VERSION 5.8 ;
BUSBITCHARS "[]" ;
DIVIDERCHAR "/" ;
UNITS
    DATABASE MICRONS 1000 ;
END UNITS

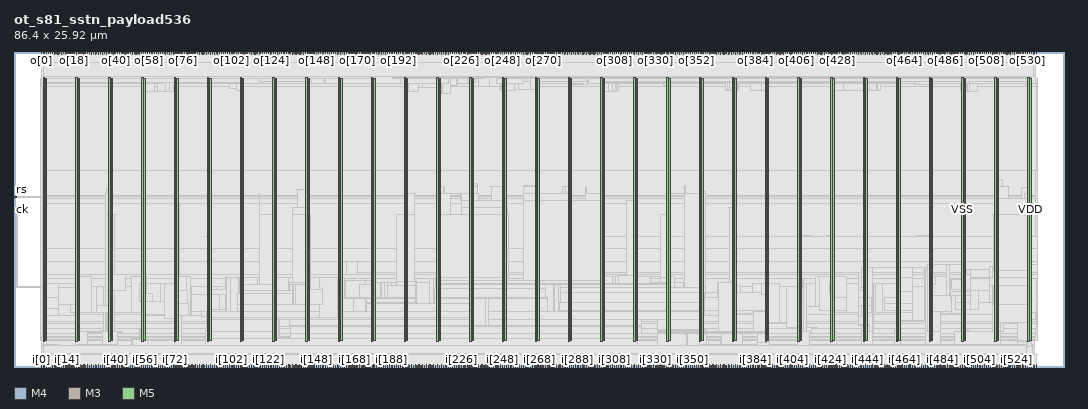
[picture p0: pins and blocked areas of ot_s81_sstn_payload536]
MACRO ot_s81_sstn_payload536
  FOREIGN ot_s81_sstn_payload536 0 0 ;
  CLASS BLOCK ;
  SIZE 86.4 BY 25.92 ;
  PIN ck
    DIRECTION INPUT ;
    USE SIGNAL ;
    PORT
      LAYER M4 ;
        RECT  0 12.96 0.192 12.984 ;
    END
  END ck
  PIN i[0]
    DIRECTION INPUT ;
    USE SIGNAL ;
    PORT
      LAYER M3 ;
        RECT  2.232 0 2.25 0.144 ;
    END
  END i[0]
  PIN i[100]
    DIRECTION INPUT ;
    USE SIGNAL ;
    PORT
      LAYER M3 ;
        RECT  17.532 0 17.55 0.144 ;
    END
  END i[100]
  PIN i[101]
    DIRECTION INPUT ;
    USE SIGNAL ;
    PORT
      LAYER M5 ;
        RECT  17.712 0 17.736 0.192 ;
    END
  END i[101]
  PIN i[102]
    DIRECTION INPUT ;
    USE SIGNAL ;
    PORT
      LAYER M3 ;
        RECT  17.856 0 17.874 0.144 ;
    END
  END i[102]
  PIN i[103]
    DIRECTION INPUT ;
    USE SIGNAL ;
    PORT
      LAYER M5 ;
        RECT  18 0 18.024 0.192 ;
    END
  END i[103]
  PIN i[104]
    DIRECTION INPUT ;
    USE SIGNAL ;
    PORT
      LAYER M3 ;
        RECT  18.144 0 18.162 0.144 ;
    END
  END i[104]
  PIN i[105]
    DIRECTION INPUT ;
    USE SIGNAL ;
    PORT
      LAYER M5 ;
        RECT  18.288 0 18.312 0.192 ;
    END
  END i[105]
  PIN i[106]
    DIRECTION INPUT ;
    USE SIGNAL ;
    PORT
      LAYER M3 ;
        RECT  18.468 0 18.486 0.144 ;
    END
  END i[106]
  PIN i[107]
    DIRECTION INPUT ;
    USE SIGNAL ;
    PORT
      LAYER M5 ;
        RECT  18.624 0 18.648 0.192 ;
    END
  END i[107]
  PIN i[108]
    DIRECTION INPUT ;
    USE SIGNAL ;
    PORT
      LAYER M3 ;
        RECT  18.756 0 18.774 0.144 ;
    END
  END i[108]
  PIN i[109]
    DIRECTION INPUT ;
    USE SIGNAL ;
    PORT
      LAYER M5 ;
        RECT  18.912 0 18.936 0.192 ;
    END
  END i[109]
  PIN i[10]
    DIRECTION INPUT ;
    USE SIGNAL ;
    PORT
      LAYER M3 ;
        RECT  3.744 0 3.762 0.144 ;
    END
  END i[10]
  PIN i[110]
    DIRECTION INPUT ;
    USE SIGNAL ;
    PORT
      LAYER M3 ;
        RECT  19.08 0 19.098 0.144 ;
    END
  END i[110]
  PIN i[111]
    DIRECTION INPUT ;
    USE SIGNAL ;
    PORT
      LAYER M5 ;
        RECT  19.2 0 19.224 0.192 ;
    END
  END i[111]
  PIN i[112]
    DIRECTION INPUT ;
    USE SIGNAL ;
    PORT
      LAYER M3 ;
        RECT  19.368 0 19.386 0.144 ;
    END
  END i[112]
  PIN i[113]
    DIRECTION INPUT ;
    USE SIGNAL ;
    PORT
      LAYER M5 ;
        RECT  19.536 0 19.56 0.192 ;
    END
  END i[113]
  PIN i[114]
    DIRECTION INPUT ;
    USE SIGNAL ;
    PORT
      LAYER M3 ;
        RECT  19.692 0 19.71 0.144 ;
    END
  END i[114]
  PIN i[115]
    DIRECTION INPUT ;
    USE SIGNAL ;
    PORT
      LAYER M5 ;
        RECT  19.824 0 19.848 0.192 ;
    END
  END i[115]
  PIN i[116]
    DIRECTION INPUT ;
    USE SIGNAL ;
    PORT
      LAYER M3 ;
        RECT  19.98 0 19.998 0.144 ;
    END
  END i[116]
  PIN i[117]
    DIRECTION INPUT ;
    USE SIGNAL ;
    PORT
      LAYER M5 ;
        RECT  20.16 0 20.184 0.192 ;
    END
  END i[117]
  PIN i[118]
    DIRECTION INPUT ;
    USE SIGNAL ;
    PORT
      LAYER M3 ;
        RECT  20.304 0 20.322 0.144 ;
    END
  END i[118]
  PIN i[119]
    DIRECTION INPUT ;
    USE SIGNAL ;
    PORT
      LAYER M5 ;
        RECT  20.448 0 20.472 0.192 ;
    END
  END i[119]
  PIN i[11]
    DIRECTION INPUT ;
    USE SIGNAL ;
    PORT
      LAYER M5 ;
        RECT  3.888 0 3.912 0.192 ;
    END
  END i[11]
  PIN i[120]
    DIRECTION INPUT ;
    USE SIGNAL ;
    PORT
      LAYER M3 ;
        RECT  20.592 0 20.61 0.144 ;
    END
  END i[120]
  PIN i[121]
    DIRECTION INPUT ;
    USE SIGNAL ;
    PORT
      LAYER M5 ;
        RECT  20.736 0 20.76 0.192 ;
    END
  END i[121]
  PIN i[122]
    DIRECTION INPUT ;
    USE SIGNAL ;
    PORT
      LAYER M3 ;
        RECT  20.916 0 20.934 0.144 ;
    END
  END i[122]
  PIN i[123]
    DIRECTION INPUT ;
    USE SIGNAL ;
    PORT
      LAYER M5 ;
        RECT  21.072 0 21.096 0.192 ;
    END
  END i[123]
  PIN i[124]
    DIRECTION INPUT ;
    USE SIGNAL ;
    PORT
      LAYER M3 ;
        RECT  21.204 0 21.222 0.144 ;
    END
  END i[124]
  PIN i[125]
    DIRECTION INPUT ;
    USE SIGNAL ;
    PORT
      LAYER M5 ;
        RECT  21.36 0 21.384 0.192 ;
    END
  END i[125]
  PIN i[126]
    DIRECTION INPUT ;
    USE SIGNAL ;
    PORT
      LAYER M3 ;
        RECT  21.528 0 21.546 0.144 ;
    END
  END i[126]
  PIN i[127]
    DIRECTION INPUT ;
    USE SIGNAL ;
    PORT
      LAYER M5 ;
        RECT  21.696 0 21.72 0.192 ;
    END
  END i[127]
  PIN i[128]
    DIRECTION INPUT ;
    USE SIGNAL ;
    PORT
      LAYER M3 ;
        RECT  21.816 0 21.834 0.144 ;
    END
  END i[128]
  PIN i[129]
    DIRECTION INPUT ;
    USE SIGNAL ;
    PORT
      LAYER M5 ;
        RECT  21.984 0 22.008 0.192 ;
    END
  END i[129]
  PIN i[12]
    DIRECTION INPUT ;
    USE SIGNAL ;
    PORT
      LAYER M3 ;
        RECT  4.068 0 4.086 0.144 ;
    END
  END i[12]
  PIN i[130]
    DIRECTION INPUT ;
    USE SIGNAL ;
    PORT
      LAYER M3 ;
        RECT  22.14 0 22.158 0.144 ;
    END
  END i[130]
  PIN i[131]
    DIRECTION INPUT ;
    USE SIGNAL ;
    PORT
      LAYER M5 ;
        RECT  22.272 0 22.296 0.192 ;
    END
  END i[131]
  PIN i[132]
    DIRECTION INPUT ;
    USE SIGNAL ;
    PORT
      LAYER M3 ;
        RECT  22.428 0 22.446 0.144 ;
    END
  END i[132]
  PIN i[133]
    DIRECTION INPUT ;
    USE SIGNAL ;
    PORT
      LAYER M5 ;
        RECT  22.608 0 22.632 0.192 ;
    END
  END i[133]
  PIN i[134]
    DIRECTION INPUT ;
    USE SIGNAL ;
    PORT
      LAYER M3 ;
        RECT  22.752 0 22.77 0.144 ;
    END
  END i[134]
  PIN i[135]
    DIRECTION INPUT ;
    USE SIGNAL ;
    PORT
      LAYER M5 ;
        RECT  22.896 0 22.92 0.192 ;
    END
  END i[135]
  PIN i[136]
    DIRECTION INPUT ;
    USE SIGNAL ;
    PORT
      LAYER M3 ;
        RECT  23.04 0 23.058 0.144 ;
    END
  END i[136]
  PIN i[137]
    DIRECTION INPUT ;
    USE SIGNAL ;
    PORT
      LAYER M5 ;
        RECT  23.184 0 23.208 0.192 ;
    END
  END i[137]
  PIN i[138]
    DIRECTION INPUT ;
    USE SIGNAL ;
    PORT
      LAYER M3 ;
        RECT  23.364 0 23.382 0.144 ;
    END
  END i[138]
  PIN i[139]
    DIRECTION INPUT ;
    USE SIGNAL ;
    PORT
      LAYER M5 ;
        RECT  23.52 0 23.544 0.192 ;
    END
  END i[139]
  PIN i[13]
    DIRECTION INPUT ;
    USE SIGNAL ;
    PORT
      LAYER M5 ;
        RECT  4.224 0 4.248 0.192 ;
    END
  END i[13]
  PIN i[140]
    DIRECTION INPUT ;
    USE SIGNAL ;
    PORT
      LAYER M3 ;
        RECT  23.652 0 23.67 0.144 ;
    END
  END i[140]
  PIN i[141]
    DIRECTION INPUT ;
    USE SIGNAL ;
    PORT
      LAYER M5 ;
        RECT  23.808 0 23.832 0.192 ;
    END
  END i[141]
  PIN i[142]
    DIRECTION INPUT ;
    USE SIGNAL ;
    PORT
      LAYER M3 ;
        RECT  23.976 0 23.994 0.144 ;
    END
  END i[142]
  PIN i[143]
    DIRECTION INPUT ;
    USE SIGNAL ;
    PORT
      LAYER M5 ;
        RECT  24.144 0 24.168 0.192 ;
    END
  END i[143]
  PIN i[144]
    DIRECTION INPUT ;
    USE SIGNAL ;
    PORT
      LAYER M3 ;
        RECT  24.264 0 24.282 0.144 ;
    END
  END i[144]
  PIN i[145]
    DIRECTION INPUT ;
    USE SIGNAL ;
    PORT
      LAYER M5 ;
        RECT  24.432 0 24.456 0.192 ;
    END
  END i[145]
  PIN i[146]
    DIRECTION INPUT ;
    USE SIGNAL ;
    PORT
      LAYER M3 ;
        RECT  24.588 0 24.606 0.144 ;
    END
  END i[146]
  PIN i[147]
    DIRECTION INPUT ;
    USE SIGNAL ;
    PORT
      LAYER M5 ;
        RECT  24.72 0 24.744 0.192 ;
    END
  END i[147]
  PIN i[148]
    DIRECTION INPUT ;
    USE SIGNAL ;
    PORT
      LAYER M3 ;
        RECT  24.876 0 24.894 0.144 ;
    END
  END i[148]
  PIN i[149]
    DIRECTION INPUT ;
    USE SIGNAL ;
    PORT
      LAYER M5 ;
        RECT  25.056 0 25.08 0.192 ;
    END
  END i[149]
  PIN i[14]
    DIRECTION INPUT ;
    USE SIGNAL ;
    PORT
      LAYER M3 ;
        RECT  4.356 0 4.374 0.144 ;
    END
  END i[14]
  PIN i[150]
    DIRECTION INPUT ;
    USE SIGNAL ;
    PORT
      LAYER M3 ;
        RECT  25.2 0 25.218 0.144 ;
    END
  END i[150]
  PIN i[151]
    DIRECTION INPUT ;
    USE SIGNAL ;
    PORT
      LAYER M5 ;
        RECT  25.344 0 25.368 0.192 ;
    END
  END i[151]
  PIN i[152]
    DIRECTION INPUT ;
    USE SIGNAL ;
    PORT
      LAYER M3 ;
        RECT  25.488 0 25.506 0.144 ;
    END
  END i[152]
  PIN i[153]
    DIRECTION INPUT ;
    USE SIGNAL ;
    PORT
      LAYER M5 ;
        RECT  25.632 0 25.656 0.192 ;
    END
  END i[153]
  PIN i[154]
    DIRECTION INPUT ;
    USE SIGNAL ;
    PORT
      LAYER M3 ;
        RECT  25.812 0 25.83 0.144 ;
    END
  END i[154]
  PIN i[155]
    DIRECTION INPUT ;
    USE SIGNAL ;
    PORT
      LAYER M5 ;
        RECT  25.968 0 25.992 0.192 ;
    END
  END i[155]
  PIN i[156]
    DIRECTION INPUT ;
    USE SIGNAL ;
    PORT
      LAYER M3 ;
        RECT  26.1 0 26.118 0.144 ;
    END
  END i[156]
  PIN i[157]
    DIRECTION INPUT ;
    USE SIGNAL ;
    PORT
      LAYER M5 ;
        RECT  26.256 0 26.28 0.192 ;
    END
  END i[157]
  PIN i[158]
    DIRECTION INPUT ;
    USE SIGNAL ;
    PORT
      LAYER M3 ;
        RECT  26.424 0 26.442 0.144 ;
    END
  END i[158]
  PIN i[159]
    DIRECTION INPUT ;
    USE SIGNAL ;
    PORT
      LAYER M5 ;
        RECT  26.592 0 26.616 0.192 ;
    END
  END i[159]
  PIN i[15]
    DIRECTION INPUT ;
    USE SIGNAL ;
    PORT
      LAYER M5 ;
        RECT  4.512 0 4.536 0.192 ;
    END
  END i[15]
  PIN i[160]
    DIRECTION INPUT ;
    USE SIGNAL ;
    PORT
      LAYER M3 ;
        RECT  26.712 0 26.73 0.144 ;
    END
  END i[160]
  PIN i[161]
    DIRECTION INPUT ;
    USE SIGNAL ;
    PORT
      LAYER M5 ;
        RECT  26.88 0 26.904 0.192 ;
    END
  END i[161]
  PIN i[162]
    DIRECTION INPUT ;
    USE SIGNAL ;
    PORT
      LAYER M3 ;
        RECT  27.036 0 27.054 0.144 ;
    END
  END i[162]
  PIN i[163]
    DIRECTION INPUT ;
    USE SIGNAL ;
    PORT
      LAYER M5 ;
        RECT  27.168 0 27.192 0.192 ;
    END
  END i[163]
  PIN i[164]
    DIRECTION INPUT ;
    USE SIGNAL ;
    PORT
      LAYER M3 ;
        RECT  27.324 0 27.342 0.144 ;
    END
  END i[164]
  PIN i[165]
    DIRECTION INPUT ;
    USE SIGNAL ;
    PORT
      LAYER M5 ;
        RECT  27.504 0 27.528 0.192 ;
    END
  END i[165]
  PIN i[166]
    DIRECTION INPUT ;
    USE SIGNAL ;
    PORT
      LAYER M3 ;
        RECT  27.648 0 27.666 0.144 ;
    END
  END i[166]
  PIN i[167]
    DIRECTION INPUT ;
    USE SIGNAL ;
    PORT
      LAYER M5 ;
        RECT  27.792 0 27.816 0.192 ;
    END
  END i[167]
  PIN i[168]
    DIRECTION INPUT ;
    USE SIGNAL ;
    PORT
      LAYER M3 ;
        RECT  27.972 0 27.99 0.144 ;
    END
  END i[168]
  PIN i[169]
    DIRECTION INPUT ;
    USE SIGNAL ;
    PORT
      LAYER M5 ;
        RECT  28.128 0 28.152 0.192 ;
    END
  END i[169]
  PIN i[16]
    DIRECTION INPUT ;
    USE SIGNAL ;
    PORT
      LAYER M3 ;
        RECT  4.68 0 4.698 0.144 ;
    END
  END i[16]
  PIN i[170]
    DIRECTION INPUT ;
    USE SIGNAL ;
    PORT
      LAYER M3 ;
        RECT  28.26 0 28.278 0.144 ;
    END
  END i[170]
  PIN i[171]
    DIRECTION INPUT ;
    USE SIGNAL ;
    PORT
      LAYER M5 ;
        RECT  28.416 0 28.44 0.192 ;
    END
  END i[171]
  PIN i[172]
    DIRECTION INPUT ;
    USE SIGNAL ;
    PORT
      LAYER M3 ;
        RECT  28.584 0 28.602 0.144 ;
    END
  END i[172]
  PIN i[173]
    DIRECTION INPUT ;
    USE SIGNAL ;
    PORT
      LAYER M5 ;
        RECT  28.704 0 28.728 0.192 ;
    END
  END i[173]
  PIN i[174]
    DIRECTION INPUT ;
    USE SIGNAL ;
    PORT
      LAYER M3 ;
        RECT  28.872 0 28.89 0.144 ;
    END
  END i[174]
  PIN i[175]
    DIRECTION INPUT ;
    USE SIGNAL ;
    PORT
      LAYER M5 ;
        RECT  29.04 0 29.064 0.192 ;
    END
  END i[175]
  PIN i[176]
    DIRECTION INPUT ;
    USE SIGNAL ;
    PORT
      LAYER M3 ;
        RECT  29.196 0 29.214 0.144 ;
    END
  END i[176]
  PIN i[177]
    DIRECTION INPUT ;
    USE SIGNAL ;
    PORT
      LAYER M5 ;
        RECT  29.328 0 29.352 0.192 ;
    END
  END i[177]
  PIN i[178]
    DIRECTION INPUT ;
    USE SIGNAL ;
    PORT
      LAYER M3 ;
        RECT  29.484 0 29.502 0.144 ;
    END
  END i[178]
  PIN i[179]
    DIRECTION INPUT ;
    USE SIGNAL ;
    PORT
      LAYER M5 ;
        RECT  29.616 0 29.64 0.192 ;
    END
  END i[179]
  PIN i[17]
    DIRECTION INPUT ;
    USE SIGNAL ;
    PORT
      LAYER M5 ;
        RECT  4.848 0 4.872 0.192 ;
    END
  END i[17]
  PIN i[180]
    DIRECTION INPUT ;
    USE SIGNAL ;
    PORT
      LAYER M3 ;
        RECT  29.808 0 29.826 0.144 ;
    END
  END i[180]
  PIN i[181]
    DIRECTION INPUT ;
    USE SIGNAL ;
    PORT
      LAYER M5 ;
        RECT  29.952 0 29.976 0.192 ;
    END
  END i[181]
  PIN i[182]
    DIRECTION INPUT ;
    USE SIGNAL ;
    PORT
      LAYER M3 ;
        RECT  30.096 0 30.114 0.144 ;
    END
  END i[182]
  PIN i[183]
    DIRECTION INPUT ;
    USE SIGNAL ;
    PORT
      LAYER M5 ;
        RECT  30.24 0 30.264 0.192 ;
    END
  END i[183]
  PIN i[184]
    DIRECTION INPUT ;
    USE SIGNAL ;
    PORT
      LAYER M3 ;
        RECT  30.42 0 30.438 0.144 ;
    END
  END i[184]
  PIN i[185]
    DIRECTION INPUT ;
    USE SIGNAL ;
    PORT
      LAYER M5 ;
        RECT  30.576 0 30.6 0.192 ;
    END
  END i[185]
  PIN i[186]
    DIRECTION INPUT ;
    USE SIGNAL ;
    PORT
      LAYER M3 ;
        RECT  30.708 0 30.726 0.144 ;
    END
  END i[186]
  PIN i[187]
    DIRECTION INPUT ;
    USE SIGNAL ;
    PORT
      LAYER M5 ;
        RECT  30.864 0 30.888 0.192 ;
    END
  END i[187]
  PIN i[188]
    DIRECTION INPUT ;
    USE SIGNAL ;
    PORT
      LAYER M3 ;
        RECT  31.032 0 31.05 0.144 ;
    END
  END i[188]
  PIN i[189]
    DIRECTION INPUT ;
    USE SIGNAL ;
    PORT
      LAYER M5 ;
        RECT  31.152 0 31.176 0.192 ;
    END
  END i[189]
  PIN i[18]
    DIRECTION INPUT ;
    USE SIGNAL ;
    PORT
      LAYER M3 ;
        RECT  4.968 0 4.986 0.144 ;
    END
  END i[18]
  PIN i[190]
    DIRECTION INPUT ;
    USE SIGNAL ;
    PORT
      LAYER M3 ;
        RECT  31.32 0 31.338 0.144 ;
    END
  END i[190]
  PIN i[191]
    DIRECTION INPUT ;
    USE SIGNAL ;
    PORT
      LAYER M5 ;
        RECT  31.488 0 31.512 0.192 ;
    END
  END i[191]
  PIN i[192]
    DIRECTION INPUT ;
    USE SIGNAL ;
    PORT
      LAYER M3 ;
        RECT  31.644 0 31.662 0.144 ;
    END
  END i[192]
  PIN i[193]
    DIRECTION INPUT ;
    USE SIGNAL ;
    PORT
      LAYER M5 ;
        RECT  31.776 0 31.8 0.192 ;
    END
  END i[193]
  PIN i[194]
    DIRECTION INPUT ;
    USE SIGNAL ;
    PORT
      LAYER M3 ;
        RECT  31.932 0 31.95 0.144 ;
    END
  END i[194]
  PIN i[195]
    DIRECTION INPUT ;
    USE SIGNAL ;
    PORT
      LAYER M5 ;
        RECT  32.064 0 32.088 0.192 ;
    END
  END i[195]
  PIN i[196]
    DIRECTION INPUT ;
    USE SIGNAL ;
    PORT
      LAYER M3 ;
        RECT  32.256 0 32.274 0.144 ;
    END
  END i[196]
  PIN i[197]
    DIRECTION INPUT ;
    USE SIGNAL ;
    PORT
      LAYER M5 ;
        RECT  32.4 0 32.424 0.192 ;
    END
  END i[197]
  PIN i[198]
    DIRECTION INPUT ;
    USE SIGNAL ;
    PORT
      LAYER M3 ;
        RECT  32.544 0 32.562 0.144 ;
    END
  END i[198]
  PIN i[199]
    DIRECTION INPUT ;
    USE SIGNAL ;
    PORT
      LAYER M5 ;
        RECT  32.688 0 32.712 0.192 ;
    END
  END i[199]
  PIN i[19]
    DIRECTION INPUT ;
    USE SIGNAL ;
    PORT
      LAYER M5 ;
        RECT  5.136 0 5.16 0.192 ;
    END
  END i[19]
  PIN i[1]
    DIRECTION INPUT ;
    USE SIGNAL ;
    PORT
      LAYER M5 ;
        RECT  2.4 0 2.424 0.192 ;
    END
  END i[1]
  PIN i[200]
    DIRECTION INPUT ;
    USE SIGNAL ;
    PORT
      LAYER M3 ;
        RECT  32.868 0 32.886 0.144 ;
    END
  END i[200]
  PIN i[201]
    DIRECTION INPUT ;
    USE SIGNAL ;
    PORT
      LAYER M5 ;
        RECT  33.024 0 33.048 0.192 ;
    END
  END i[201]
  PIN i[202]
    DIRECTION INPUT ;
    USE SIGNAL ;
    PORT
      LAYER M3 ;
        RECT  33.156 0 33.174 0.144 ;
    END
  END i[202]
  PIN i[203]
    DIRECTION INPUT ;
    USE SIGNAL ;
    PORT
      LAYER M5 ;
        RECT  33.312 0 33.336 0.192 ;
    END
  END i[203]
  PIN i[204]
    DIRECTION INPUT ;
    USE SIGNAL ;
    PORT
      LAYER M3 ;
        RECT  33.48 0 33.498 0.144 ;
    END
  END i[204]
  PIN i[205]
    DIRECTION INPUT ;
    USE SIGNAL ;
    PORT
      LAYER M5 ;
        RECT  33.6 0 33.624 0.192 ;
    END
  END i[205]
  PIN i[206]
    DIRECTION INPUT ;
    USE SIGNAL ;
    PORT
      LAYER M3 ;
        RECT  33.768 0 33.786 0.144 ;
    END
  END i[206]
  PIN i[207]
    DIRECTION INPUT ;
    USE SIGNAL ;
    PORT
      LAYER M5 ;
        RECT  33.936 0 33.96 0.192 ;
    END
  END i[207]
  PIN i[208]
    DIRECTION INPUT ;
    USE SIGNAL ;
    PORT
      LAYER M3 ;
        RECT  34.092 0 34.11 0.144 ;
    END
  END i[208]
  PIN i[209]
    DIRECTION INPUT ;
    USE SIGNAL ;
    PORT
      LAYER M5 ;
        RECT  34.224 0 34.248 0.192 ;
    END
  END i[209]
  PIN i[20]
    DIRECTION INPUT ;
    USE SIGNAL ;
    PORT
      LAYER M3 ;
        RECT  5.292 0 5.31 0.144 ;
    END
  END i[20]
  PIN i[210]
    DIRECTION INPUT ;
    USE SIGNAL ;
    PORT
      LAYER M3 ;
        RECT  34.38 0 34.398 0.144 ;
    END
  END i[210]
  PIN i[211]
    DIRECTION INPUT ;
    USE SIGNAL ;
    PORT
      LAYER M5 ;
        RECT  34.512 0 34.536 0.192 ;
    END
  END i[211]
  PIN i[212]
    DIRECTION INPUT ;
    USE SIGNAL ;
    PORT
      LAYER M3 ;
        RECT  34.704 0 34.722 0.144 ;
    END
  END i[212]
  PIN i[213]
    DIRECTION INPUT ;
    USE SIGNAL ;
    PORT
      LAYER M5 ;
        RECT  34.848 0 34.872 0.192 ;
    END
  END i[213]
  PIN i[214]
    DIRECTION INPUT ;
    USE SIGNAL ;
    PORT
      LAYER M3 ;
        RECT  34.992 0 35.01 0.144 ;
    END
  END i[214]
  PIN i[215]
    DIRECTION INPUT ;
    USE SIGNAL ;
    PORT
      LAYER M5 ;
        RECT  35.136 0 35.16 0.192 ;
    END
  END i[215]
  PIN i[216]
    DIRECTION INPUT ;
    USE SIGNAL ;
    PORT
      LAYER M3 ;
        RECT  35.316 0 35.334 0.144 ;
    END
  END i[216]
  PIN i[217]
    DIRECTION INPUT ;
    USE SIGNAL ;
    PORT
      LAYER M5 ;
        RECT  35.472 0 35.496 0.192 ;
    END
  END i[217]
  PIN i[218]
    DIRECTION INPUT ;
    USE SIGNAL ;
    PORT
      LAYER M3 ;
        RECT  35.604 0 35.622 0.144 ;
    END
  END i[218]
  PIN i[219]
    DIRECTION INPUT ;
    USE SIGNAL ;
    PORT
      LAYER M5 ;
        RECT  35.76 0 35.784 0.192 ;
    END
  END i[219]
  PIN i[21]
    DIRECTION INPUT ;
    USE SIGNAL ;
    PORT
      LAYER M5 ;
        RECT  5.424 0 5.448 0.192 ;
    END
  END i[21]
  PIN i[220]
    DIRECTION INPUT ;
    USE SIGNAL ;
    PORT
      LAYER M3 ;
        RECT  35.928 0 35.946 0.144 ;
    END
  END i[220]
  PIN i[221]
    DIRECTION INPUT ;
    USE SIGNAL ;
    PORT
      LAYER M5 ;
        RECT  36.048 0 36.072 0.192 ;
    END
  END i[221]
  PIN i[222]
    DIRECTION INPUT ;
    USE SIGNAL ;
    PORT
      LAYER M3 ;
        RECT  36.216 0 36.234 0.144 ;
    END
  END i[222]
  PIN i[223]
    DIRECTION INPUT ;
    USE SIGNAL ;
    PORT
      LAYER M5 ;
        RECT  36.384 0 36.408 0.192 ;
    END
  END i[223]
  PIN i[224]
    DIRECTION INPUT ;
    USE SIGNAL ;
    PORT
      LAYER M3 ;
        RECT  36.54 0 36.558 0.144 ;
    END
  END i[224]
  PIN i[225]
    DIRECTION INPUT ;
    USE SIGNAL ;
    PORT
      LAYER M5 ;
        RECT  36.672 0 36.696 0.192 ;
    END
  END i[225]
  PIN i[226]
    DIRECTION INPUT ;
    USE SIGNAL ;
    PORT
      LAYER M3 ;
        RECT  36.828 0 36.846 0.144 ;
    END
  END i[226]
  PIN i[227]
    DIRECTION INPUT ;
    USE SIGNAL ;
    PORT
      LAYER M5 ;
        RECT  37.008 0 37.032 0.192 ;
    END
  END i[227]
  PIN i[228]
    DIRECTION INPUT ;
    USE SIGNAL ;
    PORT
      LAYER M3 ;
        RECT  37.152 0 37.17 0.144 ;
    END
  END i[228]
  PIN i[229]
    DIRECTION INPUT ;
    USE SIGNAL ;
    PORT
      LAYER M5 ;
        RECT  37.296 0 37.32 0.192 ;
    END
  END i[229]
  PIN i[22]
    DIRECTION INPUT ;
    USE SIGNAL ;
    PORT
      LAYER M3 ;
        RECT  5.58 0 5.598 0.144 ;
    END
  END i[22]
  PIN i[230]
    DIRECTION INPUT ;
    USE SIGNAL ;
    PORT
      LAYER M3 ;
        RECT  37.44 0 37.458 0.144 ;
    END
  END i[230]
  PIN i[231]
    DIRECTION INPUT ;
    USE SIGNAL ;
    PORT
      LAYER M5 ;
        RECT  37.584 0 37.608 0.192 ;
    END
  END i[231]
  PIN i[232]
    DIRECTION INPUT ;
    USE SIGNAL ;
    PORT
      LAYER M3 ;
        RECT  37.764 0 37.782 0.144 ;
    END
  END i[232]
  PIN i[233]
    DIRECTION INPUT ;
    USE SIGNAL ;
    PORT
      LAYER M5 ;
        RECT  37.92 0 37.944 0.192 ;
    END
  END i[233]
  PIN i[234]
    DIRECTION INPUT ;
    USE SIGNAL ;
    PORT
      LAYER M3 ;
        RECT  38.052 0 38.07 0.144 ;
    END
  END i[234]
  PIN i[235]
    DIRECTION INPUT ;
    USE SIGNAL ;
    PORT
      LAYER M5 ;
        RECT  38.208 0 38.232 0.192 ;
    END
  END i[235]
  PIN i[236]
    DIRECTION INPUT ;
    USE SIGNAL ;
    PORT
      LAYER M3 ;
        RECT  38.376 0 38.394 0.144 ;
    END
  END i[236]
  PIN i[237]
    DIRECTION INPUT ;
    USE SIGNAL ;
    PORT
      LAYER M5 ;
        RECT  38.496 0 38.52 0.192 ;
    END
  END i[237]
  PIN i[238]
    DIRECTION INPUT ;
    USE SIGNAL ;
    PORT
      LAYER M3 ;
        RECT  38.664 0 38.682 0.144 ;
    END
  END i[238]
  PIN i[239]
    DIRECTION INPUT ;
    USE SIGNAL ;
    PORT
      LAYER M5 ;
        RECT  38.832 0 38.856 0.192 ;
    END
  END i[239]
  PIN i[23]
    DIRECTION INPUT ;
    USE SIGNAL ;
    PORT
      LAYER M5 ;
        RECT  5.76 0 5.784 0.192 ;
    END
  END i[23]
  PIN i[240]
    DIRECTION INPUT ;
    USE SIGNAL ;
    PORT
      LAYER M3 ;
        RECT  38.988 0 39.006 0.144 ;
    END
  END i[240]
  PIN i[241]
    DIRECTION INPUT ;
    USE SIGNAL ;
    PORT
      LAYER M5 ;
        RECT  39.12 0 39.144 0.192 ;
    END
  END i[241]
  PIN i[242]
    DIRECTION INPUT ;
    USE SIGNAL ;
    PORT
      LAYER M3 ;
        RECT  39.276 0 39.294 0.144 ;
    END
  END i[242]
  PIN i[243]
    DIRECTION INPUT ;
    USE SIGNAL ;
    PORT
      LAYER M5 ;
        RECT  39.456 0 39.48 0.192 ;
    END
  END i[243]
  PIN i[244]
    DIRECTION INPUT ;
    USE SIGNAL ;
    PORT
      LAYER M3 ;
        RECT  39.6 0 39.618 0.144 ;
    END
  END i[244]
  PIN i[245]
    DIRECTION INPUT ;
    USE SIGNAL ;
    PORT
      LAYER M5 ;
        RECT  39.744 0 39.768 0.192 ;
    END
  END i[245]
  PIN i[246]
    DIRECTION INPUT ;
    USE SIGNAL ;
    PORT
      LAYER M3 ;
        RECT  39.888 0 39.906 0.144 ;
    END
  END i[246]
  PIN i[247]
    DIRECTION INPUT ;
    USE SIGNAL ;
    PORT
      LAYER M5 ;
        RECT  40.032 0 40.056 0.192 ;
    END
  END i[247]
  PIN i[248]
    DIRECTION INPUT ;
    USE SIGNAL ;
    PORT
      LAYER M3 ;
        RECT  40.212 0 40.23 0.144 ;
    END
  END i[248]
  PIN i[249]
    DIRECTION INPUT ;
    USE SIGNAL ;
    PORT
      LAYER M5 ;
        RECT  40.368 0 40.392 0.192 ;
    END
  END i[249]
  PIN i[24]
    DIRECTION INPUT ;
    USE SIGNAL ;
    PORT
      LAYER M3 ;
        RECT  5.904 0 5.922 0.144 ;
    END
  END i[24]
  PIN i[250]
    DIRECTION INPUT ;
    USE SIGNAL ;
    PORT
      LAYER M3 ;
        RECT  40.5 0 40.518 0.144 ;
    END
  END i[250]
  PIN i[251]
    DIRECTION INPUT ;
    USE SIGNAL ;
    PORT
      LAYER M5 ;
        RECT  40.656 0 40.68 0.192 ;
    END
  END i[251]
  PIN i[252]
    DIRECTION INPUT ;
    USE SIGNAL ;
    PORT
      LAYER M3 ;
        RECT  40.824 0 40.842 0.144 ;
    END
  END i[252]
  PIN i[253]
    DIRECTION INPUT ;
    USE SIGNAL ;
    PORT
      LAYER M5 ;
        RECT  40.944 0 40.968 0.192 ;
    END
  END i[253]
  PIN i[254]
    DIRECTION INPUT ;
    USE SIGNAL ;
    PORT
      LAYER M3 ;
        RECT  41.112 0 41.13 0.144 ;
    END
  END i[254]
  PIN i[255]
    DIRECTION INPUT ;
    USE SIGNAL ;
    PORT
      LAYER M5 ;
        RECT  41.28 0 41.304 0.192 ;
    END
  END i[255]
  PIN i[256]
    DIRECTION INPUT ;
    USE SIGNAL ;
    PORT
      LAYER M3 ;
        RECT  41.436 0 41.454 0.144 ;
    END
  END i[256]
  PIN i[257]
    DIRECTION INPUT ;
    USE SIGNAL ;
    PORT
      LAYER M5 ;
        RECT  41.568 0 41.592 0.192 ;
    END
  END i[257]
  PIN i[258]
    DIRECTION INPUT ;
    USE SIGNAL ;
    PORT
      LAYER M3 ;
        RECT  41.724 0 41.742 0.144 ;
    END
  END i[258]
  PIN i[259]
    DIRECTION INPUT ;
    USE SIGNAL ;
    PORT
      LAYER M5 ;
        RECT  41.904 0 41.928 0.192 ;
    END
  END i[259]
  PIN i[25]
    DIRECTION INPUT ;
    USE SIGNAL ;
    PORT
      LAYER M5 ;
        RECT  6.048 0 6.072 0.192 ;
    END
  END i[25]
  PIN i[260]
    DIRECTION INPUT ;
    USE SIGNAL ;
    PORT
      LAYER M3 ;
        RECT  42.048 0 42.066 0.144 ;
    END
  END i[260]
  PIN i[261]
    DIRECTION INPUT ;
    USE SIGNAL ;
    PORT
      LAYER M5 ;
        RECT  42.192 0 42.216 0.192 ;
    END
  END i[261]
  PIN i[262]
    DIRECTION INPUT ;
    USE SIGNAL ;
    PORT
      LAYER M3 ;
        RECT  42.336 0 42.354 0.144 ;
    END
  END i[262]
  PIN i[263]
    DIRECTION INPUT ;
    USE SIGNAL ;
    PORT
      LAYER M5 ;
        RECT  42.48 0 42.504 0.192 ;
    END
  END i[263]
  PIN i[264]
    DIRECTION INPUT ;
    USE SIGNAL ;
    PORT
      LAYER M3 ;
        RECT  42.66 0 42.678 0.144 ;
    END
  END i[264]
  PIN i[265]
    DIRECTION INPUT ;
    USE SIGNAL ;
    PORT
      LAYER M5 ;
        RECT  42.816 0 42.84 0.192 ;
    END
  END i[265]
  PIN i[266]
    DIRECTION INPUT ;
    USE SIGNAL ;
    PORT
      LAYER M3 ;
        RECT  42.948 0 42.966 0.144 ;
    END
  END i[266]
  PIN i[267]
    DIRECTION INPUT ;
    USE SIGNAL ;
    PORT
      LAYER M5 ;
        RECT  43.104 0 43.128 0.192 ;
    END
  END i[267]
  PIN i[268]
    DIRECTION INPUT ;
    USE SIGNAL ;
    PORT
      LAYER M3 ;
        RECT  43.272 0 43.29 0.144 ;
    END
  END i[268]
  PIN i[269]
    DIRECTION INPUT ;
    USE SIGNAL ;
    PORT
      LAYER M5 ;
        RECT  43.44 0 43.464 0.192 ;
    END
  END i[269]
  PIN i[26]
    DIRECTION INPUT ;
    USE SIGNAL ;
    PORT
      LAYER M3 ;
        RECT  6.192 0 6.21 0.144 ;
    END
  END i[26]
  PIN i[270]
    DIRECTION INPUT ;
    USE SIGNAL ;
    PORT
      LAYER M3 ;
        RECT  43.56 0 43.578 0.144 ;
    END
  END i[270]
  PIN i[271]
    DIRECTION INPUT ;
    USE SIGNAL ;
    PORT
      LAYER M5 ;
        RECT  43.728 0 43.752 0.192 ;
    END
  END i[271]
  PIN i[272]
    DIRECTION INPUT ;
    USE SIGNAL ;
    PORT
      LAYER M3 ;
        RECT  43.884 0 43.902 0.144 ;
    END
  END i[272]
  PIN i[273]
    DIRECTION INPUT ;
    USE SIGNAL ;
    PORT
      LAYER M5 ;
        RECT  44.016 0 44.04 0.192 ;
    END
  END i[273]
  PIN i[274]
    DIRECTION INPUT ;
    USE SIGNAL ;
    PORT
      LAYER M3 ;
        RECT  44.172 0 44.19 0.144 ;
    END
  END i[274]
  PIN i[275]
    DIRECTION INPUT ;
    USE SIGNAL ;
    PORT
      LAYER M5 ;
        RECT  44.352 0 44.376 0.192 ;
    END
  END i[275]
  PIN i[276]
    DIRECTION INPUT ;
    USE SIGNAL ;
    PORT
      LAYER M3 ;
        RECT  44.496 0 44.514 0.144 ;
    END
  END i[276]
  PIN i[277]
    DIRECTION INPUT ;
    USE SIGNAL ;
    PORT
      LAYER M5 ;
        RECT  44.64 0 44.664 0.192 ;
    END
  END i[277]
  PIN i[278]
    DIRECTION INPUT ;
    USE SIGNAL ;
    PORT
      LAYER M3 ;
        RECT  44.784 0 44.802 0.144 ;
    END
  END i[278]
  PIN i[279]
    DIRECTION INPUT ;
    USE SIGNAL ;
    PORT
      LAYER M5 ;
        RECT  44.928 0 44.952 0.192 ;
    END
  END i[279]
  PIN i[27]
    DIRECTION INPUT ;
    USE SIGNAL ;
    PORT
      LAYER M5 ;
        RECT  6.336 0 6.36 0.192 ;
    END
  END i[27]
  PIN i[280]
    DIRECTION INPUT ;
    USE SIGNAL ;
    PORT
      LAYER M3 ;
        RECT  45.108 0 45.126 0.144 ;
    END
  END i[280]
  PIN i[281]
    DIRECTION INPUT ;
    USE SIGNAL ;
    PORT
      LAYER M5 ;
        RECT  45.264 0 45.288 0.192 ;
    END
  END i[281]
  PIN i[282]
    DIRECTION INPUT ;
    USE SIGNAL ;
    PORT
      LAYER M3 ;
        RECT  45.396 0 45.414 0.144 ;
    END
  END i[282]
  PIN i[283]
    DIRECTION INPUT ;
    USE SIGNAL ;
    PORT
      LAYER M5 ;
        RECT  45.552 0 45.576 0.192 ;
    END
  END i[283]
  PIN i[284]
    DIRECTION INPUT ;
    USE SIGNAL ;
    PORT
      LAYER M3 ;
        RECT  45.72 0 45.738 0.144 ;
    END
  END i[284]
  PIN i[285]
    DIRECTION INPUT ;
    USE SIGNAL ;
    PORT
      LAYER M5 ;
        RECT  45.888 0 45.912 0.192 ;
    END
  END i[285]
  PIN i[286]
    DIRECTION INPUT ;
    USE SIGNAL ;
    PORT
      LAYER M3 ;
        RECT  46.008 0 46.026 0.144 ;
    END
  END i[286]
  PIN i[287]
    DIRECTION INPUT ;
    USE SIGNAL ;
    PORT
      LAYER M5 ;
        RECT  46.176 0 46.2 0.192 ;
    END
  END i[287]
  PIN i[288]
    DIRECTION INPUT ;
    USE SIGNAL ;
    PORT
      LAYER M3 ;
        RECT  46.332 0 46.35 0.144 ;
    END
  END i[288]
  PIN i[289]
    DIRECTION INPUT ;
    USE SIGNAL ;
    PORT
      LAYER M5 ;
        RECT  46.464 0 46.488 0.192 ;
    END
  END i[289]
  PIN i[28]
    DIRECTION INPUT ;
    USE SIGNAL ;
    PORT
      LAYER M3 ;
        RECT  6.516 0 6.534 0.144 ;
    END
  END i[28]
  PIN i[290]
    DIRECTION INPUT ;
    USE SIGNAL ;
    PORT
      LAYER M3 ;
        RECT  46.62 0 46.638 0.144 ;
    END
  END i[290]
  PIN i[291]
    DIRECTION INPUT ;
    USE SIGNAL ;
    PORT
      LAYER M5 ;
        RECT  46.8 0 46.824 0.192 ;
    END
  END i[291]
  PIN i[292]
    DIRECTION INPUT ;
    USE SIGNAL ;
    PORT
      LAYER M3 ;
        RECT  46.944 0 46.962 0.144 ;
    END
  END i[292]
  PIN i[293]
    DIRECTION INPUT ;
    USE SIGNAL ;
    PORT
      LAYER M5 ;
        RECT  47.088 0 47.112 0.192 ;
    END
  END i[293]
  PIN i[294]
    DIRECTION INPUT ;
    USE SIGNAL ;
    PORT
      LAYER M3 ;
        RECT  47.232 0 47.25 0.144 ;
    END
  END i[294]
  PIN i[295]
    DIRECTION INPUT ;
    USE SIGNAL ;
    PORT
      LAYER M5 ;
        RECT  47.376 0 47.4 0.192 ;
    END
  END i[295]
  PIN i[296]
    DIRECTION INPUT ;
    USE SIGNAL ;
    PORT
      LAYER M3 ;
        RECT  47.556 0 47.574 0.144 ;
    END
  END i[296]
  PIN i[297]
    DIRECTION INPUT ;
    USE SIGNAL ;
    PORT
      LAYER M5 ;
        RECT  47.712 0 47.736 0.192 ;
    END
  END i[297]
  PIN i[298]
    DIRECTION INPUT ;
    USE SIGNAL ;
    PORT
      LAYER M3 ;
        RECT  47.844 0 47.862 0.144 ;
    END
  END i[298]
  PIN i[299]
    DIRECTION INPUT ;
    USE SIGNAL ;
    PORT
      LAYER M5 ;
        RECT  48 0 48.024 0.192 ;
    END
  END i[299]
  PIN i[29]
    DIRECTION INPUT ;
    USE SIGNAL ;
    PORT
      LAYER M5 ;
        RECT  6.672 0 6.696 0.192 ;
    END
  END i[29]
  PIN i[2]
    DIRECTION INPUT ;
    USE SIGNAL ;
    PORT
      LAYER M3 ;
        RECT  2.52 0 2.538 0.144 ;
    END
  END i[2]
  PIN i[300]
    DIRECTION INPUT ;
    USE SIGNAL ;
    PORT
      LAYER M3 ;
        RECT  48.168 0 48.186 0.144 ;
    END
  END i[300]
  PIN i[301]
    DIRECTION INPUT ;
    USE SIGNAL ;
    PORT
      LAYER M5 ;
        RECT  48.336 0 48.36 0.192 ;
    END
  END i[301]
  PIN i[302]
    DIRECTION INPUT ;
    USE SIGNAL ;
    PORT
      LAYER M3 ;
        RECT  48.492 0 48.51 0.144 ;
    END
  END i[302]
  PIN i[303]
    DIRECTION INPUT ;
    USE SIGNAL ;
    PORT
      LAYER M5 ;
        RECT  48.624 0 48.648 0.192 ;
    END
  END i[303]
  PIN i[304]
    DIRECTION INPUT ;
    USE SIGNAL ;
    PORT
      LAYER M3 ;
        RECT  48.78 0 48.798 0.144 ;
    END
  END i[304]
  PIN i[305]
    DIRECTION INPUT ;
    USE SIGNAL ;
    PORT
      LAYER M5 ;
        RECT  48.912 0 48.936 0.192 ;
    END
  END i[305]
  PIN i[306]
    DIRECTION INPUT ;
    USE SIGNAL ;
    PORT
      LAYER M3 ;
        RECT  49.104 0 49.122 0.144 ;
    END
  END i[306]
  PIN i[307]
    DIRECTION INPUT ;
    USE SIGNAL ;
    PORT
      LAYER M5 ;
        RECT  49.248 0 49.272 0.192 ;
    END
  END i[307]
  PIN i[308]
    DIRECTION INPUT ;
    USE SIGNAL ;
    PORT
      LAYER M3 ;
        RECT  49.392 0 49.41 0.144 ;
    END
  END i[308]
  PIN i[309]
    DIRECTION INPUT ;
    USE SIGNAL ;
    PORT
      LAYER M5 ;
        RECT  49.536 0 49.56 0.192 ;
    END
  END i[309]
  PIN i[30]
    DIRECTION INPUT ;
    USE SIGNAL ;
    PORT
      LAYER M3 ;
        RECT  6.804 0 6.822 0.144 ;
    END
  END i[30]
  PIN i[310]
    DIRECTION INPUT ;
    USE SIGNAL ;
    PORT
      LAYER M3 ;
        RECT  49.716 0 49.734 0.144 ;
    END
  END i[310]
  PIN i[311]
    DIRECTION INPUT ;
    USE SIGNAL ;
    PORT
      LAYER M5 ;
        RECT  49.872 0 49.896 0.192 ;
    END
  END i[311]
  PIN i[312]
    DIRECTION INPUT ;
    USE SIGNAL ;
    PORT
      LAYER M3 ;
        RECT  50.004 0 50.022 0.144 ;
    END
  END i[312]
  PIN i[313]
    DIRECTION INPUT ;
    USE SIGNAL ;
    PORT
      LAYER M5 ;
        RECT  50.16 0 50.184 0.192 ;
    END
  END i[313]
  PIN i[314]
    DIRECTION INPUT ;
    USE SIGNAL ;
    PORT
      LAYER M3 ;
        RECT  50.328 0 50.346 0.144 ;
    END
  END i[314]
  PIN i[315]
    DIRECTION INPUT ;
    USE SIGNAL ;
    PORT
      LAYER M5 ;
        RECT  50.448 0 50.472 0.192 ;
    END
  END i[315]
  PIN i[316]
    DIRECTION INPUT ;
    USE SIGNAL ;
    PORT
      LAYER M3 ;
        RECT  50.616 0 50.634 0.144 ;
    END
  END i[316]
  PIN i[317]
    DIRECTION INPUT ;
    USE SIGNAL ;
    PORT
      LAYER M5 ;
        RECT  50.784 0 50.808 0.192 ;
    END
  END i[317]
  PIN i[318]
    DIRECTION INPUT ;
    USE SIGNAL ;
    PORT
      LAYER M3 ;
        RECT  50.94 0 50.958 0.144 ;
    END
  END i[318]
  PIN i[319]
    DIRECTION INPUT ;
    USE SIGNAL ;
    PORT
      LAYER M5 ;
        RECT  51.072 0 51.096 0.192 ;
    END
  END i[319]
  PIN i[31]
    DIRECTION INPUT ;
    USE SIGNAL ;
    PORT
      LAYER M5 ;
        RECT  6.96 0 6.984 0.192 ;
    END
  END i[31]
  PIN i[320]
    DIRECTION INPUT ;
    USE SIGNAL ;
    PORT
      LAYER M3 ;
        RECT  51.228 0 51.246 0.144 ;
    END
  END i[320]
  PIN i[321]
    DIRECTION INPUT ;
    USE SIGNAL ;
    PORT
      LAYER M5 ;
        RECT  51.36 0 51.384 0.192 ;
    END
  END i[321]
  PIN i[322]
    DIRECTION INPUT ;
    USE SIGNAL ;
    PORT
      LAYER M3 ;
        RECT  51.552 0 51.57 0.144 ;
    END
  END i[322]
  PIN i[323]
    DIRECTION INPUT ;
    USE SIGNAL ;
    PORT
      LAYER M5 ;
        RECT  51.696 0 51.72 0.192 ;
    END
  END i[323]
  PIN i[324]
    DIRECTION INPUT ;
    USE SIGNAL ;
    PORT
      LAYER M3 ;
        RECT  51.84 0 51.858 0.144 ;
    END
  END i[324]
  PIN i[325]
    DIRECTION INPUT ;
    USE SIGNAL ;
    PORT
      LAYER M5 ;
        RECT  51.984 0 52.008 0.192 ;
    END
  END i[325]
  PIN i[326]
    DIRECTION INPUT ;
    USE SIGNAL ;
    PORT
      LAYER M3 ;
        RECT  52.164 0 52.182 0.144 ;
    END
  END i[326]
  PIN i[327]
    DIRECTION INPUT ;
    USE SIGNAL ;
    PORT
      LAYER M5 ;
        RECT  52.32 0 52.344 0.192 ;
    END
  END i[327]
  PIN i[328]
    DIRECTION INPUT ;
    USE SIGNAL ;
    PORT
      LAYER M3 ;
        RECT  52.452 0 52.47 0.144 ;
    END
  END i[328]
  PIN i[329]
    DIRECTION INPUT ;
    USE SIGNAL ;
    PORT
      LAYER M5 ;
        RECT  52.608 0 52.632 0.192 ;
    END
  END i[329]
  PIN i[32]
    DIRECTION INPUT ;
    USE SIGNAL ;
    PORT
      LAYER M3 ;
        RECT  7.128 0 7.146 0.144 ;
    END
  END i[32]
  PIN i[330]
    DIRECTION INPUT ;
    USE SIGNAL ;
    PORT
      LAYER M3 ;
        RECT  52.776 0 52.794 0.144 ;
    END
  END i[330]
  PIN i[331]
    DIRECTION INPUT ;
    USE SIGNAL ;
    PORT
      LAYER M5 ;
        RECT  52.896 0 52.92 0.192 ;
    END
  END i[331]
  PIN i[332]
    DIRECTION INPUT ;
    USE SIGNAL ;
    PORT
      LAYER M3 ;
        RECT  53.064 0 53.082 0.144 ;
    END
  END i[332]
  PIN i[333]
    DIRECTION INPUT ;
    USE SIGNAL ;
    PORT
      LAYER M5 ;
        RECT  53.232 0 53.256 0.192 ;
    END
  END i[333]
  PIN i[334]
    DIRECTION INPUT ;
    USE SIGNAL ;
    PORT
      LAYER M3 ;
        RECT  53.388 0 53.406 0.144 ;
    END
  END i[334]
  PIN i[335]
    DIRECTION INPUT ;
    USE SIGNAL ;
    PORT
      LAYER M5 ;
        RECT  53.52 0 53.544 0.192 ;
    END
  END i[335]
  PIN i[336]
    DIRECTION INPUT ;
    USE SIGNAL ;
    PORT
      LAYER M3 ;
        RECT  53.676 0 53.694 0.144 ;
    END
  END i[336]
  PIN i[337]
    DIRECTION INPUT ;
    USE SIGNAL ;
    PORT
      LAYER M5 ;
        RECT  53.808 0 53.832 0.192 ;
    END
  END i[337]
  PIN i[338]
    DIRECTION INPUT ;
    USE SIGNAL ;
    PORT
      LAYER M3 ;
        RECT  54 0 54.018 0.144 ;
    END
  END i[338]
  PIN i[339]
    DIRECTION INPUT ;
    USE SIGNAL ;
    PORT
      LAYER M5 ;
        RECT  54.144 0 54.168 0.192 ;
    END
  END i[339]
  PIN i[33]
    DIRECTION INPUT ;
    USE SIGNAL ;
    PORT
      LAYER M5 ;
        RECT  7.296 0 7.32 0.192 ;
    END
  END i[33]
  PIN i[340]
    DIRECTION INPUT ;
    USE SIGNAL ;
    PORT
      LAYER M3 ;
        RECT  54.288 0 54.306 0.144 ;
    END
  END i[340]
  PIN i[341]
    DIRECTION INPUT ;
    USE SIGNAL ;
    PORT
      LAYER M5 ;
        RECT  54.432 0 54.456 0.192 ;
    END
  END i[341]
  PIN i[342]
    DIRECTION INPUT ;
    USE SIGNAL ;
    PORT
      LAYER M3 ;
        RECT  54.612 0 54.63 0.144 ;
    END
  END i[342]
  PIN i[343]
    DIRECTION INPUT ;
    USE SIGNAL ;
    PORT
      LAYER M5 ;
        RECT  54.768 0 54.792 0.192 ;
    END
  END i[343]
  PIN i[344]
    DIRECTION INPUT ;
    USE SIGNAL ;
    PORT
      LAYER M3 ;
        RECT  54.9 0 54.918 0.144 ;
    END
  END i[344]
  PIN i[345]
    DIRECTION INPUT ;
    USE SIGNAL ;
    PORT
      LAYER M5 ;
        RECT  55.056 0 55.08 0.192 ;
    END
  END i[345]
  PIN i[346]
    DIRECTION INPUT ;
    USE SIGNAL ;
    PORT
      LAYER M3 ;
        RECT  55.224 0 55.242 0.144 ;
    END
  END i[346]
  PIN i[347]
    DIRECTION INPUT ;
    USE SIGNAL ;
    PORT
      LAYER M5 ;
        RECT  55.344 0 55.368 0.192 ;
    END
  END i[347]
  PIN i[348]
    DIRECTION INPUT ;
    USE SIGNAL ;
    PORT
      LAYER M3 ;
        RECT  55.512 0 55.53 0.144 ;
    END
  END i[348]
  PIN i[349]
    DIRECTION INPUT ;
    USE SIGNAL ;
    PORT
      LAYER M5 ;
        RECT  55.68 0 55.704 0.192 ;
    END
  END i[349]
  PIN i[34]
    DIRECTION INPUT ;
    USE SIGNAL ;
    PORT
      LAYER M3 ;
        RECT  7.452 0 7.47 0.144 ;
    END
  END i[34]
  PIN i[350]
    DIRECTION INPUT ;
    USE SIGNAL ;
    PORT
      LAYER M3 ;
        RECT  55.836 0 55.854 0.144 ;
    END
  END i[350]
  PIN i[351]
    DIRECTION INPUT ;
    USE SIGNAL ;
    PORT
      LAYER M5 ;
        RECT  55.968 0 55.992 0.192 ;
    END
  END i[351]
  PIN i[352]
    DIRECTION INPUT ;
    USE SIGNAL ;
    PORT
      LAYER M3 ;
        RECT  56.124 0 56.142 0.144 ;
    END
  END i[352]
  PIN i[353]
    DIRECTION INPUT ;
    USE SIGNAL ;
    PORT
      LAYER M5 ;
        RECT  56.304 0 56.328 0.192 ;
    END
  END i[353]
  PIN i[354]
    DIRECTION INPUT ;
    USE SIGNAL ;
    PORT
      LAYER M3 ;
        RECT  56.448 0 56.466 0.144 ;
    END
  END i[354]
  PIN i[355]
    DIRECTION INPUT ;
    USE SIGNAL ;
    PORT
      LAYER M5 ;
        RECT  56.592 0 56.616 0.192 ;
    END
  END i[355]
  PIN i[356]
    DIRECTION INPUT ;
    USE SIGNAL ;
    PORT
      LAYER M3 ;
        RECT  56.736 0 56.754 0.144 ;
    END
  END i[356]
  PIN i[357]
    DIRECTION INPUT ;
    USE SIGNAL ;
    PORT
      LAYER M5 ;
        RECT  56.88 0 56.904 0.192 ;
    END
  END i[357]
  PIN i[358]
    DIRECTION INPUT ;
    USE SIGNAL ;
    PORT
      LAYER M3 ;
        RECT  57.06 0 57.078 0.144 ;
    END
  END i[358]
  PIN i[359]
    DIRECTION INPUT ;
    USE SIGNAL ;
    PORT
      LAYER M5 ;
        RECT  57.216 0 57.24 0.192 ;
    END
  END i[359]
  PIN i[35]
    DIRECTION INPUT ;
    USE SIGNAL ;
    PORT
      LAYER M5 ;
        RECT  7.584 0 7.608 0.192 ;
    END
  END i[35]
  PIN i[360]
    DIRECTION INPUT ;
    USE SIGNAL ;
    PORT
      LAYER M3 ;
        RECT  57.348 0 57.366 0.144 ;
    END
  END i[360]
  PIN i[361]
    DIRECTION INPUT ;
    USE SIGNAL ;
    PORT
      LAYER M5 ;
        RECT  57.504 0 57.528 0.192 ;
    END
  END i[361]
  PIN i[362]
    DIRECTION INPUT ;
    USE SIGNAL ;
    PORT
      LAYER M3 ;
        RECT  57.672 0 57.69 0.144 ;
    END
  END i[362]
  PIN i[363]
    DIRECTION INPUT ;
    USE SIGNAL ;
    PORT
      LAYER M5 ;
        RECT  57.792 0 57.816 0.192 ;
    END
  END i[363]
  PIN i[364]
    DIRECTION INPUT ;
    USE SIGNAL ;
    PORT
      LAYER M3 ;
        RECT  57.96 0 57.978 0.144 ;
    END
  END i[364]
  PIN i[365]
    DIRECTION INPUT ;
    USE SIGNAL ;
    PORT
      LAYER M5 ;
        RECT  58.128 0 58.152 0.192 ;
    END
  END i[365]
  PIN i[366]
    DIRECTION INPUT ;
    USE SIGNAL ;
    PORT
      LAYER M3 ;
        RECT  58.284 0 58.302 0.144 ;
    END
  END i[366]
  PIN i[367]
    DIRECTION INPUT ;
    USE SIGNAL ;
    PORT
      LAYER M5 ;
        RECT  58.416 0 58.44 0.192 ;
    END
  END i[367]
  PIN i[368]
    DIRECTION INPUT ;
    USE SIGNAL ;
    PORT
      LAYER M3 ;
        RECT  58.572 0 58.59 0.144 ;
    END
  END i[368]
  PIN i[369]
    DIRECTION INPUT ;
    USE SIGNAL ;
    PORT
      LAYER M5 ;
        RECT  58.752 0 58.776 0.192 ;
    END
  END i[369]
  PIN i[36]
    DIRECTION INPUT ;
    USE SIGNAL ;
    PORT
      LAYER M3 ;
        RECT  7.74 0 7.758 0.144 ;
    END
  END i[36]
  PIN i[370]
    DIRECTION INPUT ;
    USE SIGNAL ;
    PORT
      LAYER M3 ;
        RECT  58.896 0 58.914 0.144 ;
    END
  END i[370]
  PIN i[371]
    DIRECTION INPUT ;
    USE SIGNAL ;
    PORT
      LAYER M5 ;
        RECT  59.04 0 59.064 0.192 ;
    END
  END i[371]
  PIN i[372]
    DIRECTION INPUT ;
    USE SIGNAL ;
    PORT
      LAYER M3 ;
        RECT  59.184 0 59.202 0.144 ;
    END
  END i[372]
  PIN i[373]
    DIRECTION INPUT ;
    USE SIGNAL ;
    PORT
      LAYER M5 ;
        RECT  59.328 0 59.352 0.192 ;
    END
  END i[373]
  PIN i[374]
    DIRECTION INPUT ;
    USE SIGNAL ;
    PORT
      LAYER M3 ;
        RECT  59.508 0 59.526 0.144 ;
    END
  END i[374]
  PIN i[375]
    DIRECTION INPUT ;
    USE SIGNAL ;
    PORT
      LAYER M5 ;
        RECT  59.664 0 59.688 0.192 ;
    END
  END i[375]
  PIN i[376]
    DIRECTION INPUT ;
    USE SIGNAL ;
    PORT
      LAYER M3 ;
        RECT  59.796 0 59.814 0.144 ;
    END
  END i[376]
  PIN i[377]
    DIRECTION INPUT ;
    USE SIGNAL ;
    PORT
      LAYER M5 ;
        RECT  59.952 0 59.976 0.192 ;
    END
  END i[377]
  PIN i[378]
    DIRECTION INPUT ;
    USE SIGNAL ;
    PORT
      LAYER M3 ;
        RECT  60.12 0 60.138 0.144 ;
    END
  END i[378]
  PIN i[379]
    DIRECTION INPUT ;
    USE SIGNAL ;
    PORT
      LAYER M5 ;
        RECT  60.24 0 60.264 0.192 ;
    END
  END i[379]
  PIN i[37]
    DIRECTION INPUT ;
    USE SIGNAL ;
    PORT
      LAYER M5 ;
        RECT  7.872 0 7.896 0.192 ;
    END
  END i[37]
  PIN i[380]
    DIRECTION INPUT ;
    USE SIGNAL ;
    PORT
      LAYER M3 ;
        RECT  60.408 0 60.426 0.144 ;
    END
  END i[380]
  PIN i[381]
    DIRECTION INPUT ;
    USE SIGNAL ;
    PORT
      LAYER M5 ;
        RECT  60.576 0 60.6 0.192 ;
    END
  END i[381]
  PIN i[382]
    DIRECTION INPUT ;
    USE SIGNAL ;
    PORT
      LAYER M3 ;
        RECT  60.732 0 60.75 0.144 ;
    END
  END i[382]
  PIN i[383]
    DIRECTION INPUT ;
    USE SIGNAL ;
    PORT
      LAYER M5 ;
        RECT  60.864 0 60.888 0.192 ;
    END
  END i[383]
  PIN i[384]
    DIRECTION INPUT ;
    USE SIGNAL ;
    PORT
      LAYER M3 ;
        RECT  61.02 0 61.038 0.144 ;
    END
  END i[384]
  PIN i[385]
    DIRECTION INPUT ;
    USE SIGNAL ;
    PORT
      LAYER M5 ;
        RECT  61.2 0 61.224 0.192 ;
    END
  END i[385]
  PIN i[386]
    DIRECTION INPUT ;
    USE SIGNAL ;
    PORT
      LAYER M3 ;
        RECT  61.344 0 61.362 0.144 ;
    END
  END i[386]
  PIN i[387]
    DIRECTION INPUT ;
    USE SIGNAL ;
    PORT
      LAYER M5 ;
        RECT  61.488 0 61.512 0.192 ;
    END
  END i[387]
  PIN i[388]
    DIRECTION INPUT ;
    USE SIGNAL ;
    PORT
      LAYER M3 ;
        RECT  61.632 0 61.65 0.144 ;
    END
  END i[388]
  PIN i[389]
    DIRECTION INPUT ;
    USE SIGNAL ;
    PORT
      LAYER M5 ;
        RECT  61.776 0 61.8 0.192 ;
    END
  END i[389]
  PIN i[38]
    DIRECTION INPUT ;
    USE SIGNAL ;
    PORT
      LAYER M3 ;
        RECT  8.064 0 8.082 0.144 ;
    END
  END i[38]
  PIN i[390]
    DIRECTION INPUT ;
    USE SIGNAL ;
    PORT
      LAYER M3 ;
        RECT  61.956 0 61.974 0.144 ;
    END
  END i[390]
  PIN i[391]
    DIRECTION INPUT ;
    USE SIGNAL ;
    PORT
      LAYER M5 ;
        RECT  62.112 0 62.136 0.192 ;
    END
  END i[391]
  PIN i[392]
    DIRECTION INPUT ;
    USE SIGNAL ;
    PORT
      LAYER M3 ;
        RECT  62.244 0 62.262 0.144 ;
    END
  END i[392]
  PIN i[393]
    DIRECTION INPUT ;
    USE SIGNAL ;
    PORT
      LAYER M5 ;
        RECT  62.4 0 62.424 0.192 ;
    END
  END i[393]
  PIN i[394]
    DIRECTION INPUT ;
    USE SIGNAL ;
    PORT
      LAYER M3 ;
        RECT  62.568 0 62.586 0.144 ;
    END
  END i[394]
  PIN i[395]
    DIRECTION INPUT ;
    USE SIGNAL ;
    PORT
      LAYER M5 ;
        RECT  62.736 0 62.76 0.192 ;
    END
  END i[395]
  PIN i[396]
    DIRECTION INPUT ;
    USE SIGNAL ;
    PORT
      LAYER M3 ;
        RECT  62.856 0 62.874 0.144 ;
    END
  END i[396]
  PIN i[397]
    DIRECTION INPUT ;
    USE SIGNAL ;
    PORT
      LAYER M5 ;
        RECT  63.024 0 63.048 0.192 ;
    END
  END i[397]
  PIN i[398]
    DIRECTION INPUT ;
    USE SIGNAL ;
    PORT
      LAYER M3 ;
        RECT  63.18 0 63.198 0.144 ;
    END
  END i[398]
  PIN i[399]
    DIRECTION INPUT ;
    USE SIGNAL ;
    PORT
      LAYER M5 ;
        RECT  63.312 0 63.336 0.192 ;
    END
  END i[399]
  PIN i[39]
    DIRECTION INPUT ;
    USE SIGNAL ;
    PORT
      LAYER M5 ;
        RECT  8.208 0 8.232 0.192 ;
    END
  END i[39]
  PIN i[3]
    DIRECTION INPUT ;
    USE SIGNAL ;
    PORT
      LAYER M5 ;
        RECT  2.688 0 2.712 0.192 ;
    END
  END i[3]
  PIN i[400]
    DIRECTION INPUT ;
    USE SIGNAL ;
    PORT
      LAYER M3 ;
        RECT  63.468 0 63.486 0.144 ;
    END
  END i[400]
  PIN i[401]
    DIRECTION INPUT ;
    USE SIGNAL ;
    PORT
      LAYER M5 ;
        RECT  63.648 0 63.672 0.192 ;
    END
  END i[401]
  PIN i[402]
    DIRECTION INPUT ;
    USE SIGNAL ;
    PORT
      LAYER M3 ;
        RECT  63.792 0 63.81 0.144 ;
    END
  END i[402]
  PIN i[403]
    DIRECTION INPUT ;
    USE SIGNAL ;
    PORT
      LAYER M5 ;
        RECT  63.936 0 63.96 0.192 ;
    END
  END i[403]
  PIN i[404]
    DIRECTION INPUT ;
    USE SIGNAL ;
    PORT
      LAYER M3 ;
        RECT  64.08 0 64.098 0.144 ;
    END
  END i[404]
  PIN i[405]
    DIRECTION INPUT ;
    USE SIGNAL ;
    PORT
      LAYER M5 ;
        RECT  64.224 0 64.248 0.192 ;
    END
  END i[405]
  PIN i[406]
    DIRECTION INPUT ;
    USE SIGNAL ;
    PORT
      LAYER M3 ;
        RECT  64.404 0 64.422 0.144 ;
    END
  END i[406]
  PIN i[407]
    DIRECTION INPUT ;
    USE SIGNAL ;
    PORT
      LAYER M5 ;
        RECT  64.56 0 64.584 0.192 ;
    END
  END i[407]
  PIN i[408]
    DIRECTION INPUT ;
    USE SIGNAL ;
    PORT
      LAYER M3 ;
        RECT  64.692 0 64.71 0.144 ;
    END
  END i[408]
  PIN i[409]
    DIRECTION INPUT ;
    USE SIGNAL ;
    PORT
      LAYER M5 ;
        RECT  64.848 0 64.872 0.192 ;
    END
  END i[409]
  PIN i[40]
    DIRECTION INPUT ;
    USE SIGNAL ;
    PORT
      LAYER M3 ;
        RECT  8.352 0 8.37 0.144 ;
    END
  END i[40]
  PIN i[410]
    DIRECTION INPUT ;
    USE SIGNAL ;
    PORT
      LAYER M3 ;
        RECT  65.016 0 65.034 0.144 ;
    END
  END i[410]
  PIN i[411]
    DIRECTION INPUT ;
    USE SIGNAL ;
    PORT
      LAYER M5 ;
        RECT  65.184 0 65.208 0.192 ;
    END
  END i[411]
  PIN i[412]
    DIRECTION INPUT ;
    USE SIGNAL ;
    PORT
      LAYER M3 ;
        RECT  65.304 0 65.322 0.144 ;
    END
  END i[412]
  PIN i[413]
    DIRECTION INPUT ;
    USE SIGNAL ;
    PORT
      LAYER M5 ;
        RECT  65.472 0 65.496 0.192 ;
    END
  END i[413]
  PIN i[414]
    DIRECTION INPUT ;
    USE SIGNAL ;
    PORT
      LAYER M3 ;
        RECT  65.628 0 65.646 0.144 ;
    END
  END i[414]
  PIN i[415]
    DIRECTION INPUT ;
    USE SIGNAL ;
    PORT
      LAYER M5 ;
        RECT  65.76 0 65.784 0.192 ;
    END
  END i[415]
  PIN i[416]
    DIRECTION INPUT ;
    USE SIGNAL ;
    PORT
      LAYER M3 ;
        RECT  65.916 0 65.934 0.144 ;
    END
  END i[416]
  PIN i[417]
    DIRECTION INPUT ;
    USE SIGNAL ;
    PORT
      LAYER M5 ;
        RECT  66.096 0 66.12 0.192 ;
    END
  END i[417]
  PIN i[418]
    DIRECTION INPUT ;
    USE SIGNAL ;
    PORT
      LAYER M3 ;
        RECT  66.24 0 66.258 0.144 ;
    END
  END i[418]
  PIN i[419]
    DIRECTION INPUT ;
    USE SIGNAL ;
    PORT
      LAYER M5 ;
        RECT  66.384 0 66.408 0.192 ;
    END
  END i[419]
  PIN i[41]
    DIRECTION INPUT ;
    USE SIGNAL ;
    PORT
      LAYER M5 ;
        RECT  8.496 0 8.52 0.192 ;
    END
  END i[41]
  PIN i[420]
    DIRECTION INPUT ;
    USE SIGNAL ;
    PORT
      LAYER M3 ;
        RECT  66.528 0 66.546 0.144 ;
    END
  END i[420]
  PIN i[421]
    DIRECTION INPUT ;
    USE SIGNAL ;
    PORT
      LAYER M5 ;
        RECT  66.672 0 66.696 0.192 ;
    END
  END i[421]
  PIN i[422]
    DIRECTION INPUT ;
    USE SIGNAL ;
    PORT
      LAYER M3 ;
        RECT  66.852 0 66.87 0.144 ;
    END
  END i[422]
  PIN i[423]
    DIRECTION INPUT ;
    USE SIGNAL ;
    PORT
      LAYER M5 ;
        RECT  67.008 0 67.032 0.192 ;
    END
  END i[423]
  PIN i[424]
    DIRECTION INPUT ;
    USE SIGNAL ;
    PORT
      LAYER M3 ;
        RECT  67.14 0 67.158 0.144 ;
    END
  END i[424]
  PIN i[425]
    DIRECTION INPUT ;
    USE SIGNAL ;
    PORT
      LAYER M5 ;
        RECT  67.296 0 67.32 0.192 ;
    END
  END i[425]
  PIN i[426]
    DIRECTION INPUT ;
    USE SIGNAL ;
    PORT
      LAYER M3 ;
        RECT  67.464 0 67.482 0.144 ;
    END
  END i[426]
  PIN i[427]
    DIRECTION INPUT ;
    USE SIGNAL ;
    PORT
      LAYER M5 ;
        RECT  67.632 0 67.656 0.192 ;
    END
  END i[427]
  PIN i[428]
    DIRECTION INPUT ;
    USE SIGNAL ;
    PORT
      LAYER M3 ;
        RECT  67.752 0 67.77 0.144 ;
    END
  END i[428]
  PIN i[429]
    DIRECTION INPUT ;
    USE SIGNAL ;
    PORT
      LAYER M5 ;
        RECT  67.92 0 67.944 0.192 ;
    END
  END i[429]
  PIN i[42]
    DIRECTION INPUT ;
    USE SIGNAL ;
    PORT
      LAYER M3 ;
        RECT  8.676 0 8.694 0.144 ;
    END
  END i[42]
  PIN i[430]
    DIRECTION INPUT ;
    USE SIGNAL ;
    PORT
      LAYER M3 ;
        RECT  68.076 0 68.094 0.144 ;
    END
  END i[430]
  PIN i[431]
    DIRECTION INPUT ;
    USE SIGNAL ;
    PORT
      LAYER M5 ;
        RECT  68.208 0 68.232 0.192 ;
    END
  END i[431]
  PIN i[432]
    DIRECTION INPUT ;
    USE SIGNAL ;
    PORT
      LAYER M3 ;
        RECT  68.364 0 68.382 0.144 ;
    END
  END i[432]
  PIN i[433]
    DIRECTION INPUT ;
    USE SIGNAL ;
    PORT
      LAYER M5 ;
        RECT  68.544 0 68.568 0.192 ;
    END
  END i[433]
  PIN i[434]
    DIRECTION INPUT ;
    USE SIGNAL ;
    PORT
      LAYER M3 ;
        RECT  68.688 0 68.706 0.144 ;
    END
  END i[434]
  PIN i[435]
    DIRECTION INPUT ;
    USE SIGNAL ;
    PORT
      LAYER M5 ;
        RECT  68.832 0 68.856 0.192 ;
    END
  END i[435]
  PIN i[436]
    DIRECTION INPUT ;
    USE SIGNAL ;
    PORT
      LAYER M3 ;
        RECT  69.012 0 69.03 0.144 ;
    END
  END i[436]
  PIN i[437]
    DIRECTION INPUT ;
    USE SIGNAL ;
    PORT
      LAYER M5 ;
        RECT  69.168 0 69.192 0.192 ;
    END
  END i[437]
  PIN i[438]
    DIRECTION INPUT ;
    USE SIGNAL ;
    PORT
      LAYER M3 ;
        RECT  69.3 0 69.318 0.144 ;
    END
  END i[438]
  PIN i[439]
    DIRECTION INPUT ;
    USE SIGNAL ;
    PORT
      LAYER M5 ;
        RECT  69.456 0 69.48 0.192 ;
    END
  END i[439]
  PIN i[43]
    DIRECTION INPUT ;
    USE SIGNAL ;
    PORT
      LAYER M5 ;
        RECT  8.832 0 8.856 0.192 ;
    END
  END i[43]
  PIN i[440]
    DIRECTION INPUT ;
    USE SIGNAL ;
    PORT
      LAYER M3 ;
        RECT  69.624 0 69.642 0.144 ;
    END
  END i[440]
  PIN i[441]
    DIRECTION INPUT ;
    USE SIGNAL ;
    PORT
      LAYER M5 ;
        RECT  69.744 0 69.768 0.192 ;
    END
  END i[441]
  PIN i[442]
    DIRECTION INPUT ;
    USE SIGNAL ;
    PORT
      LAYER M3 ;
        RECT  69.912 0 69.93 0.144 ;
    END
  END i[442]
  PIN i[443]
    DIRECTION INPUT ;
    USE SIGNAL ;
    PORT
      LAYER M5 ;
        RECT  70.08 0 70.104 0.192 ;
    END
  END i[443]
  PIN i[444]
    DIRECTION INPUT ;
    USE SIGNAL ;
    PORT
      LAYER M3 ;
        RECT  70.236 0 70.254 0.144 ;
    END
  END i[444]
  PIN i[445]
    DIRECTION INPUT ;
    USE SIGNAL ;
    PORT
      LAYER M5 ;
        RECT  70.368 0 70.392 0.192 ;
    END
  END i[445]
  PIN i[446]
    DIRECTION INPUT ;
    USE SIGNAL ;
    PORT
      LAYER M3 ;
        RECT  70.524 0 70.542 0.144 ;
    END
  END i[446]
  PIN i[447]
    DIRECTION INPUT ;
    USE SIGNAL ;
    PORT
      LAYER M5 ;
        RECT  70.656 0 70.68 0.192 ;
    END
  END i[447]
  PIN i[448]
    DIRECTION INPUT ;
    USE SIGNAL ;
    PORT
      LAYER M3 ;
        RECT  70.848 0 70.866 0.144 ;
    END
  END i[448]
  PIN i[449]
    DIRECTION INPUT ;
    USE SIGNAL ;
    PORT
      LAYER M5 ;
        RECT  70.992 0 71.016 0.192 ;
    END
  END i[449]
  PIN i[44]
    DIRECTION INPUT ;
    USE SIGNAL ;
    PORT
      LAYER M3 ;
        RECT  8.964 0 8.982 0.144 ;
    END
  END i[44]
  PIN i[450]
    DIRECTION INPUT ;
    USE SIGNAL ;
    PORT
      LAYER M3 ;
        RECT  71.136 0 71.154 0.144 ;
    END
  END i[450]
  PIN i[451]
    DIRECTION INPUT ;
    USE SIGNAL ;
    PORT
      LAYER M5 ;
        RECT  71.28 0 71.304 0.192 ;
    END
  END i[451]
  PIN i[452]
    DIRECTION INPUT ;
    USE SIGNAL ;
    PORT
      LAYER M3 ;
        RECT  71.46 0 71.478 0.144 ;
    END
  END i[452]
  PIN i[453]
    DIRECTION INPUT ;
    USE SIGNAL ;
    PORT
      LAYER M5 ;
        RECT  71.616 0 71.64 0.192 ;
    END
  END i[453]
  PIN i[454]
    DIRECTION INPUT ;
    USE SIGNAL ;
    PORT
      LAYER M3 ;
        RECT  71.748 0 71.766 0.144 ;
    END
  END i[454]
  PIN i[455]
    DIRECTION INPUT ;
    USE SIGNAL ;
    PORT
      LAYER M5 ;
        RECT  71.904 0 71.928 0.192 ;
    END
  END i[455]
  PIN i[456]
    DIRECTION INPUT ;
    USE SIGNAL ;
    PORT
      LAYER M3 ;
        RECT  72.072 0 72.09 0.144 ;
    END
  END i[456]
  PIN i[457]
    DIRECTION INPUT ;
    USE SIGNAL ;
    PORT
      LAYER M5 ;
        RECT  72.192 0 72.216 0.192 ;
    END
  END i[457]
  PIN i[458]
    DIRECTION INPUT ;
    USE SIGNAL ;
    PORT
      LAYER M3 ;
        RECT  72.36 0 72.378 0.144 ;
    END
  END i[458]
  PIN i[459]
    DIRECTION INPUT ;
    USE SIGNAL ;
    PORT
      LAYER M5 ;
        RECT  72.528 0 72.552 0.192 ;
    END
  END i[459]
  PIN i[45]
    DIRECTION INPUT ;
    USE SIGNAL ;
    PORT
      LAYER M5 ;
        RECT  9.12 0 9.144 0.192 ;
    END
  END i[45]
  PIN i[460]
    DIRECTION INPUT ;
    USE SIGNAL ;
    PORT
      LAYER M3 ;
        RECT  72.684 0 72.702 0.144 ;
    END
  END i[460]
  PIN i[461]
    DIRECTION INPUT ;
    USE SIGNAL ;
    PORT
      LAYER M5 ;
        RECT  72.816 0 72.84 0.192 ;
    END
  END i[461]
  PIN i[462]
    DIRECTION INPUT ;
    USE SIGNAL ;
    PORT
      LAYER M3 ;
        RECT  72.972 0 72.99 0.144 ;
    END
  END i[462]
  PIN i[463]
    DIRECTION INPUT ;
    USE SIGNAL ;
    PORT
      LAYER M5 ;
        RECT  73.104 0 73.128 0.192 ;
    END
  END i[463]
  PIN i[464]
    DIRECTION INPUT ;
    USE SIGNAL ;
    PORT
      LAYER M3 ;
        RECT  73.296 0 73.314 0.144 ;
    END
  END i[464]
  PIN i[465]
    DIRECTION INPUT ;
    USE SIGNAL ;
    PORT
      LAYER M5 ;
        RECT  73.44 0 73.464 0.192 ;
    END
  END i[465]
  PIN i[466]
    DIRECTION INPUT ;
    USE SIGNAL ;
    PORT
      LAYER M3 ;
        RECT  73.584 0 73.602 0.144 ;
    END
  END i[466]
  PIN i[467]
    DIRECTION INPUT ;
    USE SIGNAL ;
    PORT
      LAYER M5 ;
        RECT  73.728 0 73.752 0.192 ;
    END
  END i[467]
  PIN i[468]
    DIRECTION INPUT ;
    USE SIGNAL ;
    PORT
      LAYER M3 ;
        RECT  73.908 0 73.926 0.144 ;
    END
  END i[468]
  PIN i[469]
    DIRECTION INPUT ;
    USE SIGNAL ;
    PORT
      LAYER M5 ;
        RECT  74.064 0 74.088 0.192 ;
    END
  END i[469]
  PIN i[46]
    DIRECTION INPUT ;
    USE SIGNAL ;
    PORT
      LAYER M3 ;
        RECT  9.288 0 9.306 0.144 ;
    END
  END i[46]
  PIN i[470]
    DIRECTION INPUT ;
    USE SIGNAL ;
    PORT
      LAYER M3 ;
        RECT  74.196 0 74.214 0.144 ;
    END
  END i[470]
  PIN i[471]
    DIRECTION INPUT ;
    USE SIGNAL ;
    PORT
      LAYER M5 ;
        RECT  74.352 0 74.376 0.192 ;
    END
  END i[471]
  PIN i[472]
    DIRECTION INPUT ;
    USE SIGNAL ;
    PORT
      LAYER M3 ;
        RECT  74.52 0 74.538 0.144 ;
    END
  END i[472]
  PIN i[473]
    DIRECTION INPUT ;
    USE SIGNAL ;
    PORT
      LAYER M5 ;
        RECT  74.64 0 74.664 0.192 ;
    END
  END i[473]
  PIN i[474]
    DIRECTION INPUT ;
    USE SIGNAL ;
    PORT
      LAYER M3 ;
        RECT  74.808 0 74.826 0.144 ;
    END
  END i[474]
  PIN i[475]
    DIRECTION INPUT ;
    USE SIGNAL ;
    PORT
      LAYER M5 ;
        RECT  74.976 0 75 0.192 ;
    END
  END i[475]
  PIN i[476]
    DIRECTION INPUT ;
    USE SIGNAL ;
    PORT
      LAYER M3 ;
        RECT  75.132 0 75.15 0.144 ;
    END
  END i[476]
  PIN i[477]
    DIRECTION INPUT ;
    USE SIGNAL ;
    PORT
      LAYER M5 ;
        RECT  75.264 0 75.288 0.192 ;
    END
  END i[477]
  PIN i[478]
    DIRECTION INPUT ;
    USE SIGNAL ;
    PORT
      LAYER M3 ;
        RECT  75.42 0 75.438 0.144 ;
    END
  END i[478]
  PIN i[479]
    DIRECTION INPUT ;
    USE SIGNAL ;
    PORT
      LAYER M5 ;
        RECT  75.552 0 75.576 0.192 ;
    END
  END i[479]
  PIN i[47]
    DIRECTION INPUT ;
    USE SIGNAL ;
    PORT
      LAYER M5 ;
        RECT  9.408 0 9.432 0.192 ;
    END
  END i[47]
  PIN i[480]
    DIRECTION INPUT ;
    USE SIGNAL ;
    PORT
      LAYER M3 ;
        RECT  75.744 0 75.762 0.144 ;
    END
  END i[480]
  PIN i[481]
    DIRECTION INPUT ;
    USE SIGNAL ;
    PORT
      LAYER M5 ;
        RECT  75.888 0 75.912 0.192 ;
    END
  END i[481]
  PIN i[482]
    DIRECTION INPUT ;
    USE SIGNAL ;
    PORT
      LAYER M3 ;
        RECT  76.032 0 76.05 0.144 ;
    END
  END i[482]
  PIN i[483]
    DIRECTION INPUT ;
    USE SIGNAL ;
    PORT
      LAYER M5 ;
        RECT  76.176 0 76.2 0.192 ;
    END
  END i[483]
  PIN i[484]
    DIRECTION INPUT ;
    USE SIGNAL ;
    PORT
      LAYER M3 ;
        RECT  76.356 0 76.374 0.144 ;
    END
  END i[484]
  PIN i[485]
    DIRECTION INPUT ;
    USE SIGNAL ;
    PORT
      LAYER M5 ;
        RECT  76.512 0 76.536 0.192 ;
    END
  END i[485]
  PIN i[486]
    DIRECTION INPUT ;
    USE SIGNAL ;
    PORT
      LAYER M3 ;
        RECT  76.644 0 76.662 0.144 ;
    END
  END i[486]
  PIN i[487]
    DIRECTION INPUT ;
    USE SIGNAL ;
    PORT
      LAYER M5 ;
        RECT  76.8 0 76.824 0.192 ;
    END
  END i[487]
  PIN i[488]
    DIRECTION INPUT ;
    USE SIGNAL ;
    PORT
      LAYER M3 ;
        RECT  76.968 0 76.986 0.144 ;
    END
  END i[488]
  PIN i[489]
    DIRECTION INPUT ;
    USE SIGNAL ;
    PORT
      LAYER M5 ;
        RECT  77.088 0 77.112 0.192 ;
    END
  END i[489]
  PIN i[48]
    DIRECTION INPUT ;
    USE SIGNAL ;
    PORT
      LAYER M3 ;
        RECT  9.576 0 9.594 0.144 ;
    END
  END i[48]
  PIN i[490]
    DIRECTION INPUT ;
    USE SIGNAL ;
    PORT
      LAYER M3 ;
        RECT  77.256 0 77.274 0.144 ;
    END
  END i[490]
  PIN i[491]
    DIRECTION INPUT ;
    USE SIGNAL ;
    PORT
      LAYER M5 ;
        RECT  77.424 0 77.448 0.192 ;
    END
  END i[491]
  PIN i[492]
    DIRECTION INPUT ;
    USE SIGNAL ;
    PORT
      LAYER M3 ;
        RECT  77.58 0 77.598 0.144 ;
    END
  END i[492]
  PIN i[493]
    DIRECTION INPUT ;
    USE SIGNAL ;
    PORT
      LAYER M5 ;
        RECT  77.712 0 77.736 0.192 ;
    END
  END i[493]
  PIN i[494]
    DIRECTION INPUT ;
    USE SIGNAL ;
    PORT
      LAYER M3 ;
        RECT  77.868 0 77.886 0.144 ;
    END
  END i[494]
  PIN i[495]
    DIRECTION INPUT ;
    USE SIGNAL ;
    PORT
      LAYER M5 ;
        RECT  78.048 0 78.072 0.192 ;
    END
  END i[495]
  PIN i[496]
    DIRECTION INPUT ;
    USE SIGNAL ;
    PORT
      LAYER M3 ;
        RECT  78.192 0 78.21 0.144 ;
    END
  END i[496]
  PIN i[497]
    DIRECTION INPUT ;
    USE SIGNAL ;
    PORT
      LAYER M5 ;
        RECT  78.336 0 78.36 0.192 ;
    END
  END i[497]
  PIN i[498]
    DIRECTION INPUT ;
    USE SIGNAL ;
    PORT
      LAYER M3 ;
        RECT  78.48 0 78.498 0.144 ;
    END
  END i[498]
  PIN i[499]
    DIRECTION INPUT ;
    USE SIGNAL ;
    PORT
      LAYER M5 ;
        RECT  78.624 0 78.648 0.192 ;
    END
  END i[499]
  PIN i[49]
    DIRECTION INPUT ;
    USE SIGNAL ;
    PORT
      LAYER M5 ;
        RECT  9.744 0 9.768 0.192 ;
    END
  END i[49]
  PIN i[4]
    DIRECTION INPUT ;
    USE SIGNAL ;
    PORT
      LAYER M3 ;
        RECT  2.844 0 2.862 0.144 ;
    END
  END i[4]
  PIN i[500]
    DIRECTION INPUT ;
    USE SIGNAL ;
    PORT
      LAYER M3 ;
        RECT  78.804 0 78.822 0.144 ;
    END
  END i[500]
  PIN i[501]
    DIRECTION INPUT ;
    USE SIGNAL ;
    PORT
      LAYER M5 ;
        RECT  78.96 0 78.984 0.192 ;
    END
  END i[501]
  PIN i[502]
    DIRECTION INPUT ;
    USE SIGNAL ;
    PORT
      LAYER M3 ;
        RECT  79.092 0 79.11 0.144 ;
    END
  END i[502]
  PIN i[503]
    DIRECTION INPUT ;
    USE SIGNAL ;
    PORT
      LAYER M5 ;
        RECT  79.248 0 79.272 0.192 ;
    END
  END i[503]
  PIN i[504]
    DIRECTION INPUT ;
    USE SIGNAL ;
    PORT
      LAYER M3 ;
        RECT  79.416 0 79.434 0.144 ;
    END
  END i[504]
  PIN i[505]
    DIRECTION INPUT ;
    USE SIGNAL ;
    PORT
      LAYER M5 ;
        RECT  79.536 0 79.56 0.192 ;
    END
  END i[505]
  PIN i[506]
    DIRECTION INPUT ;
    USE SIGNAL ;
    PORT
      LAYER M3 ;
        RECT  79.704 0 79.722 0.144 ;
    END
  END i[506]
  PIN i[507]
    DIRECTION INPUT ;
    USE SIGNAL ;
    PORT
      LAYER M5 ;
        RECT  79.872 0 79.896 0.192 ;
    END
  END i[507]
  PIN i[508]
    DIRECTION INPUT ;
    USE SIGNAL ;
    PORT
      LAYER M3 ;
        RECT  80.028 0 80.046 0.144 ;
    END
  END i[508]
  PIN i[509]
    DIRECTION INPUT ;
    USE SIGNAL ;
    PORT
      LAYER M5 ;
        RECT  80.16 0 80.184 0.192 ;
    END
  END i[509]
  PIN i[50]
    DIRECTION INPUT ;
    USE SIGNAL ;
    PORT
      LAYER M3 ;
        RECT  9.9 0 9.918 0.144 ;
    END
  END i[50]
  PIN i[510]
    DIRECTION INPUT ;
    USE SIGNAL ;
    PORT
      LAYER M3 ;
        RECT  80.316 0 80.334 0.144 ;
    END
  END i[510]
  PIN i[511]
    DIRECTION INPUT ;
    USE SIGNAL ;
    PORT
      LAYER M5 ;
        RECT  80.496 0 80.52 0.192 ;
    END
  END i[511]
  PIN i[512]
    DIRECTION INPUT ;
    USE SIGNAL ;
    PORT
      LAYER M3 ;
        RECT  80.64 0 80.658 0.144 ;
    END
  END i[512]
  PIN i[513]
    DIRECTION INPUT ;
    USE SIGNAL ;
    PORT
      LAYER M5 ;
        RECT  80.784 0 80.808 0.192 ;
    END
  END i[513]
  PIN i[514]
    DIRECTION INPUT ;
    USE SIGNAL ;
    PORT
      LAYER M3 ;
        RECT  80.928 0 80.946 0.144 ;
    END
  END i[514]
  PIN i[515]
    DIRECTION INPUT ;
    USE SIGNAL ;
    PORT
      LAYER M5 ;
        RECT  81.072 0 81.096 0.192 ;
    END
  END i[515]
  PIN i[516]
    DIRECTION INPUT ;
    USE SIGNAL ;
    PORT
      LAYER M3 ;
        RECT  81.252 0 81.27 0.144 ;
    END
  END i[516]
  PIN i[517]
    DIRECTION INPUT ;
    USE SIGNAL ;
    PORT
      LAYER M5 ;
        RECT  81.408 0 81.432 0.192 ;
    END
  END i[517]
  PIN i[518]
    DIRECTION INPUT ;
    USE SIGNAL ;
    PORT
      LAYER M3 ;
        RECT  81.54 0 81.558 0.144 ;
    END
  END i[518]
  PIN i[519]
    DIRECTION INPUT ;
    USE SIGNAL ;
    PORT
      LAYER M5 ;
        RECT  81.696 0 81.72 0.192 ;
    END
  END i[519]
  PIN i[51]
    DIRECTION INPUT ;
    USE SIGNAL ;
    PORT
      LAYER M5 ;
        RECT  10.032 0 10.056 0.192 ;
    END
  END i[51]
  PIN i[520]
    DIRECTION INPUT ;
    USE SIGNAL ;
    PORT
      LAYER M3 ;
        RECT  81.864 0 81.882 0.144 ;
    END
  END i[520]
  PIN i[521]
    DIRECTION INPUT ;
    USE SIGNAL ;
    PORT
      LAYER M5 ;
        RECT  81.984 0 82.008 0.192 ;
    END
  END i[521]
  PIN i[522]
    DIRECTION INPUT ;
    USE SIGNAL ;
    PORT
      LAYER M3 ;
        RECT  82.152 0 82.17 0.144 ;
    END
  END i[522]
  PIN i[523]
    DIRECTION INPUT ;
    USE SIGNAL ;
    PORT
      LAYER M5 ;
        RECT  82.32 0 82.344 0.192 ;
    END
  END i[523]
  PIN i[524]
    DIRECTION INPUT ;
    USE SIGNAL ;
    PORT
      LAYER M3 ;
        RECT  82.476 0 82.494 0.144 ;
    END
  END i[524]
  PIN i[525]
    DIRECTION INPUT ;
    USE SIGNAL ;
    PORT
      LAYER M5 ;
        RECT  82.608 0 82.632 0.192 ;
    END
  END i[525]
  PIN i[526]
    DIRECTION INPUT ;
    USE SIGNAL ;
    PORT
      LAYER M3 ;
        RECT  82.764 0 82.782 0.144 ;
    END
  END i[526]
  PIN i[527]
    DIRECTION INPUT ;
    USE SIGNAL ;
    PORT
      LAYER M5 ;
        RECT  82.944 0 82.968 0.192 ;
    END
  END i[527]
  PIN i[528]
    DIRECTION INPUT ;
    USE SIGNAL ;
    PORT
      LAYER M3 ;
        RECT  83.088 0 83.106 0.144 ;
    END
  END i[528]
  PIN i[529]
    DIRECTION INPUT ;
    USE SIGNAL ;
    PORT
      LAYER M5 ;
        RECT  83.232 0 83.256 0.192 ;
    END
  END i[529]
  PIN i[52]
    DIRECTION INPUT ;
    USE SIGNAL ;
    PORT
      LAYER M3 ;
        RECT  10.188 0 10.206 0.144 ;
    END
  END i[52]
  PIN i[530]
    DIRECTION INPUT ;
    USE SIGNAL ;
    PORT
      LAYER M3 ;
        RECT  83.376 0 83.394 0.144 ;
    END
  END i[530]
  PIN i[531]
    DIRECTION INPUT ;
    USE SIGNAL ;
    PORT
      LAYER M5 ;
        RECT  83.52 0 83.544 0.192 ;
    END
  END i[531]
  PIN i[532]
    DIRECTION INPUT ;
    USE SIGNAL ;
    PORT
      LAYER M3 ;
        RECT  83.7 0 83.718 0.144 ;
    END
  END i[532]
  PIN i[533]
    DIRECTION INPUT ;
    USE SIGNAL ;
    PORT
      LAYER M5 ;
        RECT  83.856 0 83.88 0.192 ;
    END
  END i[533]
  PIN i[534]
    DIRECTION INPUT ;
    USE SIGNAL ;
    PORT
      LAYER M3 ;
        RECT  83.988 0 84.006 0.144 ;
    END
  END i[534]
  PIN i[535]
    DIRECTION INPUT ;
    USE SIGNAL ;
    PORT
      LAYER M5 ;
        RECT  84.144 0 84.168 0.192 ;
    END
  END i[535]
  PIN i[53]
    DIRECTION INPUT ;
    USE SIGNAL ;
    PORT
      LAYER M5 ;
        RECT  10.32 0 10.344 0.192 ;
    END
  END i[53]
  PIN i[54]
    DIRECTION INPUT ;
    USE SIGNAL ;
    PORT
      LAYER M3 ;
        RECT  10.512 0 10.53 0.144 ;
    END
  END i[54]
  PIN i[55]
    DIRECTION INPUT ;
    USE SIGNAL ;
    PORT
      LAYER M5 ;
        RECT  10.656 0 10.68 0.192 ;
    END
  END i[55]
  PIN i[56]
    DIRECTION INPUT ;
    USE SIGNAL ;
    PORT
      LAYER M3 ;
        RECT  10.8 0 10.818 0.144 ;
    END
  END i[56]
  PIN i[57]
    DIRECTION INPUT ;
    USE SIGNAL ;
    PORT
      LAYER M5 ;
        RECT  10.944 0 10.968 0.192 ;
    END
  END i[57]
  PIN i[58]
    DIRECTION INPUT ;
    USE SIGNAL ;
    PORT
      LAYER M3 ;
        RECT  11.124 0 11.142 0.144 ;
    END
  END i[58]
  PIN i[59]
    DIRECTION INPUT ;
    USE SIGNAL ;
    PORT
      LAYER M5 ;
        RECT  11.28 0 11.304 0.192 ;
    END
  END i[59]
  PIN i[5]
    DIRECTION INPUT ;
    USE SIGNAL ;
    PORT
      LAYER M5 ;
        RECT  2.976 0 3 0.192 ;
    END
  END i[5]
  PIN i[60]
    DIRECTION INPUT ;
    USE SIGNAL ;
    PORT
      LAYER M3 ;
        RECT  11.412 0 11.43 0.144 ;
    END
  END i[60]
  PIN i[61]
    DIRECTION INPUT ;
    USE SIGNAL ;
    PORT
      LAYER M5 ;
        RECT  11.568 0 11.592 0.192 ;
    END
  END i[61]
  PIN i[62]
    DIRECTION INPUT ;
    USE SIGNAL ;
    PORT
      LAYER M3 ;
        RECT  11.736 0 11.754 0.144 ;
    END
  END i[62]
  PIN i[63]
    DIRECTION INPUT ;
    USE SIGNAL ;
    PORT
      LAYER M5 ;
        RECT  11.856 0 11.88 0.192 ;
    END
  END i[63]
  PIN i[64]
    DIRECTION INPUT ;
    USE SIGNAL ;
    PORT
      LAYER M3 ;
        RECT  12.024 0 12.042 0.144 ;
    END
  END i[64]
  PIN i[65]
    DIRECTION INPUT ;
    USE SIGNAL ;
    PORT
      LAYER M5 ;
        RECT  12.192 0 12.216 0.192 ;
    END
  END i[65]
  PIN i[66]
    DIRECTION INPUT ;
    USE SIGNAL ;
    PORT
      LAYER M3 ;
        RECT  12.348 0 12.366 0.144 ;
    END
  END i[66]
  PIN i[67]
    DIRECTION INPUT ;
    USE SIGNAL ;
    PORT
      LAYER M5 ;
        RECT  12.48 0 12.504 0.192 ;
    END
  END i[67]
  PIN i[68]
    DIRECTION INPUT ;
    USE SIGNAL ;
    PORT
      LAYER M3 ;
        RECT  12.636 0 12.654 0.144 ;
    END
  END i[68]
  PIN i[69]
    DIRECTION INPUT ;
    USE SIGNAL ;
    PORT
      LAYER M5 ;
        RECT  12.768 0 12.792 0.192 ;
    END
  END i[69]
  PIN i[6]
    DIRECTION INPUT ;
    USE SIGNAL ;
    PORT
      LAYER M3 ;
        RECT  3.132 0 3.15 0.144 ;
    END
  END i[6]
  PIN i[70]
    DIRECTION INPUT ;
    USE SIGNAL ;
    PORT
      LAYER M3 ;
        RECT  12.96 0 12.978 0.144 ;
    END
  END i[70]
  PIN i[71]
    DIRECTION INPUT ;
    USE SIGNAL ;
    PORT
      LAYER M5 ;
        RECT  13.104 0 13.128 0.192 ;
    END
  END i[71]
  PIN i[72]
    DIRECTION INPUT ;
    USE SIGNAL ;
    PORT
      LAYER M3 ;
        RECT  13.248 0 13.266 0.144 ;
    END
  END i[72]
  PIN i[73]
    DIRECTION INPUT ;
    USE SIGNAL ;
    PORT
      LAYER M5 ;
        RECT  13.392 0 13.416 0.192 ;
    END
  END i[73]
  PIN i[74]
    DIRECTION INPUT ;
    USE SIGNAL ;
    PORT
      LAYER M3 ;
        RECT  13.572 0 13.59 0.144 ;
    END
  END i[74]
  PIN i[75]
    DIRECTION INPUT ;
    USE SIGNAL ;
    PORT
      LAYER M5 ;
        RECT  13.728 0 13.752 0.192 ;
    END
  END i[75]
  PIN i[76]
    DIRECTION INPUT ;
    USE SIGNAL ;
    PORT
      LAYER M3 ;
        RECT  13.86 0 13.878 0.144 ;
    END
  END i[76]
  PIN i[77]
    DIRECTION INPUT ;
    USE SIGNAL ;
    PORT
      LAYER M5 ;
        RECT  14.016 0 14.04 0.192 ;
    END
  END i[77]
  PIN i[78]
    DIRECTION INPUT ;
    USE SIGNAL ;
    PORT
      LAYER M3 ;
        RECT  14.184 0 14.202 0.144 ;
    END
  END i[78]
  PIN i[79]
    DIRECTION INPUT ;
    USE SIGNAL ;
    PORT
      LAYER M5 ;
        RECT  14.304 0 14.328 0.192 ;
    END
  END i[79]
  PIN i[7]
    DIRECTION INPUT ;
    USE SIGNAL ;
    PORT
      LAYER M5 ;
        RECT  3.312 0 3.336 0.192 ;
    END
  END i[7]
  PIN i[80]
    DIRECTION INPUT ;
    USE SIGNAL ;
    PORT
      LAYER M3 ;
        RECT  14.472 0 14.49 0.144 ;
    END
  END i[80]
  PIN i[81]
    DIRECTION INPUT ;
    USE SIGNAL ;
    PORT
      LAYER M5 ;
        RECT  14.64 0 14.664 0.192 ;
    END
  END i[81]
  PIN i[82]
    DIRECTION INPUT ;
    USE SIGNAL ;
    PORT
      LAYER M3 ;
        RECT  14.796 0 14.814 0.144 ;
    END
  END i[82]
  PIN i[83]
    DIRECTION INPUT ;
    USE SIGNAL ;
    PORT
      LAYER M5 ;
        RECT  14.928 0 14.952 0.192 ;
    END
  END i[83]
  PIN i[84]
    DIRECTION INPUT ;
    USE SIGNAL ;
    PORT
      LAYER M3 ;
        RECT  15.084 0 15.102 0.144 ;
    END
  END i[84]
  PIN i[85]
    DIRECTION INPUT ;
    USE SIGNAL ;
    PORT
      LAYER M5 ;
        RECT  15.264 0 15.288 0.192 ;
    END
  END i[85]
  PIN i[86]
    DIRECTION INPUT ;
    USE SIGNAL ;
    PORT
      LAYER M3 ;
        RECT  15.408 0 15.426 0.144 ;
    END
  END i[86]
  PIN i[87]
    DIRECTION INPUT ;
    USE SIGNAL ;
    PORT
      LAYER M5 ;
        RECT  15.552 0 15.576 0.192 ;
    END
  END i[87]
  PIN i[88]
    DIRECTION INPUT ;
    USE SIGNAL ;
    PORT
      LAYER M3 ;
        RECT  15.696 0 15.714 0.144 ;
    END
  END i[88]
  PIN i[89]
    DIRECTION INPUT ;
    USE SIGNAL ;
    PORT
      LAYER M5 ;
        RECT  15.84 0 15.864 0.192 ;
    END
  END i[89]
  PIN i[8]
    DIRECTION INPUT ;
    USE SIGNAL ;
    PORT
      LAYER M3 ;
        RECT  3.456 0 3.474 0.144 ;
    END
  END i[8]
  PIN i[90]
    DIRECTION INPUT ;
    USE SIGNAL ;
    PORT
      LAYER M3 ;
        RECT  16.02 0 16.038 0.144 ;
    END
  END i[90]
  PIN i[91]
    DIRECTION INPUT ;
    USE SIGNAL ;
    PORT
      LAYER M5 ;
        RECT  16.176 0 16.2 0.192 ;
    END
  END i[91]
  PIN i[92]
    DIRECTION INPUT ;
    USE SIGNAL ;
    PORT
      LAYER M3 ;
        RECT  16.308 0 16.326 0.144 ;
    END
  END i[92]
  PIN i[93]
    DIRECTION INPUT ;
    USE SIGNAL ;
    PORT
      LAYER M5 ;
        RECT  16.464 0 16.488 0.192 ;
    END
  END i[93]
  PIN i[94]
    DIRECTION INPUT ;
    USE SIGNAL ;
    PORT
      LAYER M3 ;
        RECT  16.632 0 16.65 0.144 ;
    END
  END i[94]
  PIN i[95]
    DIRECTION INPUT ;
    USE SIGNAL ;
    PORT
      LAYER M5 ;
        RECT  16.752 0 16.776 0.192 ;
    END
  END i[95]
  PIN i[96]
    DIRECTION INPUT ;
    USE SIGNAL ;
    PORT
      LAYER M3 ;
        RECT  16.92 0 16.938 0.144 ;
    END
  END i[96]
  PIN i[97]
    DIRECTION INPUT ;
    USE SIGNAL ;
    PORT
      LAYER M5 ;
        RECT  17.088 0 17.112 0.192 ;
    END
  END i[97]
  PIN i[98]
    DIRECTION INPUT ;
    USE SIGNAL ;
    PORT
      LAYER M3 ;
        RECT  17.244 0 17.262 0.144 ;
    END
  END i[98]
  PIN i[99]
    DIRECTION INPUT ;
    USE SIGNAL ;
    PORT
      LAYER M5 ;
        RECT  17.376 0 17.4 0.192 ;
    END
  END i[99]
  PIN i[9]
    DIRECTION INPUT ;
    USE SIGNAL ;
    PORT
      LAYER M5 ;
        RECT  3.6 0 3.624 0.192 ;
    END
  END i[9]
  PIN o[0]
    DIRECTION OUTPUT ;
    USE SIGNAL ;
    PORT
      LAYER M3 ;
        RECT  2.232 25.776 2.25 25.92 ;
    END
  END o[0]
  PIN o[100]
    DIRECTION OUTPUT ;
    USE SIGNAL ;
    PORT
      LAYER M3 ;
        RECT  17.532 25.776 17.55 25.92 ;
    END
  END o[100]
  PIN o[101]
    DIRECTION OUTPUT ;
    USE SIGNAL ;
    PORT
      LAYER M5 ;
        RECT  17.712 25.728 17.736 25.92 ;
    END
  END o[101]
  PIN o[102]
    DIRECTION OUTPUT ;
    USE SIGNAL ;
    PORT
      LAYER M3 ;
        RECT  17.856 25.776 17.874 25.92 ;
    END
  END o[102]
  PIN o[103]
    DIRECTION OUTPUT ;
    USE SIGNAL ;
    PORT
      LAYER M5 ;
        RECT  18 25.728 18.024 25.92 ;
    END
  END o[103]
  PIN o[104]
    DIRECTION OUTPUT ;
    USE SIGNAL ;
    PORT
      LAYER M3 ;
        RECT  18.144 25.776 18.162 25.92 ;
    END
  END o[104]
  PIN o[105]
    DIRECTION OUTPUT ;
    USE SIGNAL ;
    PORT
      LAYER M5 ;
        RECT  18.288 25.728 18.312 25.92 ;
    END
  END o[105]
  PIN o[106]
    DIRECTION OUTPUT ;
    USE SIGNAL ;
    PORT
      LAYER M3 ;
        RECT  18.468 25.776 18.486 25.92 ;
    END
  END o[106]
  PIN o[107]
    DIRECTION OUTPUT ;
    USE SIGNAL ;
    PORT
      LAYER M5 ;
        RECT  18.624 25.728 18.648 25.92 ;
    END
  END o[107]
  PIN o[108]
    DIRECTION OUTPUT ;
    USE SIGNAL ;
    PORT
      LAYER M3 ;
        RECT  18.756 25.776 18.774 25.92 ;
    END
  END o[108]
  PIN o[109]
    DIRECTION OUTPUT ;
    USE SIGNAL ;
    PORT
      LAYER M5 ;
        RECT  18.912 25.728 18.936 25.92 ;
    END
  END o[109]
  PIN o[10]
    DIRECTION OUTPUT ;
    USE SIGNAL ;
    PORT
      LAYER M3 ;
        RECT  3.744 25.776 3.762 25.92 ;
    END
  END o[10]
  PIN o[110]
    DIRECTION OUTPUT ;
    USE SIGNAL ;
    PORT
      LAYER M3 ;
        RECT  19.08 25.776 19.098 25.92 ;
    END
  END o[110]
  PIN o[111]
    DIRECTION OUTPUT ;
    USE SIGNAL ;
    PORT
      LAYER M5 ;
        RECT  19.2 25.728 19.224 25.92 ;
    END
  END o[111]
  PIN o[112]
    DIRECTION OUTPUT ;
    USE SIGNAL ;
    PORT
      LAYER M3 ;
        RECT  19.368 25.776 19.386 25.92 ;
    END
  END o[112]
  PIN o[113]
    DIRECTION OUTPUT ;
    USE SIGNAL ;
    PORT
      LAYER M5 ;
        RECT  19.536 25.728 19.56 25.92 ;
    END
  END o[113]
  PIN o[114]
    DIRECTION OUTPUT ;
    USE SIGNAL ;
    PORT
      LAYER M3 ;
        RECT  19.692 25.776 19.71 25.92 ;
    END
  END o[114]
  PIN o[115]
    DIRECTION OUTPUT ;
    USE SIGNAL ;
    PORT
      LAYER M5 ;
        RECT  19.824 25.728 19.848 25.92 ;
    END
  END o[115]
  PIN o[116]
    DIRECTION OUTPUT ;
    USE SIGNAL ;
    PORT
      LAYER M3 ;
        RECT  19.98 25.776 19.998 25.92 ;
    END
  END o[116]
  PIN o[117]
    DIRECTION OUTPUT ;
    USE SIGNAL ;
    PORT
      LAYER M5 ;
        RECT  20.16 25.728 20.184 25.92 ;
    END
  END o[117]
  PIN o[118]
    DIRECTION OUTPUT ;
    USE SIGNAL ;
    PORT
      LAYER M3 ;
        RECT  20.304 25.776 20.322 25.92 ;
    END
  END o[118]
  PIN o[119]
    DIRECTION OUTPUT ;
    USE SIGNAL ;
    PORT
      LAYER M5 ;
        RECT  20.448 25.728 20.472 25.92 ;
    END
  END o[119]
  PIN o[11]
    DIRECTION OUTPUT ;
    USE SIGNAL ;
    PORT
      LAYER M5 ;
        RECT  3.888 25.728 3.912 25.92 ;
    END
  END o[11]
  PIN o[120]
    DIRECTION OUTPUT ;
    USE SIGNAL ;
    PORT
      LAYER M3 ;
        RECT  20.592 25.776 20.61 25.92 ;
    END
  END o[120]
  PIN o[121]
    DIRECTION OUTPUT ;
    USE SIGNAL ;
    PORT
      LAYER M5 ;
        RECT  20.736 25.728 20.76 25.92 ;
    END
  END o[121]
  PIN o[122]
    DIRECTION OUTPUT ;
    USE SIGNAL ;
    PORT
      LAYER M3 ;
        RECT  20.916 25.776 20.934 25.92 ;
    END
  END o[122]
  PIN o[123]
    DIRECTION OUTPUT ;
    USE SIGNAL ;
    PORT
      LAYER M5 ;
        RECT  21.072 25.728 21.096 25.92 ;
    END
  END o[123]
  PIN o[124]
    DIRECTION OUTPUT ;
    USE SIGNAL ;
    PORT
      LAYER M3 ;
        RECT  21.204 25.776 21.222 25.92 ;
    END
  END o[124]
  PIN o[125]
    DIRECTION OUTPUT ;
    USE SIGNAL ;
    PORT
      LAYER M5 ;
        RECT  21.36 25.728 21.384 25.92 ;
    END
  END o[125]
  PIN o[126]
    DIRECTION OUTPUT ;
    USE SIGNAL ;
    PORT
      LAYER M3 ;
        RECT  21.528 25.776 21.546 25.92 ;
    END
  END o[126]
  PIN o[127]
    DIRECTION OUTPUT ;
    USE SIGNAL ;
    PORT
      LAYER M5 ;
        RECT  21.696 25.728 21.72 25.92 ;
    END
  END o[127]
  PIN o[128]
    DIRECTION OUTPUT ;
    USE SIGNAL ;
    PORT
      LAYER M3 ;
        RECT  21.816 25.776 21.834 25.92 ;
    END
  END o[128]
  PIN o[129]
    DIRECTION OUTPUT ;
    USE SIGNAL ;
    PORT
      LAYER M5 ;
        RECT  21.984 25.728 22.008 25.92 ;
    END
  END o[129]
  PIN o[12]
    DIRECTION OUTPUT ;
    USE SIGNAL ;
    PORT
      LAYER M3 ;
        RECT  4.068 25.776 4.086 25.92 ;
    END
  END o[12]
  PIN o[130]
    DIRECTION OUTPUT ;
    USE SIGNAL ;
    PORT
      LAYER M3 ;
        RECT  22.14 25.776 22.158 25.92 ;
    END
  END o[130]
  PIN o[131]
    DIRECTION OUTPUT ;
    USE SIGNAL ;
    PORT
      LAYER M5 ;
        RECT  22.272 25.728 22.296 25.92 ;
    END
  END o[131]
  PIN o[132]
    DIRECTION OUTPUT ;
    USE SIGNAL ;
    PORT
      LAYER M3 ;
        RECT  22.428 25.776 22.446 25.92 ;
    END
  END o[132]
  PIN o[133]
    DIRECTION OUTPUT ;
    USE SIGNAL ;
    PORT
      LAYER M5 ;
        RECT  22.608 25.728 22.632 25.92 ;
    END
  END o[133]
  PIN o[134]
    DIRECTION OUTPUT ;
    USE SIGNAL ;
    PORT
      LAYER M3 ;
        RECT  22.752 25.776 22.77 25.92 ;
    END
  END o[134]
  PIN o[135]
    DIRECTION OUTPUT ;
    USE SIGNAL ;
    PORT
      LAYER M5 ;
        RECT  22.896 25.728 22.92 25.92 ;
    END
  END o[135]
  PIN o[136]
    DIRECTION OUTPUT ;
    USE SIGNAL ;
    PORT
      LAYER M3 ;
        RECT  23.04 25.776 23.058 25.92 ;
    END
  END o[136]
  PIN o[137]
    DIRECTION OUTPUT ;
    USE SIGNAL ;
    PORT
      LAYER M5 ;
        RECT  23.184 25.728 23.208 25.92 ;
    END
  END o[137]
  PIN o[138]
    DIRECTION OUTPUT ;
    USE SIGNAL ;
    PORT
      LAYER M3 ;
        RECT  23.364 25.776 23.382 25.92 ;
    END
  END o[138]
  PIN o[139]
    DIRECTION OUTPUT ;
    USE SIGNAL ;
    PORT
      LAYER M5 ;
        RECT  23.52 25.728 23.544 25.92 ;
    END
  END o[139]
  PIN o[13]
    DIRECTION OUTPUT ;
    USE SIGNAL ;
    PORT
      LAYER M5 ;
        RECT  4.224 25.728 4.248 25.92 ;
    END
  END o[13]
  PIN o[140]
    DIRECTION OUTPUT ;
    USE SIGNAL ;
    PORT
      LAYER M3 ;
        RECT  23.652 25.776 23.67 25.92 ;
    END
  END o[140]
  PIN o[141]
    DIRECTION OUTPUT ;
    USE SIGNAL ;
    PORT
      LAYER M5 ;
        RECT  23.808 25.728 23.832 25.92 ;
    END
  END o[141]
  PIN o[142]
    DIRECTION OUTPUT ;
    USE SIGNAL ;
    PORT
      LAYER M3 ;
        RECT  23.976 25.776 23.994 25.92 ;
    END
  END o[142]
  PIN o[143]
    DIRECTION OUTPUT ;
    USE SIGNAL ;
    PORT
      LAYER M5 ;
        RECT  24.144 25.728 24.168 25.92 ;
    END
  END o[143]
  PIN o[144]
    DIRECTION OUTPUT ;
    USE SIGNAL ;
    PORT
      LAYER M3 ;
        RECT  24.264 25.776 24.282 25.92 ;
    END
  END o[144]
  PIN o[145]
    DIRECTION OUTPUT ;
    USE SIGNAL ;
    PORT
      LAYER M5 ;
        RECT  24.432 25.728 24.456 25.92 ;
    END
  END o[145]
  PIN o[146]
    DIRECTION OUTPUT ;
    USE SIGNAL ;
    PORT
      LAYER M3 ;
        RECT  24.588 25.776 24.606 25.92 ;
    END
  END o[146]
  PIN o[147]
    DIRECTION OUTPUT ;
    USE SIGNAL ;
    PORT
      LAYER M5 ;
        RECT  24.72 25.728 24.744 25.92 ;
    END
  END o[147]
  PIN o[148]
    DIRECTION OUTPUT ;
    USE SIGNAL ;
    PORT
      LAYER M3 ;
        RECT  24.876 25.776 24.894 25.92 ;
    END
  END o[148]
  PIN o[149]
    DIRECTION OUTPUT ;
    USE SIGNAL ;
    PORT
      LAYER M5 ;
        RECT  25.056 25.728 25.08 25.92 ;
    END
  END o[149]
  PIN o[14]
    DIRECTION OUTPUT ;
    USE SIGNAL ;
    PORT
      LAYER M3 ;
        RECT  4.356 25.776 4.374 25.92 ;
    END
  END o[14]
  PIN o[150]
    DIRECTION OUTPUT ;
    USE SIGNAL ;
    PORT
      LAYER M3 ;
        RECT  25.2 25.776 25.218 25.92 ;
    END
  END o[150]
  PIN o[151]
    DIRECTION OUTPUT ;
    USE SIGNAL ;
    PORT
      LAYER M5 ;
        RECT  25.344 25.728 25.368 25.92 ;
    END
  END o[151]
  PIN o[152]
    DIRECTION OUTPUT ;
    USE SIGNAL ;
    PORT
      LAYER M3 ;
        RECT  25.488 25.776 25.506 25.92 ;
    END
  END o[152]
  PIN o[153]
    DIRECTION OUTPUT ;
    USE SIGNAL ;
    PORT
      LAYER M5 ;
        RECT  25.632 25.728 25.656 25.92 ;
    END
  END o[153]
  PIN o[154]
    DIRECTION OUTPUT ;
    USE SIGNAL ;
    PORT
      LAYER M3 ;
        RECT  25.812 25.776 25.83 25.92 ;
    END
  END o[154]
  PIN o[155]
    DIRECTION OUTPUT ;
    USE SIGNAL ;
    PORT
      LAYER M5 ;
        RECT  25.968 25.728 25.992 25.92 ;
    END
  END o[155]
  PIN o[156]
    DIRECTION OUTPUT ;
    USE SIGNAL ;
    PORT
      LAYER M3 ;
        RECT  26.1 25.776 26.118 25.92 ;
    END
  END o[156]
  PIN o[157]
    DIRECTION OUTPUT ;
    USE SIGNAL ;
    PORT
      LAYER M5 ;
        RECT  26.256 25.728 26.28 25.92 ;
    END
  END o[157]
  PIN o[158]
    DIRECTION OUTPUT ;
    USE SIGNAL ;
    PORT
      LAYER M3 ;
        RECT  26.424 25.776 26.442 25.92 ;
    END
  END o[158]
  PIN o[159]
    DIRECTION OUTPUT ;
    USE SIGNAL ;
    PORT
      LAYER M5 ;
        RECT  26.592 25.728 26.616 25.92 ;
    END
  END o[159]
  PIN o[15]
    DIRECTION OUTPUT ;
    USE SIGNAL ;
    PORT
      LAYER M5 ;
        RECT  4.512 25.728 4.536 25.92 ;
    END
  END o[15]
  PIN o[160]
    DIRECTION OUTPUT ;
    USE SIGNAL ;
    PORT
      LAYER M3 ;
        RECT  26.712 25.776 26.73 25.92 ;
    END
  END o[160]
  PIN o[161]
    DIRECTION OUTPUT ;
    USE SIGNAL ;
    PORT
      LAYER M5 ;
        RECT  26.88 25.728 26.904 25.92 ;
    END
  END o[161]
  PIN o[162]
    DIRECTION OUTPUT ;
    USE SIGNAL ;
    PORT
      LAYER M3 ;
        RECT  27.036 25.776 27.054 25.92 ;
    END
  END o[162]
  PIN o[163]
    DIRECTION OUTPUT ;
    USE SIGNAL ;
    PORT
      LAYER M5 ;
        RECT  27.168 25.728 27.192 25.92 ;
    END
  END o[163]
  PIN o[164]
    DIRECTION OUTPUT ;
    USE SIGNAL ;
    PORT
      LAYER M3 ;
        RECT  27.324 25.776 27.342 25.92 ;
    END
  END o[164]
  PIN o[165]
    DIRECTION OUTPUT ;
    USE SIGNAL ;
    PORT
      LAYER M5 ;
        RECT  27.504 25.728 27.528 25.92 ;
    END
  END o[165]
  PIN o[166]
    DIRECTION OUTPUT ;
    USE SIGNAL ;
    PORT
      LAYER M3 ;
        RECT  27.648 25.776 27.666 25.92 ;
    END
  END o[166]
  PIN o[167]
    DIRECTION OUTPUT ;
    USE SIGNAL ;
    PORT
      LAYER M5 ;
        RECT  27.792 25.728 27.816 25.92 ;
    END
  END o[167]
  PIN o[168]
    DIRECTION OUTPUT ;
    USE SIGNAL ;
    PORT
      LAYER M3 ;
        RECT  27.972 25.776 27.99 25.92 ;
    END
  END o[168]
  PIN o[169]
    DIRECTION OUTPUT ;
    USE SIGNAL ;
    PORT
      LAYER M5 ;
        RECT  28.128 25.728 28.152 25.92 ;
    END
  END o[169]
  PIN o[16]
    DIRECTION OUTPUT ;
    USE SIGNAL ;
    PORT
      LAYER M3 ;
        RECT  4.68 25.776 4.698 25.92 ;
    END
  END o[16]
  PIN o[170]
    DIRECTION OUTPUT ;
    USE SIGNAL ;
    PORT
      LAYER M3 ;
        RECT  28.26 25.776 28.278 25.92 ;
    END
  END o[170]
  PIN o[171]
    DIRECTION OUTPUT ;
    USE SIGNAL ;
    PORT
      LAYER M5 ;
        RECT  28.416 25.728 28.44 25.92 ;
    END
  END o[171]
  PIN o[172]
    DIRECTION OUTPUT ;
    USE SIGNAL ;
    PORT
      LAYER M3 ;
        RECT  28.584 25.776 28.602 25.92 ;
    END
  END o[172]
  PIN o[173]
    DIRECTION OUTPUT ;
    USE SIGNAL ;
    PORT
      LAYER M5 ;
        RECT  28.704 25.728 28.728 25.92 ;
    END
  END o[173]
  PIN o[174]
    DIRECTION OUTPUT ;
    USE SIGNAL ;
    PORT
      LAYER M3 ;
        RECT  28.872 25.776 28.89 25.92 ;
    END
  END o[174]
  PIN o[175]
    DIRECTION OUTPUT ;
    USE SIGNAL ;
    PORT
      LAYER M5 ;
        RECT  29.04 25.728 29.064 25.92 ;
    END
  END o[175]
  PIN o[176]
    DIRECTION OUTPUT ;
    USE SIGNAL ;
    PORT
      LAYER M3 ;
        RECT  29.196 25.776 29.214 25.92 ;
    END
  END o[176]
  PIN o[177]
    DIRECTION OUTPUT ;
    USE SIGNAL ;
    PORT
      LAYER M5 ;
        RECT  29.328 25.728 29.352 25.92 ;
    END
  END o[177]
  PIN o[178]
    DIRECTION OUTPUT ;
    USE SIGNAL ;
    PORT
      LAYER M3 ;
        RECT  29.484 25.776 29.502 25.92 ;
    END
  END o[178]
  PIN o[179]
    DIRECTION OUTPUT ;
    USE SIGNAL ;
    PORT
      LAYER M5 ;
        RECT  29.616 25.728 29.64 25.92 ;
    END
  END o[179]
  PIN o[17]
    DIRECTION OUTPUT ;
    USE SIGNAL ;
    PORT
      LAYER M5 ;
        RECT  4.848 25.728 4.872 25.92 ;
    END
  END o[17]
  PIN o[180]
    DIRECTION OUTPUT ;
    USE SIGNAL ;
    PORT
      LAYER M3 ;
        RECT  29.808 25.776 29.826 25.92 ;
    END
  END o[180]
  PIN o[181]
    DIRECTION OUTPUT ;
    USE SIGNAL ;
    PORT
      LAYER M5 ;
        RECT  29.952 25.728 29.976 25.92 ;
    END
  END o[181]
  PIN o[182]
    DIRECTION OUTPUT ;
    USE SIGNAL ;
    PORT
      LAYER M3 ;
        RECT  30.096 25.776 30.114 25.92 ;
    END
  END o[182]
  PIN o[183]
    DIRECTION OUTPUT ;
    USE SIGNAL ;
    PORT
      LAYER M5 ;
        RECT  30.24 25.728 30.264 25.92 ;
    END
  END o[183]
  PIN o[184]
    DIRECTION OUTPUT ;
    USE SIGNAL ;
    PORT
      LAYER M3 ;
        RECT  30.42 25.776 30.438 25.92 ;
    END
  END o[184]
  PIN o[185]
    DIRECTION OUTPUT ;
    USE SIGNAL ;
    PORT
      LAYER M5 ;
        RECT  30.576 25.728 30.6 25.92 ;
    END
  END o[185]
  PIN o[186]
    DIRECTION OUTPUT ;
    USE SIGNAL ;
    PORT
      LAYER M3 ;
        RECT  30.708 25.776 30.726 25.92 ;
    END
  END o[186]
  PIN o[187]
    DIRECTION OUTPUT ;
    USE SIGNAL ;
    PORT
      LAYER M5 ;
        RECT  30.864 25.728 30.888 25.92 ;
    END
  END o[187]
  PIN o[188]
    DIRECTION OUTPUT ;
    USE SIGNAL ;
    PORT
      LAYER M3 ;
        RECT  31.032 25.776 31.05 25.92 ;
    END
  END o[188]
  PIN o[189]
    DIRECTION OUTPUT ;
    USE SIGNAL ;
    PORT
      LAYER M5 ;
        RECT  31.152 25.728 31.176 25.92 ;
    END
  END o[189]
  PIN o[18]
    DIRECTION OUTPUT ;
    USE SIGNAL ;
    PORT
      LAYER M3 ;
        RECT  4.968 25.776 4.986 25.92 ;
    END
  END o[18]
  PIN o[190]
    DIRECTION OUTPUT ;
    USE SIGNAL ;
    PORT
      LAYER M3 ;
        RECT  31.32 25.776 31.338 25.92 ;
    END
  END o[190]
  PIN o[191]
    DIRECTION OUTPUT ;
    USE SIGNAL ;
    PORT
      LAYER M5 ;
        RECT  31.488 25.728 31.512 25.92 ;
    END
  END o[191]
  PIN o[192]
    DIRECTION OUTPUT ;
    USE SIGNAL ;
    PORT
      LAYER M3 ;
        RECT  31.644 25.776 31.662 25.92 ;
    END
  END o[192]
  PIN o[193]
    DIRECTION OUTPUT ;
    USE SIGNAL ;
    PORT
      LAYER M5 ;
        RECT  31.776 25.728 31.8 25.92 ;
    END
  END o[193]
  PIN o[194]
    DIRECTION OUTPUT ;
    USE SIGNAL ;
    PORT
      LAYER M3 ;
        RECT  31.932 25.776 31.95 25.92 ;
    END
  END o[194]
  PIN o[195]
    DIRECTION OUTPUT ;
    USE SIGNAL ;
    PORT
      LAYER M5 ;
        RECT  32.064 25.728 32.088 25.92 ;
    END
  END o[195]
  PIN o[196]
    DIRECTION OUTPUT ;
    USE SIGNAL ;
    PORT
      LAYER M3 ;
        RECT  32.256 25.776 32.274 25.92 ;
    END
  END o[196]
  PIN o[197]
    DIRECTION OUTPUT ;
    USE SIGNAL ;
    PORT
      LAYER M5 ;
        RECT  32.4 25.728 32.424 25.92 ;
    END
  END o[197]
  PIN o[198]
    DIRECTION OUTPUT ;
    USE SIGNAL ;
    PORT
      LAYER M3 ;
        RECT  32.544 25.776 32.562 25.92 ;
    END
  END o[198]
  PIN o[199]
    DIRECTION OUTPUT ;
    USE SIGNAL ;
    PORT
      LAYER M5 ;
        RECT  32.688 25.728 32.712 25.92 ;
    END
  END o[199]
  PIN o[19]
    DIRECTION OUTPUT ;
    USE SIGNAL ;
    PORT
      LAYER M5 ;
        RECT  5.136 25.728 5.16 25.92 ;
    END
  END o[19]
  PIN o[1]
    DIRECTION OUTPUT ;
    USE SIGNAL ;
    PORT
      LAYER M5 ;
        RECT  2.4 25.728 2.424 25.92 ;
    END
  END o[1]
  PIN o[200]
    DIRECTION OUTPUT ;
    USE SIGNAL ;
    PORT
      LAYER M3 ;
        RECT  32.868 25.776 32.886 25.92 ;
    END
  END o[200]
  PIN o[201]
    DIRECTION OUTPUT ;
    USE SIGNAL ;
    PORT
      LAYER M5 ;
        RECT  33.024 25.728 33.048 25.92 ;
    END
  END o[201]
  PIN o[202]
    DIRECTION OUTPUT ;
    USE SIGNAL ;
    PORT
      LAYER M3 ;
        RECT  33.156 25.776 33.174 25.92 ;
    END
  END o[202]
  PIN o[203]
    DIRECTION OUTPUT ;
    USE SIGNAL ;
    PORT
      LAYER M5 ;
        RECT  33.312 25.728 33.336 25.92 ;
    END
  END o[203]
  PIN o[204]
    DIRECTION OUTPUT ;
    USE SIGNAL ;
    PORT
      LAYER M3 ;
        RECT  33.48 25.776 33.498 25.92 ;
    END
  END o[204]
  PIN o[205]
    DIRECTION OUTPUT ;
    USE SIGNAL ;
    PORT
      LAYER M5 ;
        RECT  33.6 25.728 33.624 25.92 ;
    END
  END o[205]
  PIN o[206]
    DIRECTION OUTPUT ;
    USE SIGNAL ;
    PORT
      LAYER M3 ;
        RECT  33.768 25.776 33.786 25.92 ;
    END
  END o[206]
  PIN o[207]
    DIRECTION OUTPUT ;
    USE SIGNAL ;
    PORT
      LAYER M5 ;
        RECT  33.936 25.728 33.96 25.92 ;
    END
  END o[207]
  PIN o[208]
    DIRECTION OUTPUT ;
    USE SIGNAL ;
    PORT
      LAYER M3 ;
        RECT  34.092 25.776 34.11 25.92 ;
    END
  END o[208]
  PIN o[209]
    DIRECTION OUTPUT ;
    USE SIGNAL ;
    PORT
      LAYER M5 ;
        RECT  34.224 25.728 34.248 25.92 ;
    END
  END o[209]
  PIN o[20]
    DIRECTION OUTPUT ;
    USE SIGNAL ;
    PORT
      LAYER M3 ;
        RECT  5.292 25.776 5.31 25.92 ;
    END
  END o[20]
  PIN o[210]
    DIRECTION OUTPUT ;
    USE SIGNAL ;
    PORT
      LAYER M3 ;
        RECT  34.38 25.776 34.398 25.92 ;
    END
  END o[210]
  PIN o[211]
    DIRECTION OUTPUT ;
    USE SIGNAL ;
    PORT
      LAYER M5 ;
        RECT  34.512 25.728 34.536 25.92 ;
    END
  END o[211]
  PIN o[212]
    DIRECTION OUTPUT ;
    USE SIGNAL ;
    PORT
      LAYER M3 ;
        RECT  34.704 25.776 34.722 25.92 ;
    END
  END o[212]
  PIN o[213]
    DIRECTION OUTPUT ;
    USE SIGNAL ;
    PORT
      LAYER M5 ;
        RECT  34.848 25.728 34.872 25.92 ;
    END
  END o[213]
  PIN o[214]
    DIRECTION OUTPUT ;
    USE SIGNAL ;
    PORT
      LAYER M3 ;
        RECT  34.992 25.776 35.01 25.92 ;
    END
  END o[214]
  PIN o[215]
    DIRECTION OUTPUT ;
    USE SIGNAL ;
    PORT
      LAYER M5 ;
        RECT  35.136 25.728 35.16 25.92 ;
    END
  END o[215]
  PIN o[216]
    DIRECTION OUTPUT ;
    USE SIGNAL ;
    PORT
      LAYER M3 ;
        RECT  35.316 25.776 35.334 25.92 ;
    END
  END o[216]
  PIN o[217]
    DIRECTION OUTPUT ;
    USE SIGNAL ;
    PORT
      LAYER M5 ;
        RECT  35.472 25.728 35.496 25.92 ;
    END
  END o[217]
  PIN o[218]
    DIRECTION OUTPUT ;
    USE SIGNAL ;
    PORT
      LAYER M3 ;
        RECT  35.604 25.776 35.622 25.92 ;
    END
  END o[218]
  PIN o[219]
    DIRECTION OUTPUT ;
    USE SIGNAL ;
    PORT
      LAYER M5 ;
        RECT  35.76 25.728 35.784 25.92 ;
    END
  END o[219]
  PIN o[21]
    DIRECTION OUTPUT ;
    USE SIGNAL ;
    PORT
      LAYER M5 ;
        RECT  5.424 25.728 5.448 25.92 ;
    END
  END o[21]
  PIN o[220]
    DIRECTION OUTPUT ;
    USE SIGNAL ;
    PORT
      LAYER M3 ;
        RECT  35.928 25.776 35.946 25.92 ;
    END
  END o[220]
  PIN o[221]
    DIRECTION OUTPUT ;
    USE SIGNAL ;
    PORT
      LAYER M5 ;
        RECT  36.048 25.728 36.072 25.92 ;
    END
  END o[221]
  PIN o[222]
    DIRECTION OUTPUT ;
    USE SIGNAL ;
    PORT
      LAYER M3 ;
        RECT  36.216 25.776 36.234 25.92 ;
    END
  END o[222]
  PIN o[223]
    DIRECTION OUTPUT ;
    USE SIGNAL ;
    PORT
      LAYER M5 ;
        RECT  36.384 25.728 36.408 25.92 ;
    END
  END o[223]
  PIN o[224]
    DIRECTION OUTPUT ;
    USE SIGNAL ;
    PORT
      LAYER M3 ;
        RECT  36.54 25.776 36.558 25.92 ;
    END
  END o[224]
  PIN o[225]
    DIRECTION OUTPUT ;
    USE SIGNAL ;
    PORT
      LAYER M5 ;
        RECT  36.672 25.728 36.696 25.92 ;
    END
  END o[225]
  PIN o[226]
    DIRECTION OUTPUT ;
    USE SIGNAL ;
    PORT
      LAYER M3 ;
        RECT  36.828 25.776 36.846 25.92 ;
    END
  END o[226]
  PIN o[227]
    DIRECTION OUTPUT ;
    USE SIGNAL ;
    PORT
      LAYER M5 ;
        RECT  37.008 25.728 37.032 25.92 ;
    END
  END o[227]
  PIN o[228]
    DIRECTION OUTPUT ;
    USE SIGNAL ;
    PORT
      LAYER M3 ;
        RECT  37.152 25.776 37.17 25.92 ;
    END
  END o[228]
  PIN o[229]
    DIRECTION OUTPUT ;
    USE SIGNAL ;
    PORT
      LAYER M5 ;
        RECT  37.296 25.728 37.32 25.92 ;
    END
  END o[229]
  PIN o[22]
    DIRECTION OUTPUT ;
    USE SIGNAL ;
    PORT
      LAYER M3 ;
        RECT  5.58 25.776 5.598 25.92 ;
    END
  END o[22]
  PIN o[230]
    DIRECTION OUTPUT ;
    USE SIGNAL ;
    PORT
      LAYER M3 ;
        RECT  37.44 25.776 37.458 25.92 ;
    END
  END o[230]
  PIN o[231]
    DIRECTION OUTPUT ;
    USE SIGNAL ;
    PORT
      LAYER M5 ;
        RECT  37.584 25.728 37.608 25.92 ;
    END
  END o[231]
  PIN o[232]
    DIRECTION OUTPUT ;
    USE SIGNAL ;
    PORT
      LAYER M3 ;
        RECT  37.764 25.776 37.782 25.92 ;
    END
  END o[232]
  PIN o[233]
    DIRECTION OUTPUT ;
    USE SIGNAL ;
    PORT
      LAYER M5 ;
        RECT  37.92 25.728 37.944 25.92 ;
    END
  END o[233]
  PIN o[234]
    DIRECTION OUTPUT ;
    USE SIGNAL ;
    PORT
      LAYER M3 ;
        RECT  38.052 25.776 38.07 25.92 ;
    END
  END o[234]
  PIN o[235]
    DIRECTION OUTPUT ;
    USE SIGNAL ;
    PORT
      LAYER M5 ;
        RECT  38.208 25.728 38.232 25.92 ;
    END
  END o[235]
  PIN o[236]
    DIRECTION OUTPUT ;
    USE SIGNAL ;
    PORT
      LAYER M3 ;
        RECT  38.376 25.776 38.394 25.92 ;
    END
  END o[236]
  PIN o[237]
    DIRECTION OUTPUT ;
    USE SIGNAL ;
    PORT
      LAYER M5 ;
        RECT  38.496 25.728 38.52 25.92 ;
    END
  END o[237]
  PIN o[238]
    DIRECTION OUTPUT ;
    USE SIGNAL ;
    PORT
      LAYER M3 ;
        RECT  38.664 25.776 38.682 25.92 ;
    END
  END o[238]
  PIN o[239]
    DIRECTION OUTPUT ;
    USE SIGNAL ;
    PORT
      LAYER M5 ;
        RECT  38.832 25.728 38.856 25.92 ;
    END
  END o[239]
  PIN o[23]
    DIRECTION OUTPUT ;
    USE SIGNAL ;
    PORT
      LAYER M5 ;
        RECT  5.76 25.728 5.784 25.92 ;
    END
  END o[23]
  PIN o[240]
    DIRECTION OUTPUT ;
    USE SIGNAL ;
    PORT
      LAYER M3 ;
        RECT  38.988 25.776 39.006 25.92 ;
    END
  END o[240]
  PIN o[241]
    DIRECTION OUTPUT ;
    USE SIGNAL ;
    PORT
      LAYER M5 ;
        RECT  39.12 25.728 39.144 25.92 ;
    END
  END o[241]
  PIN o[242]
    DIRECTION OUTPUT ;
    USE SIGNAL ;
    PORT
      LAYER M3 ;
        RECT  39.276 25.776 39.294 25.92 ;
    END
  END o[242]
  PIN o[243]
    DIRECTION OUTPUT ;
    USE SIGNAL ;
    PORT
      LAYER M5 ;
        RECT  39.456 25.728 39.48 25.92 ;
    END
  END o[243]
  PIN o[244]
    DIRECTION OUTPUT ;
    USE SIGNAL ;
    PORT
      LAYER M3 ;
        RECT  39.6 25.776 39.618 25.92 ;
    END
  END o[244]
  PIN o[245]
    DIRECTION OUTPUT ;
    USE SIGNAL ;
    PORT
      LAYER M5 ;
        RECT  39.744 25.728 39.768 25.92 ;
    END
  END o[245]
  PIN o[246]
    DIRECTION OUTPUT ;
    USE SIGNAL ;
    PORT
      LAYER M3 ;
        RECT  39.888 25.776 39.906 25.92 ;
    END
  END o[246]
  PIN o[247]
    DIRECTION OUTPUT ;
    USE SIGNAL ;
    PORT
      LAYER M5 ;
        RECT  40.032 25.728 40.056 25.92 ;
    END
  END o[247]
  PIN o[248]
    DIRECTION OUTPUT ;
    USE SIGNAL ;
    PORT
      LAYER M3 ;
        RECT  40.212 25.776 40.23 25.92 ;
    END
  END o[248]
  PIN o[249]
    DIRECTION OUTPUT ;
    USE SIGNAL ;
    PORT
      LAYER M5 ;
        RECT  40.368 25.728 40.392 25.92 ;
    END
  END o[249]
  PIN o[24]
    DIRECTION OUTPUT ;
    USE SIGNAL ;
    PORT
      LAYER M3 ;
        RECT  5.904 25.776 5.922 25.92 ;
    END
  END o[24]
  PIN o[250]
    DIRECTION OUTPUT ;
    USE SIGNAL ;
    PORT
      LAYER M3 ;
        RECT  40.5 25.776 40.518 25.92 ;
    END
  END o[250]
  PIN o[251]
    DIRECTION OUTPUT ;
    USE SIGNAL ;
    PORT
      LAYER M5 ;
        RECT  40.656 25.728 40.68 25.92 ;
    END
  END o[251]
  PIN o[252]
    DIRECTION OUTPUT ;
    USE SIGNAL ;
    PORT
      LAYER M3 ;
        RECT  40.824 25.776 40.842 25.92 ;
    END
  END o[252]
  PIN o[253]
    DIRECTION OUTPUT ;
    USE SIGNAL ;
    PORT
      LAYER M5 ;
        RECT  40.944 25.728 40.968 25.92 ;
    END
  END o[253]
  PIN o[254]
    DIRECTION OUTPUT ;
    USE SIGNAL ;
    PORT
      LAYER M3 ;
        RECT  41.112 25.776 41.13 25.92 ;
    END
  END o[254]
  PIN o[255]
    DIRECTION OUTPUT ;
    USE SIGNAL ;
    PORT
      LAYER M5 ;
        RECT  41.28 25.728 41.304 25.92 ;
    END
  END o[255]
  PIN o[256]
    DIRECTION OUTPUT ;
    USE SIGNAL ;
    PORT
      LAYER M3 ;
        RECT  41.436 25.776 41.454 25.92 ;
    END
  END o[256]
  PIN o[257]
    DIRECTION OUTPUT ;
    USE SIGNAL ;
    PORT
      LAYER M5 ;
        RECT  41.568 25.728 41.592 25.92 ;
    END
  END o[257]
  PIN o[258]
    DIRECTION OUTPUT ;
    USE SIGNAL ;
    PORT
      LAYER M3 ;
        RECT  41.724 25.776 41.742 25.92 ;
    END
  END o[258]
  PIN o[259]
    DIRECTION OUTPUT ;
    USE SIGNAL ;
    PORT
      LAYER M5 ;
        RECT  41.904 25.728 41.928 25.92 ;
    END
  END o[259]
  PIN o[25]
    DIRECTION OUTPUT ;
    USE SIGNAL ;
    PORT
      LAYER M5 ;
        RECT  6.048 25.728 6.072 25.92 ;
    END
  END o[25]
  PIN o[260]
    DIRECTION OUTPUT ;
    USE SIGNAL ;
    PORT
      LAYER M3 ;
        RECT  42.048 25.776 42.066 25.92 ;
    END
  END o[260]
  PIN o[261]
    DIRECTION OUTPUT ;
    USE SIGNAL ;
    PORT
      LAYER M5 ;
        RECT  42.192 25.728 42.216 25.92 ;
    END
  END o[261]
  PIN o[262]
    DIRECTION OUTPUT ;
    USE SIGNAL ;
    PORT
      LAYER M3 ;
        RECT  42.336 25.776 42.354 25.92 ;
    END
  END o[262]
  PIN o[263]
    DIRECTION OUTPUT ;
    USE SIGNAL ;
    PORT
      LAYER M5 ;
        RECT  42.48 25.728 42.504 25.92 ;
    END
  END o[263]
  PIN o[264]
    DIRECTION OUTPUT ;
    USE SIGNAL ;
    PORT
      LAYER M3 ;
        RECT  42.66 25.776 42.678 25.92 ;
    END
  END o[264]
  PIN o[265]
    DIRECTION OUTPUT ;
    USE SIGNAL ;
    PORT
      LAYER M5 ;
        RECT  42.816 25.728 42.84 25.92 ;
    END
  END o[265]
  PIN o[266]
    DIRECTION OUTPUT ;
    USE SIGNAL ;
    PORT
      LAYER M3 ;
        RECT  42.948 25.776 42.966 25.92 ;
    END
  END o[266]
  PIN o[267]
    DIRECTION OUTPUT ;
    USE SIGNAL ;
    PORT
      LAYER M5 ;
        RECT  43.104 25.728 43.128 25.92 ;
    END
  END o[267]
  PIN o[268]
    DIRECTION OUTPUT ;
    USE SIGNAL ;
    PORT
      LAYER M3 ;
        RECT  43.272 25.776 43.29 25.92 ;
    END
  END o[268]
  PIN o[269]
    DIRECTION OUTPUT ;
    USE SIGNAL ;
    PORT
      LAYER M5 ;
        RECT  43.44 25.728 43.464 25.92 ;
    END
  END o[269]
  PIN o[26]
    DIRECTION OUTPUT ;
    USE SIGNAL ;
    PORT
      LAYER M3 ;
        RECT  6.192 25.776 6.21 25.92 ;
    END
  END o[26]
  PIN o[270]
    DIRECTION OUTPUT ;
    USE SIGNAL ;
    PORT
      LAYER M3 ;
        RECT  43.56 25.776 43.578 25.92 ;
    END
  END o[270]
  PIN o[271]
    DIRECTION OUTPUT ;
    USE SIGNAL ;
    PORT
      LAYER M5 ;
        RECT  43.728 25.728 43.752 25.92 ;
    END
  END o[271]
  PIN o[272]
    DIRECTION OUTPUT ;
    USE SIGNAL ;
    PORT
      LAYER M3 ;
        RECT  43.884 25.776 43.902 25.92 ;
    END
  END o[272]
  PIN o[273]
    DIRECTION OUTPUT ;
    USE SIGNAL ;
    PORT
      LAYER M5 ;
        RECT  44.016 25.728 44.04 25.92 ;
    END
  END o[273]
  PIN o[274]
    DIRECTION OUTPUT ;
    USE SIGNAL ;
    PORT
      LAYER M3 ;
        RECT  44.172 25.776 44.19 25.92 ;
    END
  END o[274]
  PIN o[275]
    DIRECTION OUTPUT ;
    USE SIGNAL ;
    PORT
      LAYER M5 ;
        RECT  44.352 25.728 44.376 25.92 ;
    END
  END o[275]
  PIN o[276]
    DIRECTION OUTPUT ;
    USE SIGNAL ;
    PORT
      LAYER M3 ;
        RECT  44.496 25.776 44.514 25.92 ;
    END
  END o[276]
  PIN o[277]
    DIRECTION OUTPUT ;
    USE SIGNAL ;
    PORT
      LAYER M5 ;
        RECT  44.64 25.728 44.664 25.92 ;
    END
  END o[277]
  PIN o[278]
    DIRECTION OUTPUT ;
    USE SIGNAL ;
    PORT
      LAYER M3 ;
        RECT  44.784 25.776 44.802 25.92 ;
    END
  END o[278]
  PIN o[279]
    DIRECTION OUTPUT ;
    USE SIGNAL ;
    PORT
      LAYER M5 ;
        RECT  44.928 25.728 44.952 25.92 ;
    END
  END o[279]
  PIN o[27]
    DIRECTION OUTPUT ;
    USE SIGNAL ;
    PORT
      LAYER M5 ;
        RECT  6.336 25.728 6.36 25.92 ;
    END
  END o[27]
  PIN o[280]
    DIRECTION OUTPUT ;
    USE SIGNAL ;
    PORT
      LAYER M3 ;
        RECT  45.108 25.776 45.126 25.92 ;
    END
  END o[280]
  PIN o[281]
    DIRECTION OUTPUT ;
    USE SIGNAL ;
    PORT
      LAYER M5 ;
        RECT  45.264 25.728 45.288 25.92 ;
    END
  END o[281]
  PIN o[282]
    DIRECTION OUTPUT ;
    USE SIGNAL ;
    PORT
      LAYER M3 ;
        RECT  45.396 25.776 45.414 25.92 ;
    END
  END o[282]
  PIN o[283]
    DIRECTION OUTPUT ;
    USE SIGNAL ;
    PORT
      LAYER M5 ;
        RECT  45.552 25.728 45.576 25.92 ;
    END
  END o[283]
  PIN o[284]
    DIRECTION OUTPUT ;
    USE SIGNAL ;
    PORT
      LAYER M3 ;
        RECT  45.72 25.776 45.738 25.92 ;
    END
  END o[284]
  PIN o[285]
    DIRECTION OUTPUT ;
    USE SIGNAL ;
    PORT
      LAYER M5 ;
        RECT  45.888 25.728 45.912 25.92 ;
    END
  END o[285]
  PIN o[286]
    DIRECTION OUTPUT ;
    USE SIGNAL ;
    PORT
      LAYER M3 ;
        RECT  46.008 25.776 46.026 25.92 ;
    END
  END o[286]
  PIN o[287]
    DIRECTION OUTPUT ;
    USE SIGNAL ;
    PORT
      LAYER M5 ;
        RECT  46.176 25.728 46.2 25.92 ;
    END
  END o[287]
  PIN o[288]
    DIRECTION OUTPUT ;
    USE SIGNAL ;
    PORT
      LAYER M3 ;
        RECT  46.332 25.776 46.35 25.92 ;
    END
  END o[288]
  PIN o[289]
    DIRECTION OUTPUT ;
    USE SIGNAL ;
    PORT
      LAYER M5 ;
        RECT  46.464 25.728 46.488 25.92 ;
    END
  END o[289]
  PIN o[28]
    DIRECTION OUTPUT ;
    USE SIGNAL ;
    PORT
      LAYER M3 ;
        RECT  6.516 25.776 6.534 25.92 ;
    END
  END o[28]
  PIN o[290]
    DIRECTION OUTPUT ;
    USE SIGNAL ;
    PORT
      LAYER M3 ;
        RECT  46.62 25.776 46.638 25.92 ;
    END
  END o[290]
  PIN o[291]
    DIRECTION OUTPUT ;
    USE SIGNAL ;
    PORT
      LAYER M5 ;
        RECT  46.8 25.728 46.824 25.92 ;
    END
  END o[291]
  PIN o[292]
    DIRECTION OUTPUT ;
    USE SIGNAL ;
    PORT
      LAYER M3 ;
        RECT  46.944 25.776 46.962 25.92 ;
    END
  END o[292]
  PIN o[293]
    DIRECTION OUTPUT ;
    USE SIGNAL ;
    PORT
      LAYER M5 ;
        RECT  47.088 25.728 47.112 25.92 ;
    END
  END o[293]
  PIN o[294]
    DIRECTION OUTPUT ;
    USE SIGNAL ;
    PORT
      LAYER M3 ;
        RECT  47.232 25.776 47.25 25.92 ;
    END
  END o[294]
  PIN o[295]
    DIRECTION OUTPUT ;
    USE SIGNAL ;
    PORT
      LAYER M5 ;
        RECT  47.376 25.728 47.4 25.92 ;
    END
  END o[295]
  PIN o[296]
    DIRECTION OUTPUT ;
    USE SIGNAL ;
    PORT
      LAYER M3 ;
        RECT  47.556 25.776 47.574 25.92 ;
    END
  END o[296]
  PIN o[297]
    DIRECTION OUTPUT ;
    USE SIGNAL ;
    PORT
      LAYER M5 ;
        RECT  47.712 25.728 47.736 25.92 ;
    END
  END o[297]
  PIN o[298]
    DIRECTION OUTPUT ;
    USE SIGNAL ;
    PORT
      LAYER M3 ;
        RECT  47.844 25.776 47.862 25.92 ;
    END
  END o[298]
  PIN o[299]
    DIRECTION OUTPUT ;
    USE SIGNAL ;
    PORT
      LAYER M5 ;
        RECT  48 25.728 48.024 25.92 ;
    END
  END o[299]
  PIN o[29]
    DIRECTION OUTPUT ;
    USE SIGNAL ;
    PORT
      LAYER M5 ;
        RECT  6.672 25.728 6.696 25.92 ;
    END
  END o[29]
  PIN o[2]
    DIRECTION OUTPUT ;
    USE SIGNAL ;
    PORT
      LAYER M3 ;
        RECT  2.52 25.776 2.538 25.92 ;
    END
  END o[2]
  PIN o[300]
    DIRECTION OUTPUT ;
    USE SIGNAL ;
    PORT
      LAYER M3 ;
        RECT  48.168 25.776 48.186 25.92 ;
    END
  END o[300]
  PIN o[301]
    DIRECTION OUTPUT ;
    USE SIGNAL ;
    PORT
      LAYER M5 ;
        RECT  48.336 25.728 48.36 25.92 ;
    END
  END o[301]
  PIN o[302]
    DIRECTION OUTPUT ;
    USE SIGNAL ;
    PORT
      LAYER M3 ;
        RECT  48.492 25.776 48.51 25.92 ;
    END
  END o[302]
  PIN o[303]
    DIRECTION OUTPUT ;
    USE SIGNAL ;
    PORT
      LAYER M5 ;
        RECT  48.624 25.728 48.648 25.92 ;
    END
  END o[303]
  PIN o[304]
    DIRECTION OUTPUT ;
    USE SIGNAL ;
    PORT
      LAYER M3 ;
        RECT  48.78 25.776 48.798 25.92 ;
    END
  END o[304]
  PIN o[305]
    DIRECTION OUTPUT ;
    USE SIGNAL ;
    PORT
      LAYER M5 ;
        RECT  48.912 25.728 48.936 25.92 ;
    END
  END o[305]
  PIN o[306]
    DIRECTION OUTPUT ;
    USE SIGNAL ;
    PORT
      LAYER M3 ;
        RECT  49.104 25.776 49.122 25.92 ;
    END
  END o[306]
  PIN o[307]
    DIRECTION OUTPUT ;
    USE SIGNAL ;
    PORT
      LAYER M5 ;
        RECT  49.248 25.728 49.272 25.92 ;
    END
  END o[307]
  PIN o[308]
    DIRECTION OUTPUT ;
    USE SIGNAL ;
    PORT
      LAYER M3 ;
        RECT  49.392 25.776 49.41 25.92 ;
    END
  END o[308]
  PIN o[309]
    DIRECTION OUTPUT ;
    USE SIGNAL ;
    PORT
      LAYER M5 ;
        RECT  49.536 25.728 49.56 25.92 ;
    END
  END o[309]
  PIN o[30]
    DIRECTION OUTPUT ;
    USE SIGNAL ;
    PORT
      LAYER M3 ;
        RECT  6.804 25.776 6.822 25.92 ;
    END
  END o[30]
  PIN o[310]
    DIRECTION OUTPUT ;
    USE SIGNAL ;
    PORT
      LAYER M3 ;
        RECT  49.716 25.776 49.734 25.92 ;
    END
  END o[310]
  PIN o[311]
    DIRECTION OUTPUT ;
    USE SIGNAL ;
    PORT
      LAYER M5 ;
        RECT  49.872 25.728 49.896 25.92 ;
    END
  END o[311]
  PIN o[312]
    DIRECTION OUTPUT ;
    USE SIGNAL ;
    PORT
      LAYER M3 ;
        RECT  50.004 25.776 50.022 25.92 ;
    END
  END o[312]
  PIN o[313]
    DIRECTION OUTPUT ;
    USE SIGNAL ;
    PORT
      LAYER M5 ;
        RECT  50.16 25.728 50.184 25.92 ;
    END
  END o[313]
  PIN o[314]
    DIRECTION OUTPUT ;
    USE SIGNAL ;
    PORT
      LAYER M3 ;
        RECT  50.328 25.776 50.346 25.92 ;
    END
  END o[314]
  PIN o[315]
    DIRECTION OUTPUT ;
    USE SIGNAL ;
    PORT
      LAYER M5 ;
        RECT  50.448 25.728 50.472 25.92 ;
    END
  END o[315]
  PIN o[316]
    DIRECTION OUTPUT ;
    USE SIGNAL ;
    PORT
      LAYER M3 ;
        RECT  50.616 25.776 50.634 25.92 ;
    END
  END o[316]
  PIN o[317]
    DIRECTION OUTPUT ;
    USE SIGNAL ;
    PORT
      LAYER M5 ;
        RECT  50.784 25.728 50.808 25.92 ;
    END
  END o[317]
  PIN o[318]
    DIRECTION OUTPUT ;
    USE SIGNAL ;
    PORT
      LAYER M3 ;
        RECT  50.94 25.776 50.958 25.92 ;
    END
  END o[318]
  PIN o[319]
    DIRECTION OUTPUT ;
    USE SIGNAL ;
    PORT
      LAYER M5 ;
        RECT  51.072 25.728 51.096 25.92 ;
    END
  END o[319]
  PIN o[31]
    DIRECTION OUTPUT ;
    USE SIGNAL ;
    PORT
      LAYER M5 ;
        RECT  6.96 25.728 6.984 25.92 ;
    END
  END o[31]
  PIN o[320]
    DIRECTION OUTPUT ;
    USE SIGNAL ;
    PORT
      LAYER M3 ;
        RECT  51.228 25.776 51.246 25.92 ;
    END
  END o[320]
  PIN o[321]
    DIRECTION OUTPUT ;
    USE SIGNAL ;
    PORT
      LAYER M5 ;
        RECT  51.36 25.728 51.384 25.92 ;
    END
  END o[321]
  PIN o[322]
    DIRECTION OUTPUT ;
    USE SIGNAL ;
    PORT
      LAYER M3 ;
        RECT  51.552 25.776 51.57 25.92 ;
    END
  END o[322]
  PIN o[323]
    DIRECTION OUTPUT ;
    USE SIGNAL ;
    PORT
      LAYER M5 ;
        RECT  51.696 25.728 51.72 25.92 ;
    END
  END o[323]
  PIN o[324]
    DIRECTION OUTPUT ;
    USE SIGNAL ;
    PORT
      LAYER M3 ;
        RECT  51.84 25.776 51.858 25.92 ;
    END
  END o[324]
  PIN o[325]
    DIRECTION OUTPUT ;
    USE SIGNAL ;
    PORT
      LAYER M5 ;
        RECT  51.984 25.728 52.008 25.92 ;
    END
  END o[325]
  PIN o[326]
    DIRECTION OUTPUT ;
    USE SIGNAL ;
    PORT
      LAYER M3 ;
        RECT  52.164 25.776 52.182 25.92 ;
    END
  END o[326]
  PIN o[327]
    DIRECTION OUTPUT ;
    USE SIGNAL ;
    PORT
      LAYER M5 ;
        RECT  52.32 25.728 52.344 25.92 ;
    END
  END o[327]
  PIN o[328]
    DIRECTION OUTPUT ;
    USE SIGNAL ;
    PORT
      LAYER M3 ;
        RECT  52.452 25.776 52.47 25.92 ;
    END
  END o[328]
  PIN o[329]
    DIRECTION OUTPUT ;
    USE SIGNAL ;
    PORT
      LAYER M5 ;
        RECT  52.608 25.728 52.632 25.92 ;
    END
  END o[329]
  PIN o[32]
    DIRECTION OUTPUT ;
    USE SIGNAL ;
    PORT
      LAYER M3 ;
        RECT  7.128 25.776 7.146 25.92 ;
    END
  END o[32]
  PIN o[330]
    DIRECTION OUTPUT ;
    USE SIGNAL ;
    PORT
      LAYER M3 ;
        RECT  52.776 25.776 52.794 25.92 ;
    END
  END o[330]
  PIN o[331]
    DIRECTION OUTPUT ;
    USE SIGNAL ;
    PORT
      LAYER M5 ;
        RECT  52.896 25.728 52.92 25.92 ;
    END
  END o[331]
  PIN o[332]
    DIRECTION OUTPUT ;
    USE SIGNAL ;
    PORT
      LAYER M3 ;
        RECT  53.064 25.776 53.082 25.92 ;
    END
  END o[332]
  PIN o[333]
    DIRECTION OUTPUT ;
    USE SIGNAL ;
    PORT
      LAYER M5 ;
        RECT  53.232 25.728 53.256 25.92 ;
    END
  END o[333]
  PIN o[334]
    DIRECTION OUTPUT ;
    USE SIGNAL ;
    PORT
      LAYER M3 ;
        RECT  53.388 25.776 53.406 25.92 ;
    END
  END o[334]
  PIN o[335]
    DIRECTION OUTPUT ;
    USE SIGNAL ;
    PORT
      LAYER M5 ;
        RECT  53.52 25.728 53.544 25.92 ;
    END
  END o[335]
  PIN o[336]
    DIRECTION OUTPUT ;
    USE SIGNAL ;
    PORT
      LAYER M3 ;
        RECT  53.676 25.776 53.694 25.92 ;
    END
  END o[336]
  PIN o[337]
    DIRECTION OUTPUT ;
    USE SIGNAL ;
    PORT
      LAYER M5 ;
        RECT  53.808 25.728 53.832 25.92 ;
    END
  END o[337]
  PIN o[338]
    DIRECTION OUTPUT ;
    USE SIGNAL ;
    PORT
      LAYER M3 ;
        RECT  54 25.776 54.018 25.92 ;
    END
  END o[338]
  PIN o[339]
    DIRECTION OUTPUT ;
    USE SIGNAL ;
    PORT
      LAYER M5 ;
        RECT  54.144 25.728 54.168 25.92 ;
    END
  END o[339]
  PIN o[33]
    DIRECTION OUTPUT ;
    USE SIGNAL ;
    PORT
      LAYER M5 ;
        RECT  7.296 25.728 7.32 25.92 ;
    END
  END o[33]
  PIN o[340]
    DIRECTION OUTPUT ;
    USE SIGNAL ;
    PORT
      LAYER M3 ;
        RECT  54.288 25.776 54.306 25.92 ;
    END
  END o[340]
  PIN o[341]
    DIRECTION OUTPUT ;
    USE SIGNAL ;
    PORT
      LAYER M5 ;
        RECT  54.432 25.728 54.456 25.92 ;
    END
  END o[341]
  PIN o[342]
    DIRECTION OUTPUT ;
    USE SIGNAL ;
    PORT
      LAYER M3 ;
        RECT  54.612 25.776 54.63 25.92 ;
    END
  END o[342]
  PIN o[343]
    DIRECTION OUTPUT ;
    USE SIGNAL ;
    PORT
      LAYER M5 ;
        RECT  54.768 25.728 54.792 25.92 ;
    END
  END o[343]
  PIN o[344]
    DIRECTION OUTPUT ;
    USE SIGNAL ;
    PORT
      LAYER M3 ;
        RECT  54.9 25.776 54.918 25.92 ;
    END
  END o[344]
  PIN o[345]
    DIRECTION OUTPUT ;
    USE SIGNAL ;
    PORT
      LAYER M5 ;
        RECT  55.056 25.728 55.08 25.92 ;
    END
  END o[345]
  PIN o[346]
    DIRECTION OUTPUT ;
    USE SIGNAL ;
    PORT
      LAYER M3 ;
        RECT  55.224 25.776 55.242 25.92 ;
    END
  END o[346]
  PIN o[347]
    DIRECTION OUTPUT ;
    USE SIGNAL ;
    PORT
      LAYER M5 ;
        RECT  55.344 25.728 55.368 25.92 ;
    END
  END o[347]
  PIN o[348]
    DIRECTION OUTPUT ;
    USE SIGNAL ;
    PORT
      LAYER M3 ;
        RECT  55.512 25.776 55.53 25.92 ;
    END
  END o[348]
  PIN o[349]
    DIRECTION OUTPUT ;
    USE SIGNAL ;
    PORT
      LAYER M5 ;
        RECT  55.68 25.728 55.704 25.92 ;
    END
  END o[349]
  PIN o[34]
    DIRECTION OUTPUT ;
    USE SIGNAL ;
    PORT
      LAYER M3 ;
        RECT  7.452 25.776 7.47 25.92 ;
    END
  END o[34]
  PIN o[350]
    DIRECTION OUTPUT ;
    USE SIGNAL ;
    PORT
      LAYER M3 ;
        RECT  55.836 25.776 55.854 25.92 ;
    END
  END o[350]
  PIN o[351]
    DIRECTION OUTPUT ;
    USE SIGNAL ;
    PORT
      LAYER M5 ;
        RECT  55.968 25.728 55.992 25.92 ;
    END
  END o[351]
  PIN o[352]
    DIRECTION OUTPUT ;
    USE SIGNAL ;
    PORT
      LAYER M3 ;
        RECT  56.124 25.776 56.142 25.92 ;
    END
  END o[352]
  PIN o[353]
    DIRECTION OUTPUT ;
    USE SIGNAL ;
    PORT
      LAYER M5 ;
        RECT  56.304 25.728 56.328 25.92 ;
    END
  END o[353]
  PIN o[354]
    DIRECTION OUTPUT ;
    USE SIGNAL ;
    PORT
      LAYER M3 ;
        RECT  56.448 25.776 56.466 25.92 ;
    END
  END o[354]
  PIN o[355]
    DIRECTION OUTPUT ;
    USE SIGNAL ;
    PORT
      LAYER M5 ;
        RECT  56.592 25.728 56.616 25.92 ;
    END
  END o[355]
  PIN o[356]
    DIRECTION OUTPUT ;
    USE SIGNAL ;
    PORT
      LAYER M3 ;
        RECT  56.736 25.776 56.754 25.92 ;
    END
  END o[356]
  PIN o[357]
    DIRECTION OUTPUT ;
    USE SIGNAL ;
    PORT
      LAYER M5 ;
        RECT  56.88 25.728 56.904 25.92 ;
    END
  END o[357]
  PIN o[358]
    DIRECTION OUTPUT ;
    USE SIGNAL ;
    PORT
      LAYER M3 ;
        RECT  57.06 25.776 57.078 25.92 ;
    END
  END o[358]
  PIN o[359]
    DIRECTION OUTPUT ;
    USE SIGNAL ;
    PORT
      LAYER M5 ;
        RECT  57.216 25.728 57.24 25.92 ;
    END
  END o[359]
  PIN o[35]
    DIRECTION OUTPUT ;
    USE SIGNAL ;
    PORT
      LAYER M5 ;
        RECT  7.584 25.728 7.608 25.92 ;
    END
  END o[35]
  PIN o[360]
    DIRECTION OUTPUT ;
    USE SIGNAL ;
    PORT
      LAYER M3 ;
        RECT  57.348 25.776 57.366 25.92 ;
    END
  END o[360]
  PIN o[361]
    DIRECTION OUTPUT ;
    USE SIGNAL ;
    PORT
      LAYER M5 ;
        RECT  57.504 25.728 57.528 25.92 ;
    END
  END o[361]
  PIN o[362]
    DIRECTION OUTPUT ;
    USE SIGNAL ;
    PORT
      LAYER M3 ;
        RECT  57.672 25.776 57.69 25.92 ;
    END
  END o[362]
  PIN o[363]
    DIRECTION OUTPUT ;
    USE SIGNAL ;
    PORT
      LAYER M5 ;
        RECT  57.792 25.728 57.816 25.92 ;
    END
  END o[363]
  PIN o[364]
    DIRECTION OUTPUT ;
    USE SIGNAL ;
    PORT
      LAYER M3 ;
        RECT  57.96 25.776 57.978 25.92 ;
    END
  END o[364]
  PIN o[365]
    DIRECTION OUTPUT ;
    USE SIGNAL ;
    PORT
      LAYER M5 ;
        RECT  58.128 25.728 58.152 25.92 ;
    END
  END o[365]
  PIN o[366]
    DIRECTION OUTPUT ;
    USE SIGNAL ;
    PORT
      LAYER M3 ;
        RECT  58.284 25.776 58.302 25.92 ;
    END
  END o[366]
  PIN o[367]
    DIRECTION OUTPUT ;
    USE SIGNAL ;
    PORT
      LAYER M5 ;
        RECT  58.416 25.728 58.44 25.92 ;
    END
  END o[367]
  PIN o[368]
    DIRECTION OUTPUT ;
    USE SIGNAL ;
    PORT
      LAYER M3 ;
        RECT  58.572 25.776 58.59 25.92 ;
    END
  END o[368]
  PIN o[369]
    DIRECTION OUTPUT ;
    USE SIGNAL ;
    PORT
      LAYER M5 ;
        RECT  58.752 25.728 58.776 25.92 ;
    END
  END o[369]
  PIN o[36]
    DIRECTION OUTPUT ;
    USE SIGNAL ;
    PORT
      LAYER M3 ;
        RECT  7.74 25.776 7.758 25.92 ;
    END
  END o[36]
  PIN o[370]
    DIRECTION OUTPUT ;
    USE SIGNAL ;
    PORT
      LAYER M3 ;
        RECT  58.896 25.776 58.914 25.92 ;
    END
  END o[370]
  PIN o[371]
    DIRECTION OUTPUT ;
    USE SIGNAL ;
    PORT
      LAYER M5 ;
        RECT  59.04 25.728 59.064 25.92 ;
    END
  END o[371]
  PIN o[372]
    DIRECTION OUTPUT ;
    USE SIGNAL ;
    PORT
      LAYER M3 ;
        RECT  59.184 25.776 59.202 25.92 ;
    END
  END o[372]
  PIN o[373]
    DIRECTION OUTPUT ;
    USE SIGNAL ;
    PORT
      LAYER M5 ;
        RECT  59.328 25.728 59.352 25.92 ;
    END
  END o[373]
  PIN o[374]
    DIRECTION OUTPUT ;
    USE SIGNAL ;
    PORT
      LAYER M3 ;
        RECT  59.508 25.776 59.526 25.92 ;
    END
  END o[374]
  PIN o[375]
    DIRECTION OUTPUT ;
    USE SIGNAL ;
    PORT
      LAYER M5 ;
        RECT  59.664 25.728 59.688 25.92 ;
    END
  END o[375]
  PIN o[376]
    DIRECTION OUTPUT ;
    USE SIGNAL ;
    PORT
      LAYER M3 ;
        RECT  59.796 25.776 59.814 25.92 ;
    END
  END o[376]
  PIN o[377]
    DIRECTION OUTPUT ;
    USE SIGNAL ;
    PORT
      LAYER M5 ;
        RECT  59.952 25.728 59.976 25.92 ;
    END
  END o[377]
  PIN o[378]
    DIRECTION OUTPUT ;
    USE SIGNAL ;
    PORT
      LAYER M3 ;
        RECT  60.12 25.776 60.138 25.92 ;
    END
  END o[378]
  PIN o[379]
    DIRECTION OUTPUT ;
    USE SIGNAL ;
    PORT
      LAYER M5 ;
        RECT  60.24 25.728 60.264 25.92 ;
    END
  END o[379]
  PIN o[37]
    DIRECTION OUTPUT ;
    USE SIGNAL ;
    PORT
      LAYER M5 ;
        RECT  7.872 25.728 7.896 25.92 ;
    END
  END o[37]
  PIN o[380]
    DIRECTION OUTPUT ;
    USE SIGNAL ;
    PORT
      LAYER M3 ;
        RECT  60.408 25.776 60.426 25.92 ;
    END
  END o[380]
  PIN o[381]
    DIRECTION OUTPUT ;
    USE SIGNAL ;
    PORT
      LAYER M5 ;
        RECT  60.576 25.728 60.6 25.92 ;
    END
  END o[381]
  PIN o[382]
    DIRECTION OUTPUT ;
    USE SIGNAL ;
    PORT
      LAYER M3 ;
        RECT  60.732 25.776 60.75 25.92 ;
    END
  END o[382]
  PIN o[383]
    DIRECTION OUTPUT ;
    USE SIGNAL ;
    PORT
      LAYER M5 ;
        RECT  60.864 25.728 60.888 25.92 ;
    END
  END o[383]
  PIN o[384]
    DIRECTION OUTPUT ;
    USE SIGNAL ;
    PORT
      LAYER M3 ;
        RECT  61.02 25.776 61.038 25.92 ;
    END
  END o[384]
  PIN o[385]
    DIRECTION OUTPUT ;
    USE SIGNAL ;
    PORT
      LAYER M5 ;
        RECT  61.2 25.728 61.224 25.92 ;
    END
  END o[385]
  PIN o[386]
    DIRECTION OUTPUT ;
    USE SIGNAL ;
    PORT
      LAYER M3 ;
        RECT  61.344 25.776 61.362 25.92 ;
    END
  END o[386]
  PIN o[387]
    DIRECTION OUTPUT ;
    USE SIGNAL ;
    PORT
      LAYER M5 ;
        RECT  61.488 25.728 61.512 25.92 ;
    END
  END o[387]
  PIN o[388]
    DIRECTION OUTPUT ;
    USE SIGNAL ;
    PORT
      LAYER M3 ;
        RECT  61.632 25.776 61.65 25.92 ;
    END
  END o[388]
  PIN o[389]
    DIRECTION OUTPUT ;
    USE SIGNAL ;
    PORT
      LAYER M5 ;
        RECT  61.776 25.728 61.8 25.92 ;
    END
  END o[389]
  PIN o[38]
    DIRECTION OUTPUT ;
    USE SIGNAL ;
    PORT
      LAYER M3 ;
        RECT  8.064 25.776 8.082 25.92 ;
    END
  END o[38]
  PIN o[390]
    DIRECTION OUTPUT ;
    USE SIGNAL ;
    PORT
      LAYER M3 ;
        RECT  61.956 25.776 61.974 25.92 ;
    END
  END o[390]
  PIN o[391]
    DIRECTION OUTPUT ;
    USE SIGNAL ;
    PORT
      LAYER M5 ;
        RECT  62.112 25.728 62.136 25.92 ;
    END
  END o[391]
  PIN o[392]
    DIRECTION OUTPUT ;
    USE SIGNAL ;
    PORT
      LAYER M3 ;
        RECT  62.244 25.776 62.262 25.92 ;
    END
  END o[392]
  PIN o[393]
    DIRECTION OUTPUT ;
    USE SIGNAL ;
    PORT
      LAYER M5 ;
        RECT  62.4 25.728 62.424 25.92 ;
    END
  END o[393]
  PIN o[394]
    DIRECTION OUTPUT ;
    USE SIGNAL ;
    PORT
      LAYER M3 ;
        RECT  62.568 25.776 62.586 25.92 ;
    END
  END o[394]
  PIN o[395]
    DIRECTION OUTPUT ;
    USE SIGNAL ;
    PORT
      LAYER M5 ;
        RECT  62.736 25.728 62.76 25.92 ;
    END
  END o[395]
  PIN o[396]
    DIRECTION OUTPUT ;
    USE SIGNAL ;
    PORT
      LAYER M3 ;
        RECT  62.856 25.776 62.874 25.92 ;
    END
  END o[396]
  PIN o[397]
    DIRECTION OUTPUT ;
    USE SIGNAL ;
    PORT
      LAYER M5 ;
        RECT  63.024 25.728 63.048 25.92 ;
    END
  END o[397]
  PIN o[398]
    DIRECTION OUTPUT ;
    USE SIGNAL ;
    PORT
      LAYER M3 ;
        RECT  63.18 25.776 63.198 25.92 ;
    END
  END o[398]
  PIN o[399]
    DIRECTION OUTPUT ;
    USE SIGNAL ;
    PORT
      LAYER M5 ;
        RECT  63.312 25.728 63.336 25.92 ;
    END
  END o[399]
  PIN o[39]
    DIRECTION OUTPUT ;
    USE SIGNAL ;
    PORT
      LAYER M5 ;
        RECT  8.208 25.728 8.232 25.92 ;
    END
  END o[39]
  PIN o[3]
    DIRECTION OUTPUT ;
    USE SIGNAL ;
    PORT
      LAYER M5 ;
        RECT  2.688 25.728 2.712 25.92 ;
    END
  END o[3]
  PIN o[400]
    DIRECTION OUTPUT ;
    USE SIGNAL ;
    PORT
      LAYER M3 ;
        RECT  63.468 25.776 63.486 25.92 ;
    END
  END o[400]
  PIN o[401]
    DIRECTION OUTPUT ;
    USE SIGNAL ;
    PORT
      LAYER M5 ;
        RECT  63.648 25.728 63.672 25.92 ;
    END
  END o[401]
  PIN o[402]
    DIRECTION OUTPUT ;
    USE SIGNAL ;
    PORT
      LAYER M3 ;
        RECT  63.792 25.776 63.81 25.92 ;
    END
  END o[402]
  PIN o[403]
    DIRECTION OUTPUT ;
    USE SIGNAL ;
    PORT
      LAYER M5 ;
        RECT  63.936 25.728 63.96 25.92 ;
    END
  END o[403]
  PIN o[404]
    DIRECTION OUTPUT ;
    USE SIGNAL ;
    PORT
      LAYER M3 ;
        RECT  64.08 25.776 64.098 25.92 ;
    END
  END o[404]
  PIN o[405]
    DIRECTION OUTPUT ;
    USE SIGNAL ;
    PORT
      LAYER M5 ;
        RECT  64.224 25.728 64.248 25.92 ;
    END
  END o[405]
  PIN o[406]
    DIRECTION OUTPUT ;
    USE SIGNAL ;
    PORT
      LAYER M3 ;
        RECT  64.404 25.776 64.422 25.92 ;
    END
  END o[406]
  PIN o[407]
    DIRECTION OUTPUT ;
    USE SIGNAL ;
    PORT
      LAYER M5 ;
        RECT  64.56 25.728 64.584 25.92 ;
    END
  END o[407]
  PIN o[408]
    DIRECTION OUTPUT ;
    USE SIGNAL ;
    PORT
      LAYER M3 ;
        RECT  64.692 25.776 64.71 25.92 ;
    END
  END o[408]
  PIN o[409]
    DIRECTION OUTPUT ;
    USE SIGNAL ;
    PORT
      LAYER M5 ;
        RECT  64.848 25.728 64.872 25.92 ;
    END
  END o[409]
  PIN o[40]
    DIRECTION OUTPUT ;
    USE SIGNAL ;
    PORT
      LAYER M3 ;
        RECT  8.352 25.776 8.37 25.92 ;
    END
  END o[40]
  PIN o[410]
    DIRECTION OUTPUT ;
    USE SIGNAL ;
    PORT
      LAYER M3 ;
        RECT  65.016 25.776 65.034 25.92 ;
    END
  END o[410]
  PIN o[411]
    DIRECTION OUTPUT ;
    USE SIGNAL ;
    PORT
      LAYER M5 ;
        RECT  65.184 25.728 65.208 25.92 ;
    END
  END o[411]
  PIN o[412]
    DIRECTION OUTPUT ;
    USE SIGNAL ;
    PORT
      LAYER M3 ;
        RECT  65.304 25.776 65.322 25.92 ;
    END
  END o[412]
  PIN o[413]
    DIRECTION OUTPUT ;
    USE SIGNAL ;
    PORT
      LAYER M5 ;
        RECT  65.472 25.728 65.496 25.92 ;
    END
  END o[413]
  PIN o[414]
    DIRECTION OUTPUT ;
    USE SIGNAL ;
    PORT
      LAYER M3 ;
        RECT  65.628 25.776 65.646 25.92 ;
    END
  END o[414]
  PIN o[415]
    DIRECTION OUTPUT ;
    USE SIGNAL ;
    PORT
      LAYER M5 ;
        RECT  65.76 25.728 65.784 25.92 ;
    END
  END o[415]
  PIN o[416]
    DIRECTION OUTPUT ;
    USE SIGNAL ;
    PORT
      LAYER M3 ;
        RECT  65.916 25.776 65.934 25.92 ;
    END
  END o[416]
  PIN o[417]
    DIRECTION OUTPUT ;
    USE SIGNAL ;
    PORT
      LAYER M5 ;
        RECT  66.096 25.728 66.12 25.92 ;
    END
  END o[417]
  PIN o[418]
    DIRECTION OUTPUT ;
    USE SIGNAL ;
    PORT
      LAYER M3 ;
        RECT  66.24 25.776 66.258 25.92 ;
    END
  END o[418]
  PIN o[419]
    DIRECTION OUTPUT ;
    USE SIGNAL ;
    PORT
      LAYER M5 ;
        RECT  66.384 25.728 66.408 25.92 ;
    END
  END o[419]
  PIN o[41]
    DIRECTION OUTPUT ;
    USE SIGNAL ;
    PORT
      LAYER M5 ;
        RECT  8.496 25.728 8.52 25.92 ;
    END
  END o[41]
  PIN o[420]
    DIRECTION OUTPUT ;
    USE SIGNAL ;
    PORT
      LAYER M3 ;
        RECT  66.528 25.776 66.546 25.92 ;
    END
  END o[420]
  PIN o[421]
    DIRECTION OUTPUT ;
    USE SIGNAL ;
    PORT
      LAYER M5 ;
        RECT  66.672 25.728 66.696 25.92 ;
    END
  END o[421]
  PIN o[422]
    DIRECTION OUTPUT ;
    USE SIGNAL ;
    PORT
      LAYER M3 ;
        RECT  66.852 25.776 66.87 25.92 ;
    END
  END o[422]
  PIN o[423]
    DIRECTION OUTPUT ;
    USE SIGNAL ;
    PORT
      LAYER M5 ;
        RECT  67.008 25.728 67.032 25.92 ;
    END
  END o[423]
  PIN o[424]
    DIRECTION OUTPUT ;
    USE SIGNAL ;
    PORT
      LAYER M3 ;
        RECT  67.14 25.776 67.158 25.92 ;
    END
  END o[424]
  PIN o[425]
    DIRECTION OUTPUT ;
    USE SIGNAL ;
    PORT
      LAYER M5 ;
        RECT  67.296 25.728 67.32 25.92 ;
    END
  END o[425]
  PIN o[426]
    DIRECTION OUTPUT ;
    USE SIGNAL ;
    PORT
      LAYER M3 ;
        RECT  67.464 25.776 67.482 25.92 ;
    END
  END o[426]
  PIN o[427]
    DIRECTION OUTPUT ;
    USE SIGNAL ;
    PORT
      LAYER M5 ;
        RECT  67.632 25.728 67.656 25.92 ;
    END
  END o[427]
  PIN o[428]
    DIRECTION OUTPUT ;
    USE SIGNAL ;
    PORT
      LAYER M3 ;
        RECT  67.752 25.776 67.77 25.92 ;
    END
  END o[428]
  PIN o[429]
    DIRECTION OUTPUT ;
    USE SIGNAL ;
    PORT
      LAYER M5 ;
        RECT  67.92 25.728 67.944 25.92 ;
    END
  END o[429]
  PIN o[42]
    DIRECTION OUTPUT ;
    USE SIGNAL ;
    PORT
      LAYER M3 ;
        RECT  8.676 25.776 8.694 25.92 ;
    END
  END o[42]
  PIN o[430]
    DIRECTION OUTPUT ;
    USE SIGNAL ;
    PORT
      LAYER M3 ;
        RECT  68.076 25.776 68.094 25.92 ;
    END
  END o[430]
  PIN o[431]
    DIRECTION OUTPUT ;
    USE SIGNAL ;
    PORT
      LAYER M5 ;
        RECT  68.208 25.728 68.232 25.92 ;
    END
  END o[431]
  PIN o[432]
    DIRECTION OUTPUT ;
    USE SIGNAL ;
    PORT
      LAYER M3 ;
        RECT  68.364 25.776 68.382 25.92 ;
    END
  END o[432]
  PIN o[433]
    DIRECTION OUTPUT ;
    USE SIGNAL ;
    PORT
      LAYER M5 ;
        RECT  68.544 25.728 68.568 25.92 ;
    END
  END o[433]
  PIN o[434]
    DIRECTION OUTPUT ;
    USE SIGNAL ;
    PORT
      LAYER M3 ;
        RECT  68.688 25.776 68.706 25.92 ;
    END
  END o[434]
  PIN o[435]
    DIRECTION OUTPUT ;
    USE SIGNAL ;
    PORT
      LAYER M5 ;
        RECT  68.832 25.728 68.856 25.92 ;
    END
  END o[435]
  PIN o[436]
    DIRECTION OUTPUT ;
    USE SIGNAL ;
    PORT
      LAYER M3 ;
        RECT  69.012 25.776 69.03 25.92 ;
    END
  END o[436]
  PIN o[437]
    DIRECTION OUTPUT ;
    USE SIGNAL ;
    PORT
      LAYER M5 ;
        RECT  69.168 25.728 69.192 25.92 ;
    END
  END o[437]
  PIN o[438]
    DIRECTION OUTPUT ;
    USE SIGNAL ;
    PORT
      LAYER M3 ;
        RECT  69.3 25.776 69.318 25.92 ;
    END
  END o[438]
  PIN o[439]
    DIRECTION OUTPUT ;
    USE SIGNAL ;
    PORT
      LAYER M5 ;
        RECT  69.456 25.728 69.48 25.92 ;
    END
  END o[439]
  PIN o[43]
    DIRECTION OUTPUT ;
    USE SIGNAL ;
    PORT
      LAYER M5 ;
        RECT  8.832 25.728 8.856 25.92 ;
    END
  END o[43]
  PIN o[440]
    DIRECTION OUTPUT ;
    USE SIGNAL ;
    PORT
      LAYER M3 ;
        RECT  69.624 25.776 69.642 25.92 ;
    END
  END o[440]
  PIN o[441]
    DIRECTION OUTPUT ;
    USE SIGNAL ;
    PORT
      LAYER M5 ;
        RECT  69.744 25.728 69.768 25.92 ;
    END
  END o[441]
  PIN o[442]
    DIRECTION OUTPUT ;
    USE SIGNAL ;
    PORT
      LAYER M3 ;
        RECT  69.912 25.776 69.93 25.92 ;
    END
  END o[442]
  PIN o[443]
    DIRECTION OUTPUT ;
    USE SIGNAL ;
    PORT
      LAYER M5 ;
        RECT  70.08 25.728 70.104 25.92 ;
    END
  END o[443]
  PIN o[444]
    DIRECTION OUTPUT ;
    USE SIGNAL ;
    PORT
      LAYER M3 ;
        RECT  70.236 25.776 70.254 25.92 ;
    END
  END o[444]
  PIN o[445]
    DIRECTION OUTPUT ;
    USE SIGNAL ;
    PORT
      LAYER M5 ;
        RECT  70.368 25.728 70.392 25.92 ;
    END
  END o[445]
  PIN o[446]
    DIRECTION OUTPUT ;
    USE SIGNAL ;
    PORT
      LAYER M3 ;
        RECT  70.524 25.776 70.542 25.92 ;
    END
  END o[446]
  PIN o[447]
    DIRECTION OUTPUT ;
    USE SIGNAL ;
    PORT
      LAYER M5 ;
        RECT  70.656 25.728 70.68 25.92 ;
    END
  END o[447]
  PIN o[448]
    DIRECTION OUTPUT ;
    USE SIGNAL ;
    PORT
      LAYER M3 ;
        RECT  70.848 25.776 70.866 25.92 ;
    END
  END o[448]
  PIN o[449]
    DIRECTION OUTPUT ;
    USE SIGNAL ;
    PORT
      LAYER M5 ;
        RECT  70.992 25.728 71.016 25.92 ;
    END
  END o[449]
  PIN o[44]
    DIRECTION OUTPUT ;
    USE SIGNAL ;
    PORT
      LAYER M3 ;
        RECT  8.964 25.776 8.982 25.92 ;
    END
  END o[44]
  PIN o[450]
    DIRECTION OUTPUT ;
    USE SIGNAL ;
    PORT
      LAYER M3 ;
        RECT  71.136 25.776 71.154 25.92 ;
    END
  END o[450]
  PIN o[451]
    DIRECTION OUTPUT ;
    USE SIGNAL ;
    PORT
      LAYER M5 ;
        RECT  71.28 25.728 71.304 25.92 ;
    END
  END o[451]
  PIN o[452]
    DIRECTION OUTPUT ;
    USE SIGNAL ;
    PORT
      LAYER M3 ;
        RECT  71.46 25.776 71.478 25.92 ;
    END
  END o[452]
  PIN o[453]
    DIRECTION OUTPUT ;
    USE SIGNAL ;
    PORT
      LAYER M5 ;
        RECT  71.616 25.728 71.64 25.92 ;
    END
  END o[453]
  PIN o[454]
    DIRECTION OUTPUT ;
    USE SIGNAL ;
    PORT
      LAYER M3 ;
        RECT  71.748 25.776 71.766 25.92 ;
    END
  END o[454]
  PIN o[455]
    DIRECTION OUTPUT ;
    USE SIGNAL ;
    PORT
      LAYER M5 ;
        RECT  71.904 25.728 71.928 25.92 ;
    END
  END o[455]
  PIN o[456]
    DIRECTION OUTPUT ;
    USE SIGNAL ;
    PORT
      LAYER M3 ;
        RECT  72.072 25.776 72.09 25.92 ;
    END
  END o[456]
  PIN o[457]
    DIRECTION OUTPUT ;
    USE SIGNAL ;
    PORT
      LAYER M5 ;
        RECT  72.192 25.728 72.216 25.92 ;
    END
  END o[457]
  PIN o[458]
    DIRECTION OUTPUT ;
    USE SIGNAL ;
    PORT
      LAYER M3 ;
        RECT  72.36 25.776 72.378 25.92 ;
    END
  END o[458]
  PIN o[459]
    DIRECTION OUTPUT ;
    USE SIGNAL ;
    PORT
      LAYER M5 ;
        RECT  72.528 25.728 72.552 25.92 ;
    END
  END o[459]
  PIN o[45]
    DIRECTION OUTPUT ;
    USE SIGNAL ;
    PORT
      LAYER M5 ;
        RECT  9.12 25.728 9.144 25.92 ;
    END
  END o[45]
  PIN o[460]
    DIRECTION OUTPUT ;
    USE SIGNAL ;
    PORT
      LAYER M3 ;
        RECT  72.684 25.776 72.702 25.92 ;
    END
  END o[460]
  PIN o[461]
    DIRECTION OUTPUT ;
    USE SIGNAL ;
    PORT
      LAYER M5 ;
        RECT  72.816 25.728 72.84 25.92 ;
    END
  END o[461]
  PIN o[462]
    DIRECTION OUTPUT ;
    USE SIGNAL ;
    PORT
      LAYER M3 ;
        RECT  72.972 25.776 72.99 25.92 ;
    END
  END o[462]
  PIN o[463]
    DIRECTION OUTPUT ;
    USE SIGNAL ;
    PORT
      LAYER M5 ;
        RECT  73.104 25.728 73.128 25.92 ;
    END
  END o[463]
  PIN o[464]
    DIRECTION OUTPUT ;
    USE SIGNAL ;
    PORT
      LAYER M3 ;
        RECT  73.296 25.776 73.314 25.92 ;
    END
  END o[464]
  PIN o[465]
    DIRECTION OUTPUT ;
    USE SIGNAL ;
    PORT
      LAYER M5 ;
        RECT  73.44 25.728 73.464 25.92 ;
    END
  END o[465]
  PIN o[466]
    DIRECTION OUTPUT ;
    USE SIGNAL ;
    PORT
      LAYER M3 ;
        RECT  73.584 25.776 73.602 25.92 ;
    END
  END o[466]
  PIN o[467]
    DIRECTION OUTPUT ;
    USE SIGNAL ;
    PORT
      LAYER M5 ;
        RECT  73.728 25.728 73.752 25.92 ;
    END
  END o[467]
  PIN o[468]
    DIRECTION OUTPUT ;
    USE SIGNAL ;
    PORT
      LAYER M3 ;
        RECT  73.908 25.776 73.926 25.92 ;
    END
  END o[468]
  PIN o[469]
    DIRECTION OUTPUT ;
    USE SIGNAL ;
    PORT
      LAYER M5 ;
        RECT  74.064 25.728 74.088 25.92 ;
    END
  END o[469]
  PIN o[46]
    DIRECTION OUTPUT ;
    USE SIGNAL ;
    PORT
      LAYER M3 ;
        RECT  9.288 25.776 9.306 25.92 ;
    END
  END o[46]
  PIN o[470]
    DIRECTION OUTPUT ;
    USE SIGNAL ;
    PORT
      LAYER M3 ;
        RECT  74.196 25.776 74.214 25.92 ;
    END
  END o[470]
  PIN o[471]
    DIRECTION OUTPUT ;
    USE SIGNAL ;
    PORT
      LAYER M5 ;
        RECT  74.352 25.728 74.376 25.92 ;
    END
  END o[471]
  PIN o[472]
    DIRECTION OUTPUT ;
    USE SIGNAL ;
    PORT
      LAYER M3 ;
        RECT  74.52 25.776 74.538 25.92 ;
    END
  END o[472]
  PIN o[473]
    DIRECTION OUTPUT ;
    USE SIGNAL ;
    PORT
      LAYER M5 ;
        RECT  74.64 25.728 74.664 25.92 ;
    END
  END o[473]
  PIN o[474]
    DIRECTION OUTPUT ;
    USE SIGNAL ;
    PORT
      LAYER M3 ;
        RECT  74.808 25.776 74.826 25.92 ;
    END
  END o[474]
  PIN o[475]
    DIRECTION OUTPUT ;
    USE SIGNAL ;
    PORT
      LAYER M5 ;
        RECT  74.976 25.728 75 25.92 ;
    END
  END o[475]
  PIN o[476]
    DIRECTION OUTPUT ;
    USE SIGNAL ;
    PORT
      LAYER M3 ;
        RECT  75.132 25.776 75.15 25.92 ;
    END
  END o[476]
  PIN o[477]
    DIRECTION OUTPUT ;
    USE SIGNAL ;
    PORT
      LAYER M5 ;
        RECT  75.264 25.728 75.288 25.92 ;
    END
  END o[477]
  PIN o[478]
    DIRECTION OUTPUT ;
    USE SIGNAL ;
    PORT
      LAYER M3 ;
        RECT  75.42 25.776 75.438 25.92 ;
    END
  END o[478]
  PIN o[479]
    DIRECTION OUTPUT ;
    USE SIGNAL ;
    PORT
      LAYER M5 ;
        RECT  75.552 25.728 75.576 25.92 ;
    END
  END o[479]
  PIN o[47]
    DIRECTION OUTPUT ;
    USE SIGNAL ;
    PORT
      LAYER M5 ;
        RECT  9.408 25.728 9.432 25.92 ;
    END
  END o[47]
  PIN o[480]
    DIRECTION OUTPUT ;
    USE SIGNAL ;
    PORT
      LAYER M3 ;
        RECT  75.744 25.776 75.762 25.92 ;
    END
  END o[480]
  PIN o[481]
    DIRECTION OUTPUT ;
    USE SIGNAL ;
    PORT
      LAYER M5 ;
        RECT  75.888 25.728 75.912 25.92 ;
    END
  END o[481]
  PIN o[482]
    DIRECTION OUTPUT ;
    USE SIGNAL ;
    PORT
      LAYER M3 ;
        RECT  76.032 25.776 76.05 25.92 ;
    END
  END o[482]
  PIN o[483]
    DIRECTION OUTPUT ;
    USE SIGNAL ;
    PORT
      LAYER M5 ;
        RECT  76.176 25.728 76.2 25.92 ;
    END
  END o[483]
  PIN o[484]
    DIRECTION OUTPUT ;
    USE SIGNAL ;
    PORT
      LAYER M3 ;
        RECT  76.356 25.776 76.374 25.92 ;
    END
  END o[484]
  PIN o[485]
    DIRECTION OUTPUT ;
    USE SIGNAL ;
    PORT
      LAYER M5 ;
        RECT  76.512 25.728 76.536 25.92 ;
    END
  END o[485]
  PIN o[486]
    DIRECTION OUTPUT ;
    USE SIGNAL ;
    PORT
      LAYER M3 ;
        RECT  76.644 25.776 76.662 25.92 ;
    END
  END o[486]
  PIN o[487]
    DIRECTION OUTPUT ;
    USE SIGNAL ;
    PORT
      LAYER M5 ;
        RECT  76.8 25.728 76.824 25.92 ;
    END
  END o[487]
  PIN o[488]
    DIRECTION OUTPUT ;
    USE SIGNAL ;
    PORT
      LAYER M3 ;
        RECT  76.968 25.776 76.986 25.92 ;
    END
  END o[488]
  PIN o[489]
    DIRECTION OUTPUT ;
    USE SIGNAL ;
    PORT
      LAYER M5 ;
        RECT  77.088 25.728 77.112 25.92 ;
    END
  END o[489]
  PIN o[48]
    DIRECTION OUTPUT ;
    USE SIGNAL ;
    PORT
      LAYER M3 ;
        RECT  9.576 25.776 9.594 25.92 ;
    END
  END o[48]
  PIN o[490]
    DIRECTION OUTPUT ;
    USE SIGNAL ;
    PORT
      LAYER M3 ;
        RECT  77.256 25.776 77.274 25.92 ;
    END
  END o[490]
  PIN o[491]
    DIRECTION OUTPUT ;
    USE SIGNAL ;
    PORT
      LAYER M5 ;
        RECT  77.424 25.728 77.448 25.92 ;
    END
  END o[491]
  PIN o[492]
    DIRECTION OUTPUT ;
    USE SIGNAL ;
    PORT
      LAYER M3 ;
        RECT  77.58 25.776 77.598 25.92 ;
    END
  END o[492]
  PIN o[493]
    DIRECTION OUTPUT ;
    USE SIGNAL ;
    PORT
      LAYER M5 ;
        RECT  77.712 25.728 77.736 25.92 ;
    END
  END o[493]
  PIN o[494]
    DIRECTION OUTPUT ;
    USE SIGNAL ;
    PORT
      LAYER M3 ;
        RECT  77.868 25.776 77.886 25.92 ;
    END
  END o[494]
  PIN o[495]
    DIRECTION OUTPUT ;
    USE SIGNAL ;
    PORT
      LAYER M5 ;
        RECT  78.048 25.728 78.072 25.92 ;
    END
  END o[495]
  PIN o[496]
    DIRECTION OUTPUT ;
    USE SIGNAL ;
    PORT
      LAYER M3 ;
        RECT  78.192 25.776 78.21 25.92 ;
    END
  END o[496]
  PIN o[497]
    DIRECTION OUTPUT ;
    USE SIGNAL ;
    PORT
      LAYER M5 ;
        RECT  78.336 25.728 78.36 25.92 ;
    END
  END o[497]
  PIN o[498]
    DIRECTION OUTPUT ;
    USE SIGNAL ;
    PORT
      LAYER M3 ;
        RECT  78.48 25.776 78.498 25.92 ;
    END
  END o[498]
  PIN o[499]
    DIRECTION OUTPUT ;
    USE SIGNAL ;
    PORT
      LAYER M5 ;
        RECT  78.624 25.728 78.648 25.92 ;
    END
  END o[499]
  PIN o[49]
    DIRECTION OUTPUT ;
    USE SIGNAL ;
    PORT
      LAYER M5 ;
        RECT  9.744 25.728 9.768 25.92 ;
    END
  END o[49]
  PIN o[4]
    DIRECTION OUTPUT ;
    USE SIGNAL ;
    PORT
      LAYER M3 ;
        RECT  2.844 25.776 2.862 25.92 ;
    END
  END o[4]
  PIN o[500]
    DIRECTION OUTPUT ;
    USE SIGNAL ;
    PORT
      LAYER M3 ;
        RECT  78.804 25.776 78.822 25.92 ;
    END
  END o[500]
  PIN o[501]
    DIRECTION OUTPUT ;
    USE SIGNAL ;
    PORT
      LAYER M5 ;
        RECT  78.96 25.728 78.984 25.92 ;
    END
  END o[501]
  PIN o[502]
    DIRECTION OUTPUT ;
    USE SIGNAL ;
    PORT
      LAYER M3 ;
        RECT  79.092 25.776 79.11 25.92 ;
    END
  END o[502]
  PIN o[503]
    DIRECTION OUTPUT ;
    USE SIGNAL ;
    PORT
      LAYER M5 ;
        RECT  79.248 25.728 79.272 25.92 ;
    END
  END o[503]
  PIN o[504]
    DIRECTION OUTPUT ;
    USE SIGNAL ;
    PORT
      LAYER M3 ;
        RECT  79.416 25.776 79.434 25.92 ;
    END
  END o[504]
  PIN o[505]
    DIRECTION OUTPUT ;
    USE SIGNAL ;
    PORT
      LAYER M5 ;
        RECT  79.536 25.728 79.56 25.92 ;
    END
  END o[505]
  PIN o[506]
    DIRECTION OUTPUT ;
    USE SIGNAL ;
    PORT
      LAYER M3 ;
        RECT  79.704 25.776 79.722 25.92 ;
    END
  END o[506]
  PIN o[507]
    DIRECTION OUTPUT ;
    USE SIGNAL ;
    PORT
      LAYER M5 ;
        RECT  79.872 25.728 79.896 25.92 ;
    END
  END o[507]
  PIN o[508]
    DIRECTION OUTPUT ;
    USE SIGNAL ;
    PORT
      LAYER M3 ;
        RECT  80.028 25.776 80.046 25.92 ;
    END
  END o[508]
  PIN o[509]
    DIRECTION OUTPUT ;
    USE SIGNAL ;
    PORT
      LAYER M5 ;
        RECT  80.16 25.728 80.184 25.92 ;
    END
  END o[509]
  PIN o[50]
    DIRECTION OUTPUT ;
    USE SIGNAL ;
    PORT
      LAYER M3 ;
        RECT  9.9 25.776 9.918 25.92 ;
    END
  END o[50]
  PIN o[510]
    DIRECTION OUTPUT ;
    USE SIGNAL ;
    PORT
      LAYER M3 ;
        RECT  80.316 25.776 80.334 25.92 ;
    END
  END o[510]
  PIN o[511]
    DIRECTION OUTPUT ;
    USE SIGNAL ;
    PORT
      LAYER M5 ;
        RECT  80.496 25.728 80.52 25.92 ;
    END
  END o[511]
  PIN o[512]
    DIRECTION OUTPUT ;
    USE SIGNAL ;
    PORT
      LAYER M3 ;
        RECT  80.64 25.776 80.658 25.92 ;
    END
  END o[512]
  PIN o[513]
    DIRECTION OUTPUT ;
    USE SIGNAL ;
    PORT
      LAYER M5 ;
        RECT  80.784 25.728 80.808 25.92 ;
    END
  END o[513]
  PIN o[514]
    DIRECTION OUTPUT ;
    USE SIGNAL ;
    PORT
      LAYER M3 ;
        RECT  80.928 25.776 80.946 25.92 ;
    END
  END o[514]
  PIN o[515]
    DIRECTION OUTPUT ;
    USE SIGNAL ;
    PORT
      LAYER M5 ;
        RECT  81.072 25.728 81.096 25.92 ;
    END
  END o[515]
  PIN o[516]
    DIRECTION OUTPUT ;
    USE SIGNAL ;
    PORT
      LAYER M3 ;
        RECT  81.252 25.776 81.27 25.92 ;
    END
  END o[516]
  PIN o[517]
    DIRECTION OUTPUT ;
    USE SIGNAL ;
    PORT
      LAYER M5 ;
        RECT  81.408 25.728 81.432 25.92 ;
    END
  END o[517]
  PIN o[518]
    DIRECTION OUTPUT ;
    USE SIGNAL ;
    PORT
      LAYER M3 ;
        RECT  81.54 25.776 81.558 25.92 ;
    END
  END o[518]
  PIN o[519]
    DIRECTION OUTPUT ;
    USE SIGNAL ;
    PORT
      LAYER M5 ;
        RECT  81.696 25.728 81.72 25.92 ;
    END
  END o[519]
  PIN o[51]
    DIRECTION OUTPUT ;
    USE SIGNAL ;
    PORT
      LAYER M5 ;
        RECT  10.032 25.728 10.056 25.92 ;
    END
  END o[51]
  PIN o[520]
    DIRECTION OUTPUT ;
    USE SIGNAL ;
    PORT
      LAYER M3 ;
        RECT  81.864 25.776 81.882 25.92 ;
    END
  END o[520]
  PIN o[521]
    DIRECTION OUTPUT ;
    USE SIGNAL ;
    PORT
      LAYER M5 ;
        RECT  81.984 25.728 82.008 25.92 ;
    END
  END o[521]
  PIN o[522]
    DIRECTION OUTPUT ;
    USE SIGNAL ;
    PORT
      LAYER M3 ;
        RECT  82.152 25.776 82.17 25.92 ;
    END
  END o[522]
  PIN o[523]
    DIRECTION OUTPUT ;
    USE SIGNAL ;
    PORT
      LAYER M5 ;
        RECT  82.32 25.728 82.344 25.92 ;
    END
  END o[523]
  PIN o[524]
    DIRECTION OUTPUT ;
    USE SIGNAL ;
    PORT
      LAYER M3 ;
        RECT  82.476 25.776 82.494 25.92 ;
    END
  END o[524]
  PIN o[525]
    DIRECTION OUTPUT ;
    USE SIGNAL ;
    PORT
      LAYER M5 ;
        RECT  82.608 25.728 82.632 25.92 ;
    END
  END o[525]
  PIN o[526]
    DIRECTION OUTPUT ;
    USE SIGNAL ;
    PORT
      LAYER M3 ;
        RECT  82.764 25.776 82.782 25.92 ;
    END
  END o[526]
  PIN o[527]
    DIRECTION OUTPUT ;
    USE SIGNAL ;
    PORT
      LAYER M5 ;
        RECT  82.944 25.728 82.968 25.92 ;
    END
  END o[527]
  PIN o[528]
    DIRECTION OUTPUT ;
    USE SIGNAL ;
    PORT
      LAYER M3 ;
        RECT  83.088 25.776 83.106 25.92 ;
    END
  END o[528]
  PIN o[529]
    DIRECTION OUTPUT ;
    USE SIGNAL ;
    PORT
      LAYER M5 ;
        RECT  83.232 25.728 83.256 25.92 ;
    END
  END o[529]
  PIN o[52]
    DIRECTION OUTPUT ;
    USE SIGNAL ;
    PORT
      LAYER M3 ;
        RECT  10.188 25.776 10.206 25.92 ;
    END
  END o[52]
  PIN o[530]
    DIRECTION OUTPUT ;
    USE SIGNAL ;
    PORT
      LAYER M3 ;
        RECT  83.376 25.776 83.394 25.92 ;
    END
  END o[530]
  PIN o[531]
    DIRECTION OUTPUT ;
    USE SIGNAL ;
    PORT
      LAYER M5 ;
        RECT  83.52 25.728 83.544 25.92 ;
    END
  END o[531]
  PIN o[532]
    DIRECTION OUTPUT ;
    USE SIGNAL ;
    PORT
      LAYER M3 ;
        RECT  83.7 25.776 83.718 25.92 ;
    END
  END o[532]
  PIN o[533]
    DIRECTION OUTPUT ;
    USE SIGNAL ;
    PORT
      LAYER M5 ;
        RECT  83.856 25.728 83.88 25.92 ;
    END
  END o[533]
  PIN o[534]
    DIRECTION OUTPUT ;
    USE SIGNAL ;
    PORT
      LAYER M3 ;
        RECT  83.988 25.776 84.006 25.92 ;
    END
  END o[534]
  PIN o[535]
    DIRECTION OUTPUT ;
    USE SIGNAL ;
    PORT
      LAYER M5 ;
        RECT  84.144 25.728 84.168 25.92 ;
    END
  END o[535]
  PIN o[53]
    DIRECTION OUTPUT ;
    USE SIGNAL ;
    PORT
      LAYER M5 ;
        RECT  10.32 25.728 10.344 25.92 ;
    END
  END o[53]
  PIN o[54]
    DIRECTION OUTPUT ;
    USE SIGNAL ;
    PORT
      LAYER M3 ;
        RECT  10.512 25.776 10.53 25.92 ;
    END
  END o[54]
  PIN o[55]
    DIRECTION OUTPUT ;
    USE SIGNAL ;
    PORT
      LAYER M5 ;
        RECT  10.656 25.728 10.68 25.92 ;
    END
  END o[55]
  PIN o[56]
    DIRECTION OUTPUT ;
    USE SIGNAL ;
    PORT
      LAYER M3 ;
        RECT  10.8 25.776 10.818 25.92 ;
    END
  END o[56]
  PIN o[57]
    DIRECTION OUTPUT ;
    USE SIGNAL ;
    PORT
      LAYER M5 ;
        RECT  10.944 25.728 10.968 25.92 ;
    END
  END o[57]
  PIN o[58]
    DIRECTION OUTPUT ;
    USE SIGNAL ;
    PORT
      LAYER M3 ;
        RECT  11.124 25.776 11.142 25.92 ;
    END
  END o[58]
  PIN o[59]
    DIRECTION OUTPUT ;
    USE SIGNAL ;
    PORT
      LAYER M5 ;
        RECT  11.28 25.728 11.304 25.92 ;
    END
  END o[59]
  PIN o[5]
    DIRECTION OUTPUT ;
    USE SIGNAL ;
    PORT
      LAYER M5 ;
        RECT  2.976 25.728 3 25.92 ;
    END
  END o[5]
  PIN o[60]
    DIRECTION OUTPUT ;
    USE SIGNAL ;
    PORT
      LAYER M3 ;
        RECT  11.412 25.776 11.43 25.92 ;
    END
  END o[60]
  PIN o[61]
    DIRECTION OUTPUT ;
    USE SIGNAL ;
    PORT
      LAYER M5 ;
        RECT  11.568 25.728 11.592 25.92 ;
    END
  END o[61]
  PIN o[62]
    DIRECTION OUTPUT ;
    USE SIGNAL ;
    PORT
      LAYER M3 ;
        RECT  11.736 25.776 11.754 25.92 ;
    END
  END o[62]
  PIN o[63]
    DIRECTION OUTPUT ;
    USE SIGNAL ;
    PORT
      LAYER M5 ;
        RECT  11.856 25.728 11.88 25.92 ;
    END
  END o[63]
  PIN o[64]
    DIRECTION OUTPUT ;
    USE SIGNAL ;
    PORT
      LAYER M3 ;
        RECT  12.024 25.776 12.042 25.92 ;
    END
  END o[64]
  PIN o[65]
    DIRECTION OUTPUT ;
    USE SIGNAL ;
    PORT
      LAYER M5 ;
        RECT  12.192 25.728 12.216 25.92 ;
    END
  END o[65]
  PIN o[66]
    DIRECTION OUTPUT ;
    USE SIGNAL ;
    PORT
      LAYER M3 ;
        RECT  12.348 25.776 12.366 25.92 ;
    END
  END o[66]
  PIN o[67]
    DIRECTION OUTPUT ;
    USE SIGNAL ;
    PORT
      LAYER M5 ;
        RECT  12.48 25.728 12.504 25.92 ;
    END
  END o[67]
  PIN o[68]
    DIRECTION OUTPUT ;
    USE SIGNAL ;
    PORT
      LAYER M3 ;
        RECT  12.636 25.776 12.654 25.92 ;
    END
  END o[68]
  PIN o[69]
    DIRECTION OUTPUT ;
    USE SIGNAL ;
    PORT
      LAYER M5 ;
        RECT  12.768 25.728 12.792 25.92 ;
    END
  END o[69]
  PIN o[6]
    DIRECTION OUTPUT ;
    USE SIGNAL ;
    PORT
      LAYER M3 ;
        RECT  3.132 25.776 3.15 25.92 ;
    END
  END o[6]
  PIN o[70]
    DIRECTION OUTPUT ;
    USE SIGNAL ;
    PORT
      LAYER M3 ;
        RECT  12.96 25.776 12.978 25.92 ;
    END
  END o[70]
  PIN o[71]
    DIRECTION OUTPUT ;
    USE SIGNAL ;
    PORT
      LAYER M5 ;
        RECT  13.104 25.728 13.128 25.92 ;
    END
  END o[71]
  PIN o[72]
    DIRECTION OUTPUT ;
    USE SIGNAL ;
    PORT
      LAYER M3 ;
        RECT  13.248 25.776 13.266 25.92 ;
    END
  END o[72]
  PIN o[73]
    DIRECTION OUTPUT ;
    USE SIGNAL ;
    PORT
      LAYER M5 ;
        RECT  13.392 25.728 13.416 25.92 ;
    END
  END o[73]
  PIN o[74]
    DIRECTION OUTPUT ;
    USE SIGNAL ;
    PORT
      LAYER M3 ;
        RECT  13.572 25.776 13.59 25.92 ;
    END
  END o[74]
  PIN o[75]
    DIRECTION OUTPUT ;
    USE SIGNAL ;
    PORT
      LAYER M5 ;
        RECT  13.728 25.728 13.752 25.92 ;
    END
  END o[75]
  PIN o[76]
    DIRECTION OUTPUT ;
    USE SIGNAL ;
    PORT
      LAYER M3 ;
        RECT  13.86 25.776 13.878 25.92 ;
    END
  END o[76]
  PIN o[77]
    DIRECTION OUTPUT ;
    USE SIGNAL ;
    PORT
      LAYER M5 ;
        RECT  14.016 25.728 14.04 25.92 ;
    END
  END o[77]
  PIN o[78]
    DIRECTION OUTPUT ;
    USE SIGNAL ;
    PORT
      LAYER M3 ;
        RECT  14.184 25.776 14.202 25.92 ;
    END
  END o[78]
  PIN o[79]
    DIRECTION OUTPUT ;
    USE SIGNAL ;
    PORT
      LAYER M5 ;
        RECT  14.304 25.728 14.328 25.92 ;
    END
  END o[79]
  PIN o[7]
    DIRECTION OUTPUT ;
    USE SIGNAL ;
    PORT
      LAYER M5 ;
        RECT  3.312 25.728 3.336 25.92 ;
    END
  END o[7]
  PIN o[80]
    DIRECTION OUTPUT ;
    USE SIGNAL ;
    PORT
      LAYER M3 ;
        RECT  14.472 25.776 14.49 25.92 ;
    END
  END o[80]
  PIN o[81]
    DIRECTION OUTPUT ;
    USE SIGNAL ;
    PORT
      LAYER M5 ;
        RECT  14.64 25.728 14.664 25.92 ;
    END
  END o[81]
  PIN o[82]
    DIRECTION OUTPUT ;
    USE SIGNAL ;
    PORT
      LAYER M3 ;
        RECT  14.796 25.776 14.814 25.92 ;
    END
  END o[82]
  PIN o[83]
    DIRECTION OUTPUT ;
    USE SIGNAL ;
    PORT
      LAYER M5 ;
        RECT  14.928 25.728 14.952 25.92 ;
    END
  END o[83]
  PIN o[84]
    DIRECTION OUTPUT ;
    USE SIGNAL ;
    PORT
      LAYER M3 ;
        RECT  15.084 25.776 15.102 25.92 ;
    END
  END o[84]
  PIN o[85]
    DIRECTION OUTPUT ;
    USE SIGNAL ;
    PORT
      LAYER M5 ;
        RECT  15.264 25.728 15.288 25.92 ;
    END
  END o[85]
  PIN o[86]
    DIRECTION OUTPUT ;
    USE SIGNAL ;
    PORT
      LAYER M3 ;
        RECT  15.408 25.776 15.426 25.92 ;
    END
  END o[86]
  PIN o[87]
    DIRECTION OUTPUT ;
    USE SIGNAL ;
    PORT
      LAYER M5 ;
        RECT  15.552 25.728 15.576 25.92 ;
    END
  END o[87]
  PIN o[88]
    DIRECTION OUTPUT ;
    USE SIGNAL ;
    PORT
      LAYER M3 ;
        RECT  15.696 25.776 15.714 25.92 ;
    END
  END o[88]
  PIN o[89]
    DIRECTION OUTPUT ;
    USE SIGNAL ;
    PORT
      LAYER M5 ;
        RECT  15.84 25.728 15.864 25.92 ;
    END
  END o[89]
  PIN o[8]
    DIRECTION OUTPUT ;
    USE SIGNAL ;
    PORT
      LAYER M3 ;
        RECT  3.456 25.776 3.474 25.92 ;
    END
  END o[8]
  PIN o[90]
    DIRECTION OUTPUT ;
    USE SIGNAL ;
    PORT
      LAYER M3 ;
        RECT  16.02 25.776 16.038 25.92 ;
    END
  END o[90]
  PIN o[91]
    DIRECTION OUTPUT ;
    USE SIGNAL ;
    PORT
      LAYER M5 ;
        RECT  16.176 25.728 16.2 25.92 ;
    END
  END o[91]
  PIN o[92]
    DIRECTION OUTPUT ;
    USE SIGNAL ;
    PORT
      LAYER M3 ;
        RECT  16.308 25.776 16.326 25.92 ;
    END
  END o[92]
  PIN o[93]
    DIRECTION OUTPUT ;
    USE SIGNAL ;
    PORT
      LAYER M5 ;
        RECT  16.464 25.728 16.488 25.92 ;
    END
  END o[93]
  PIN o[94]
    DIRECTION OUTPUT ;
    USE SIGNAL ;
    PORT
      LAYER M3 ;
        RECT  16.632 25.776 16.65 25.92 ;
    END
  END o[94]
  PIN o[95]
    DIRECTION OUTPUT ;
    USE SIGNAL ;
    PORT
      LAYER M5 ;
        RECT  16.752 25.728 16.776 25.92 ;
    END
  END o[95]
  PIN o[96]
    DIRECTION OUTPUT ;
    USE SIGNAL ;
    PORT
      LAYER M3 ;
        RECT  16.92 25.776 16.938 25.92 ;
    END
  END o[96]
  PIN o[97]
    DIRECTION OUTPUT ;
    USE SIGNAL ;
    PORT
      LAYER M5 ;
        RECT  17.088 25.728 17.112 25.92 ;
    END
  END o[97]
  PIN o[98]
    DIRECTION OUTPUT ;
    USE SIGNAL ;
    PORT
      LAYER M3 ;
        RECT  17.244 25.776 17.262 25.92 ;
    END
  END o[98]
  PIN o[99]
    DIRECTION OUTPUT ;
    USE SIGNAL ;
    PORT
      LAYER M5 ;
        RECT  17.376 25.728 17.4 25.92 ;
    END
  END o[99]
  PIN o[9]
    DIRECTION OUTPUT ;
    USE SIGNAL ;
    PORT
      LAYER M5 ;
        RECT  3.6 25.728 3.624 25.92 ;
    END
  END o[9]
  PIN rs
    DIRECTION INPUT ;
    USE SIGNAL ;
    PORT
      LAYER M4 ;
        RECT  0 13.968 0.192 13.992 ;
    END
  END rs
  PIN VDD
    DIRECTION INOUT ;
    USE POWER ;
    PORT
      LAYER M5 ;
        RECT  83.592 2.151 83.712 23.769 ;
        RECT  80.892 2.151 81.012 23.769 ;
        RECT  78.192 2.151 78.312 23.769 ;
        RECT  75.492 2.151 75.612 23.769 ;
        RECT  72.792 2.151 72.912 23.769 ;
        RECT  70.092 2.151 70.212 23.769 ;
        RECT  67.392 2.151 67.512 23.769 ;
        RECT  64.692 2.151 64.812 23.769 ;
        RECT  61.992 2.151 62.112 23.769 ;
        RECT  59.292 2.151 59.412 23.769 ;
        RECT  56.592 2.151 56.712 23.769 ;
        RECT  53.892 2.151 54.012 23.769 ;
        RECT  51.192 2.151 51.312 23.769 ;
        RECT  48.492 2.151 48.612 23.769 ;
        RECT  45.792 2.151 45.912 23.769 ;
        RECT  43.092 2.151 43.212 23.769 ;
        RECT  40.392 2.151 40.512 23.769 ;
        RECT  37.692 2.151 37.812 23.769 ;
        RECT  34.992 2.151 35.112 23.769 ;
        RECT  32.292 2.151 32.412 23.769 ;
        RECT  29.592 2.151 29.712 23.769 ;
        RECT  26.892 2.151 27.012 23.769 ;
        RECT  24.192 2.151 24.312 23.769 ;
        RECT  21.492 2.151 21.612 23.769 ;
        RECT  18.792 2.151 18.912 23.769 ;
        RECT  16.092 2.151 16.212 23.769 ;
        RECT  13.392 2.151 13.512 23.769 ;
        RECT  10.692 2.151 10.812 23.769 ;
        RECT  7.992 2.151 8.112 23.769 ;
        RECT  5.292 2.151 5.412 23.769 ;
        RECT  2.592 2.151 2.712 23.769 ;
    END
  END VDD
  PIN VSS
    DIRECTION INOUT ;
    USE GROUND ;
    PORT
      LAYER M5 ;
        RECT  83.4 2.137 83.52 23.783 ;
        RECT  80.7 2.137 80.82 23.783 ;
        RECT  78 2.137 78.12 23.783 ;
        RECT  75.3 2.137 75.42 23.783 ;
        RECT  72.6 2.137 72.72 23.783 ;
        RECT  69.9 2.137 70.02 23.783 ;
        RECT  67.2 2.137 67.32 23.783 ;
        RECT  64.5 2.137 64.62 23.783 ;
        RECT  61.8 2.137 61.92 23.783 ;
        RECT  59.1 2.137 59.22 23.783 ;
        RECT  56.4 2.137 56.52 23.783 ;
        RECT  53.7 2.137 53.82 23.783 ;
        RECT  51 2.137 51.12 23.783 ;
        RECT  48.3 2.137 48.42 23.783 ;
        RECT  45.6 2.137 45.72 23.783 ;
        RECT  42.9 2.137 43.02 23.783 ;
        RECT  40.2 2.137 40.32 23.783 ;
        RECT  37.5 2.137 37.62 23.783 ;
        RECT  34.8 2.137 34.92 23.783 ;
        RECT  32.1 2.137 32.22 23.783 ;
        RECT  29.4 2.137 29.52 23.783 ;
        RECT  26.7 2.137 26.82 23.783 ;
        RECT  24 2.137 24.12 23.783 ;
        RECT  21.3 2.137 21.42 23.783 ;
        RECT  18.6 2.137 18.72 23.783 ;
        RECT  15.9 2.137 16.02 23.783 ;
        RECT  13.2 2.137 13.32 23.783 ;
        RECT  10.5 2.137 10.62 23.783 ;
        RECT  7.8 2.137 7.92 23.783 ;
        RECT  5.1 2.137 5.22 23.783 ;
        RECT  2.4 2.137 2.52 23.783 ;
    END
  END VSS
  OBS
    LAYER RVTN ;
     RECT  2.16 2.16 84.24 2.295 ;
     RECT  2.16 2.565 84.24 2.835 ;
     RECT  2.16 3.105 84.24 3.375 ;
     RECT  2.16 3.645 84.24 3.915 ;
     RECT  2.16 4.185 84.24 4.455 ;
     RECT  2.16 4.725 84.24 4.995 ;
     RECT  2.16 5.265 84.24 5.535 ;
     RECT  2.16 5.805 84.24 6.075 ;
     RECT  2.16 6.345 84.24 6.615 ;
     RECT  2.16 6.885 84.24 7.155 ;
     RECT  2.16 7.425 84.24 7.695 ;
     RECT  2.16 7.965 84.24 8.235 ;
     RECT  2.16 8.505 84.24 8.775 ;
     RECT  2.16 9.045 84.24 9.315 ;
     RECT  2.16 9.585 84.24 9.855 ;
     RECT  2.16 10.125 84.24 10.395 ;
     RECT  2.16 10.665 84.24 10.935 ;
     RECT  2.16 11.205 84.24 11.475 ;
     RECT  2.16 11.745 84.24 12.015 ;
     RECT  2.16 12.285 84.24 12.555 ;
     RECT  2.16 12.825 84.24 13.095 ;
     RECT  2.16 13.365 84.24 13.635 ;
     RECT  2.16 13.905 84.24 14.175 ;
     RECT  2.16 14.445 84.24 14.715 ;
     RECT  2.16 14.985 84.24 15.255 ;
     RECT  2.16 15.525 84.24 15.795 ;
     RECT  2.16 16.065 84.24 16.335 ;
     RECT  2.16 16.605 84.24 16.875 ;
     RECT  2.16 17.145 84.24 17.415 ;
     RECT  2.16 17.685 84.24 17.955 ;
     RECT  2.16 18.225 84.24 18.495 ;
     RECT  2.16 18.765 84.24 19.035 ;
     RECT  2.16 19.305 84.24 19.575 ;
     RECT  2.16 19.845 84.24 20.115 ;
     RECT  2.16 20.385 84.24 20.655 ;
     RECT  2.16 20.925 84.24 21.195 ;
     RECT  2.16 21.465 84.24 21.735 ;
     RECT  2.16 22.005 84.24 22.275 ;
     RECT  2.16 22.545 84.24 22.815 ;
     RECT  2.16 23.085 84.24 23.355 ;
     RECT  2.16 23.625 84.24 23.76 ;
    LAYER RVTP ;
     RECT  2.16 2.295 84.24 2.565 ;
     RECT  2.16 2.835 84.24 3.105 ;
     RECT  2.16 3.375 84.24 3.645 ;
     RECT  2.16 3.915 84.24 4.185 ;
     RECT  2.16 4.455 84.24 4.725 ;
     RECT  2.16 4.995 84.24 5.265 ;
     RECT  2.16 5.535 84.24 5.805 ;
     RECT  2.16 6.075 84.24 6.345 ;
     RECT  2.16 6.615 84.24 6.885 ;
     RECT  2.16 7.155 84.24 7.425 ;
     RECT  2.16 7.695 84.24 7.965 ;
     RECT  2.16 8.235 84.24 8.505 ;
     RECT  2.16 8.775 84.24 9.045 ;
     RECT  2.16 9.315 84.24 9.585 ;
     RECT  2.16 9.855 84.24 10.125 ;
     RECT  2.16 10.395 84.24 10.665 ;
     RECT  2.16 10.935 84.24 11.205 ;
     RECT  2.16 11.475 84.24 11.745 ;
     RECT  2.16 12.015 84.24 12.285 ;
     RECT  2.16 12.555 84.24 12.825 ;
     RECT  2.16 13.095 84.24 13.365 ;
     RECT  2.16 13.635 84.24 13.905 ;
     RECT  2.16 14.175 84.24 14.445 ;
     RECT  2.16 14.715 84.24 14.985 ;
     RECT  2.16 15.255 84.24 15.525 ;
     RECT  2.16 15.795 84.24 16.065 ;
     RECT  2.16 16.335 84.24 16.605 ;
     RECT  2.16 16.875 84.24 17.145 ;
     RECT  2.16 17.415 84.24 17.685 ;
     RECT  2.16 17.955 84.24 18.225 ;
     RECT  2.16 18.495 84.24 18.765 ;
     RECT  2.16 19.035 84.24 19.305 ;
     RECT  2.16 19.575 84.24 19.845 ;
     RECT  2.16 20.115 84.24 20.385 ;
     RECT  2.16 20.655 84.24 20.925 ;
     RECT  2.16 21.195 84.24 21.465 ;
     RECT  2.16 21.735 84.24 22.005 ;
     RECT  2.16 22.275 84.24 22.545 ;
     RECT  2.16 22.815 84.24 23.085 ;
     RECT  2.16 23.355 84.24 23.625 ;
    LAYER M1 ;
     RECT  2.16 2.151 84.24 23.769 ;
    LAYER M2 ;
     RECT  2.16 2.151 2.371 23.769 ;
     RECT  2.371 2.151 2.543 23.85 ;
     RECT  2.515 0.144 2.759 0.162 ;
     RECT  2.543 2.151 3.335 23.814 ;
     RECT  3.335 2.151 4.063 23.769 ;
     RECT  4.207 0.144 4.379 0.162 ;
     RECT  4.063 2.151 6.079 23.814 ;
     RECT  6.079 2.151 6.215 23.886 ;
     RECT  6.215 2.151 7.123 23.814 ;
     RECT  7.123 2.151 7.403 23.886 ;
     RECT  7.403 2.151 7.627 23.814 ;
     RECT  7.627 2.106 7.979 23.814 ;
     RECT  8.059 0.144 8.447 0.162 ;
     RECT  7.979 2.106 8.735 23.769 ;
     RECT  8.735 2.151 9.283 23.769 ;
     RECT  9.283 2.151 10.507 23.814 ;
     RECT  10.435 0.144 10.535 0.162 ;
     RECT  10.507 2.151 10.723 23.886 ;
     RECT  10.723 2.151 10.823 23.958 ;
     RECT  11.659 0.144 12.119 0.162 ;
     RECT  10.823 2.151 12.343 23.814 ;
     RECT  12.343 2.151 13.135 23.886 ;
     RECT  13.135 2.151 13.271 23.958 ;
     RECT  13.271 2.151 13.567 23.85 ;
     RECT  13.243 0.144 13.667 0.162 ;
     RECT  13.567 1.728 13.703 23.85 ;
     RECT  13.703 2.151 14.467 23.85 ;
     RECT  14.467 2.151 14.683 23.886 ;
     RECT  14.719 0.144 14.819 0.162 ;
     RECT  14.683 2.151 14.819 23.958 ;
     RECT  14.819 2.151 16.015 23.814 ;
     RECT  16.015 0.144 16.259 0.162 ;
     RECT  16.015 2.151 16.303 23.85 ;
     RECT  16.303 1.728 16.475 23.85 ;
     RECT  16.475 1.728 17.483 23.814 ;
     RECT  17.483 1.728 17.555 23.769 ;
     RECT  17.555 2.151 18.571 23.769 ;
     RECT  18.247 0.144 18.779 0.162 ;
     RECT  18.571 2.151 18.779 23.994 ;
     RECT  18.779 2.151 19.391 23.958 ;
     RECT  21.523 0.144 21.659 0.162 ;
     RECT  19.391 2.151 23.035 23.769 ;
     RECT  23.035 2.151 23.971 23.814 ;
     RECT  23.971 2.151 24.871 23.886 ;
     RECT  24.871 2.151 24.971 24.039 ;
     RECT  24.971 2.151 25.807 23.814 ;
     RECT  25.807 2.151 26.231 23.886 ;
     RECT  26.231 2.151 26.735 23.85 ;
     RECT  26.635 0.144 27.347 0.162 ;
     RECT  26.735 2.151 28.255 23.769 ;
     RECT  28.255 2.151 28.867 23.814 ;
     RECT  28.867 2.151 29.003 23.886 ;
     RECT  29.003 2.151 29.507 23.85 ;
     RECT  28.867 0.144 29.579 0.162 ;
     RECT  29.507 2.151 30.415 23.814 ;
     RECT  30.415 1.728 30.983 23.814 ;
     RECT  30.983 2.151 31.207 23.814 ;
     RECT  31.207 2.151 31.639 23.85 ;
     RECT  31.639 2.151 32.251 23.886 ;
     RECT  32.251 2.151 32.495 23.994 ;
     RECT  32.539 0.144 32.963 0.162 ;
     RECT  32.495 2.151 34.375 23.769 ;
     RECT  34.375 2.151 34.987 23.814 ;
     RECT  34.987 2.151 35.311 23.85 ;
     RECT  35.311 2.151 36.203 23.922 ;
     RECT  36.535 0.144 36.815 0.162 ;
     RECT  36.203 2.151 37.031 23.814 ;
     RECT  37.031 2.151 37.759 23.769 ;
     RECT  37.759 0.144 37.859 0.162 ;
     RECT  37.759 2.151 38.147 23.814 ;
     RECT  38.147 2.151 40.207 23.769 ;
     RECT  40.207 0.144 40.379 0.162 ;
     RECT  40.207 2.151 40.379 23.85 ;
     RECT  40.379 2.151 41.107 23.769 ;
     RECT  41.107 2.151 42.071 23.814 ;
     RECT  42.043 0.144 42.143 0.162 ;
     RECT  42.071 2.151 42.943 23.769 ;
     RECT  42.943 2.151 43.267 23.85 ;
     RECT  43.267 2.151 44.627 23.922 ;
     RECT  44.627 2.151 45.391 23.769 ;
     RECT  45.391 2.151 45.715 23.814 ;
     RECT  45.715 2.151 46.003 23.85 ;
     RECT  45.715 0.144 46.175 0.162 ;
     RECT  46.003 2.151 46.175 23.922 ;
     RECT  46.939 0.144 47.039 0.162 ;
     RECT  46.175 2.151 47.839 23.814 ;
     RECT  47.839 2.151 48.731 23.886 ;
     RECT  48.731 2.151 50.711 23.814 ;
     RECT  50.971 1.152 51.179 1.17 ;
     RECT  51.151 0.144 51.647 0.162 ;
     RECT  50.711 2.151 52.159 23.769 ;
     RECT  52.159 2.151 53.383 23.814 ;
     RECT  53.383 2.151 53.483 23.886 ;
     RECT  53.483 2.151 54.131 23.814 ;
     RECT  53.851 0.144 54.635 0.162 ;
     RECT  54.131 2.151 56.443 23.769 ;
     RECT  56.443 2.151 56.731 23.85 ;
     RECT  56.731 2.151 57.191 23.922 ;
     RECT  57.191 2.151 58.055 23.814 ;
     RECT  58.055 2.151 59.179 23.769 ;
     RECT  59.179 0.144 59.279 0.162 ;
     RECT  59.071 1.152 59.279 1.17 ;
     RECT  59.179 2.151 59.999 23.85 ;
     RECT  59.999 2.151 61.627 23.769 ;
     RECT  61.627 0.144 61.727 0.162 ;
     RECT  61.627 2.151 61.951 23.814 ;
     RECT  61.951 2.151 62.159 23.994 ;
     RECT  62.159 2.151 62.699 23.814 ;
     RECT  63.103 1.152 63.175 1.17 ;
     RECT  63.175 1.152 63.275 1.242 ;
     RECT  64.075 0.144 64.175 0.162 ;
     RECT  62.699 2.151 64.687 23.769 ;
     RECT  65.623 0.144 65.723 0.162 ;
     RECT  64.687 2.151 68.207 23.814 ;
     RECT  67.459 0.144 68.387 0.162 ;
     RECT  68.207 2.151 69.007 23.769 ;
     RECT  69.007 2.151 69.619 23.814 ;
     RECT  69.619 2.151 69.763 23.85 ;
     RECT  69.835 0.144 69.871 0.162 ;
     RECT  69.871 0.144 69.935 0.594 ;
     RECT  69.763 2.151 69.935 23.922 ;
     RECT  69.935 0.576 70.259 0.594 ;
     RECT  69.935 2.151 70.655 23.886 ;
     RECT  70.655 2.151 71.455 23.769 ;
     RECT  71.455 2.151 72.391 23.814 ;
     RECT  72.391 2.106 72.679 23.814 ;
     RECT  72.535 0.144 72.707 0.162 ;
     RECT  72.679 2.106 72.923 23.85 ;
     RECT  72.923 2.151 73.291 23.85 ;
     RECT  73.291 2.151 73.579 23.922 ;
     RECT  73.579 2.151 73.679 23.994 ;
     RECT  73.679 2.151 74.147 23.922 ;
     RECT  74.147 2.151 74.687 23.886 ;
     RECT  74.687 2.151 75.127 23.814 ;
     RECT  75.127 2.106 75.415 23.814 ;
     RECT  75.271 0.144 75.443 0.162 ;
     RECT  75.415 2.106 75.659 23.85 ;
     RECT  75.659 2.106 75.739 23.814 ;
     RECT  75.739 1.728 76.307 23.814 ;
     RECT  76.307 2.151 76.963 23.814 ;
     RECT  76.963 2.151 77.963 23.886 ;
     RECT  77.963 2.151 78.151 23.814 ;
     RECT  77.575 0.144 78.359 0.162 ;
     RECT  78.151 2.106 78.475 23.814 ;
     RECT  78.475 1.728 78.539 23.814 ;
     RECT  78.539 1.728 78.791 23.769 ;
     RECT  78.791 2.151 80.023 23.769 ;
     RECT  80.023 2.151 80.491 23.814 ;
     RECT  80.671 0.144 80.951 0.162 ;
     RECT  80.491 2.151 80.951 23.994 ;
     RECT  80.951 2.151 81.383 23.814 ;
     RECT  81.383 2.151 82.147 23.769 ;
     RECT  82.471 0.144 82.571 0.162 ;
     RECT  82.147 2.151 82.895 23.814 ;
     RECT  83.083 24.606 83.183 24.624 ;
     RECT  83.263 25.182 83.399 25.2 ;
     RECT  83.551 0.144 83.723 0.162 ;
     RECT  82.895 2.151 84.24 23.769 ;
    LAYER M3 ;
     RECT  2.232 0.108 84.006 0.173 ;
     RECT  2.232 0.173 38.682 0.317 ;
     RECT  20.304 0.317 38.682 0.557 ;
     RECT  46.152 0.173 84.006 0.557 ;
     RECT  2.232 0.317 19.386 1.723 ;
     RECT  20.592 0.557 38.682 1.723 ;
     RECT  48.168 0.557 56.142 1.723 ;
     RECT  57.348 0.557 84.006 1.723 ;
     RECT  57.204 1.723 84.006 1.819 ;
     RECT  39.6 0.173 45.126 2.143 ;
     RECT  46.152 0.557 47.25 2.143 ;
     RECT  48.168 1.723 56.358 2.143 ;
     RECT  57.168 1.819 84.006 2.143 ;
     RECT  2.232 1.723 38.682 2.191 ;
     RECT  39.6 2.143 47.25 2.191 ;
     RECT  2.232 2.191 47.25 2.251 ;
     RECT  48.168 2.143 84.006 2.251 ;
     RECT  2.232 2.251 84.006 2.461 ;
     RECT  2.232 2.461 84.042 2.525 ;
     RECT  2.376 2.525 84.042 2.795 ;
     RECT  2.415 2.795 84.042 3.181 ;
     RECT  2.415 3.181 84.114 3.541 ;
     RECT  2.415 3.541 84.15 3.721 ;
     RECT  2.376 3.721 84.15 4.289 ;
     RECT  2.415 4.289 84.15 7.321 ;
     RECT  2.415 7.321 84.186 7.619 ;
     RECT  28.188 7.619 84.186 7.763 ;
     RECT  2.415 7.619 27.342 8.671 ;
     RECT  28.224 7.763 84.186 8.671 ;
     RECT  2.415 8.671 84.186 9.779 ;
     RECT  44.172 9.779 84.186 10.769 ;
     RECT  2.415 9.779 43.434 13.441 ;
     RECT  44.172 10.769 84.042 13.441 ;
     RECT  2.415 13.441 84.042 13.837 ;
     RECT  2.268 13.837 84.042 13.997 ;
     RECT  2.304 13.997 84.042 14.135 ;
     RECT  2.415 14.135 84.042 16.141 ;
     RECT  2.415 16.141 84.15 23.053 ;
     RECT  2.232 23.053 84.15 23.351 ;
     RECT  2.232 23.351 84.078 25.133 ;
     RECT  2.232 25.133 84.006 25.788 ;
    LAYER M4 ;
     RECT  0.156 12.96 0.275 12.984 ;
     RECT  2.365 1.776 2.408 1.8 ;
     RECT  0.229 6.576 2.408 6.6 ;
     RECT  0.156 13.968 2.408 13.992 ;
     RECT  2.389 23.904 2.408 23.928 ;
     RECT  2.408 1.776 2.704 23.928 ;
     RECT  2.704 23.376 2.837 23.928 ;
     RECT  2.704 1.776 2.933 1.8 ;
     RECT  2.704 4.272 3.701 6.84 ;
     RECT  2.965 25.104 3.845 25.128 ;
     RECT  2.933 1.728 3.953 1.8 ;
     RECT  2.837 23.376 4.213 23.4 ;
     RECT  3.589 0.192 4.259 0.216 ;
     RECT  3.953 1.728 4.381 1.752 ;
     RECT  4.381 1.152 4.883 1.752 ;
     RECT  4.883 1.728 5.108 1.752 ;
     RECT  3.701 4.272 5.108 5.16 ;
     RECT  3.701 6.576 5.108 6.84 ;
     RECT  4.213 23.376 5.108 23.976 ;
     RECT  5.108 1.728 5.125 23.976 ;
     RECT  5.125 1.728 5.404 24.552 ;
     RECT  5.404 23.376 5.465 24.552 ;
     RECT  5.413 0.192 5.501 0.216 ;
     RECT  5.404 4.512 6.401 7.464 ;
     RECT  5.465 23.376 6.509 23.976 ;
     RECT  5.404 1.728 6.652 1.752 ;
     RECT  6.401 4.512 6.785 6.6 ;
     RECT  5.404 2.88 7.081 2.904 ;
     RECT  7.081 2.88 7.369 3 ;
     RECT  6.785 4.464 7.369 6.6 ;
     RECT  6.652 1.728 7.532 1.8 ;
     RECT  7.369 2.88 7.532 6.6 ;
     RECT  7.532 1.728 7.573 6.6 ;
     RECT  6.509 23.376 7.573 23.736 ;
     RECT  7.513 14.256 7.621 14.28 ;
     RECT  7.573 23.376 7.805 24.552 ;
     RECT  7.573 1.728 7.808 6.936 ;
     RECT  7.649 13.104 7.808 13.128 ;
     RECT  7.621 14.256 7.808 14.664 ;
     RECT  7.805 23.376 7.808 23.928 ;
     RECT  7.808 1.728 7.907 23.928 ;
     RECT  7.907 1.728 7.912 23.772 ;
     RECT  7.912 1.728 8.104 23.688 ;
     RECT  8.104 2.88 8.201 6.6 ;
     RECT  8.201 2.88 8.291 3.336 ;
     RECT  8.104 12.528 8.317 12.552 ;
     RECT  8.291 2.88 8.813 2.904 ;
     RECT  9.109 0.576 9.209 0.6 ;
     RECT  9.157 7.584 9.244 7.608 ;
     RECT  8.104 23.376 9.397 23.688 ;
     RECT  8.201 4.512 9.637 6.6 ;
     RECT  8.104 1.728 9.709 1.752 ;
     RECT  9.397 23.376 10.309 23.736 ;
     RECT  9.733 25.104 10.309 25.128 ;
     RECT  9.709 1.728 10.357 2.328 ;
     RECT  10.357 1.632 10.508 3.048 ;
     RECT  9.637 4.512 10.508 7.416 ;
     RECT  10.309 23.376 10.508 25.128 ;
     RECT  10.508 1.632 10.721 25.128 ;
     RECT  10.721 1.632 10.804 23.736 ;
     RECT  10.804 1.632 10.829 2.28 ;
     RECT  10.804 5.376 10.901 7.416 ;
     RECT  10.829 1.728 10.979 2.28 ;
     RECT  10.721 25.104 11.333 25.128 ;
     RECT  10.804 23.712 11.405 23.736 ;
     RECT  10.804 22.656 11.845 22.68 ;
     RECT  10.901 5.376 12.017 6.888 ;
     RECT  10.979 1.728 12.157 1.752 ;
     RECT  12.157 1.152 12.241 1.752 ;
     RECT  10.804 4.224 12.409 4.248 ;
     RECT  12.017 5.376 12.409 6.84 ;
     RECT  11.845 22.656 12.469 23.4 ;
     RECT  12.469 22.656 12.757 23.448 ;
     RECT  12.757 22.656 13.093 23.592 ;
     RECT  12.241 1.728 13.208 1.752 ;
     RECT  12.409 3.984 13.208 6.84 ;
     RECT  13.093 22.656 13.208 24.552 ;
     RECT  13.208 1.728 13.457 24.552 ;
     RECT  13.457 1.728 13.504 23.88 ;
     RECT  13.504 1.728 13.565 7.464 ;
     RECT  13.565 3.312 13.667 7.464 ;
     RECT  13.504 13.296 13.667 13.32 ;
     RECT  13.504 23.376 13.673 23.88 ;
     RECT  13.673 23.376 14.249 23.592 ;
     RECT  13.667 4.272 14.537 7.464 ;
     RECT  14.537 4.272 14.645 6.6 ;
     RECT  14.249 23.424 14.917 23.592 ;
     RECT  14.917 23.424 15.253 23.736 ;
     RECT  14.645 4.272 15.469 4.536 ;
     RECT  15.253 23.376 15.541 23.736 ;
     RECT  15.541 23.376 15.797 24.552 ;
     RECT  15.733 2.88 15.829 2.904 ;
     RECT  15.469 4.176 15.829 4.536 ;
     RECT  13.565 1.728 15.908 1.752 ;
     RECT  15.829 2.88 15.908 4.536 ;
     RECT  14.645 6 15.908 6.6 ;
     RECT  15.649 10.752 15.908 10.776 ;
     RECT  15.797 23.376 15.908 23.976 ;
     RECT  15.908 1.728 16.204 23.976 ;
     RECT  16.204 1.728 16.355 2.232 ;
     RECT  15.733 0.192 16.403 0.216 ;
     RECT  16.204 3.408 16.625 6.6 ;
     RECT  16.204 23.376 16.985 23.976 ;
     RECT  16.355 1.728 17.161 1.752 ;
     RECT  16.625 3.936 17.405 6.6 ;
     RECT  17.161 0.528 17.411 1.752 ;
     RECT  17.411 1.728 17.413 1.752 ;
     RECT  17.413 1.728 17.453 2.232 ;
     RECT  17.405 3.936 17.489 7.464 ;
     RECT  16.985 23.376 17.633 23.544 ;
     RECT  17.453 2.208 17.66 2.232 ;
     RECT  17.633 23.376 17.737 23.448 ;
     RECT  17.489 3.936 17.809 7.368 ;
     RECT  17.411 0.528 18.173 0.552 ;
     RECT  17.989 24.528 18.209 24.552 ;
     RECT  17.737 22.896 18.277 23.448 ;
     RECT  18.277 0.192 18.361 0.216 ;
     RECT  17.66 2.208 18.449 2.28 ;
     RECT  17.809 3.408 18.449 7.368 ;
     RECT  18.449 2.208 18.529 7.368 ;
     RECT  18.529 2.016 18.608 7.368 ;
     RECT  18.277 22.8 18.608 23.448 ;
     RECT  18.608 2.016 18.881 23.928 ;
     RECT  18.881 1.728 18.904 23.928 ;
     RECT  18.904 23.712 19.525 23.928 ;
     RECT  19.525 23.712 19.793 24.552 ;
     RECT  19.793 23.712 19.937 23.736 ;
     RECT  19.681 0.288 19.964 0.312 ;
     RECT  18.904 1.728 20.012 1.752 ;
     RECT  18.904 2.832 20.012 7.368 ;
     RECT  19.964 0.144 20.051 0.312 ;
     RECT  20.149 14.256 20.233 14.28 ;
     RECT  20.245 0.528 20.333 0.552 ;
     RECT  20.149 23.472 20.396 23.496 ;
     RECT  20.012 1.728 20.405 7.368 ;
     RECT  20.405 1.776 20.513 7.368 ;
     RECT  20.396 23.376 21.193 23.496 ;
     RECT  20.513 2.148 21.308 7.368 ;
     RECT  20.485 12.528 21.308 12.552 ;
     RECT  21.193 23.376 21.308 23.592 ;
     RECT  21.308 2.148 21.349 23.772 ;
     RECT  21.349 2.148 21.604 23.928 ;
     RECT  21.157 0.192 21.737 0.216 ;
     RECT  21.604 2.148 21.737 4.776 ;
     RECT  21.737 2.148 21.881 3.912 ;
     RECT  21.881 2.148 21.973 2.328 ;
     RECT  21.604 23.376 22.261 23.928 ;
     RECT  21.604 6.288 22.604 7.368 ;
     RECT  21.881 3.36 22.745 3.912 ;
     RECT  22.849 13.104 22.933 13.128 ;
     RECT  22.604 5.616 23.029 7.368 ;
     RECT  23.029 5.04 23.137 7.368 ;
     RECT  22.412 0.144 23.692 0.168 ;
     RECT  21.973 1.728 23.749 2.328 ;
     RECT  22.745 3.408 23.749 3.912 ;
     RECT  22.261 23.376 23.965 23.976 ;
     RECT  23.749 1.728 24.008 3.912 ;
     RECT  23.137 4.944 24.008 7.368 ;
     RECT  23.929 12.528 24.008 12.552 ;
     RECT  23.245 14.592 24.008 14.616 ;
     RECT  23.965 22.8 24.008 23.976 ;
     RECT  24.008 1.728 24.304 23.976 ;
     RECT  24.304 12.528 24.419 12.552 ;
     RECT  24.304 23.376 24.467 23.976 ;
     RECT  24.467 23.712 24.905 23.976 ;
     RECT  24.304 1.728 25.121 7.368 ;
     RECT  25.148 0.144 25.235 0.168 ;
     RECT  24.905 23.712 25.58 23.832 ;
     RECT  25.121 1.728 26.233 2.28 ;
     RECT  25.58 23.376 26.245 23.832 ;
     RECT  26.233 1.728 26.581 2.328 ;
     RECT  25.121 3.696 26.581 7.368 ;
     RECT  26.581 1.728 26.708 7.368 ;
     RECT  26.245 23.376 26.708 23.88 ;
     RECT  26.708 1.728 26.869 23.88 ;
     RECT  26.869 1.728 27.004 23.976 ;
     RECT  27.004 1.728 27.203 7.368 ;
     RECT  27.004 23.376 27.209 23.976 ;
     RECT  27.203 1.728 27.245 7.08 ;
     RECT  27.209 23.376 28.693 23.736 ;
     RECT  27.245 1.728 28.897 1.752 ;
     RECT  27.245 2.736 28.897 7.08 ;
     RECT  28.693 23.376 29.317 23.88 ;
     RECT  28.897 1.728 29.408 7.08 ;
     RECT  29.317 23.376 29.408 23.928 ;
     RECT  29.408 1.728 29.584 23.928 ;
     RECT  29.269 0.288 29.651 0.312 ;
     RECT  29.584 1.728 29.704 23.976 ;
     RECT  29.704 23.856 29.729 23.976 ;
     RECT  29.704 1.728 30.188 6.936 ;
     RECT  30.188 1.68 30.275 6.936 ;
     RECT  30.275 1.728 30.521 6.936 ;
     RECT  29.729 23.904 30.565 23.976 ;
     RECT  30.521 2.256 30.745 6.936 ;
     RECT  30.565 23.904 30.853 24.072 ;
     RECT  30.745 2.304 31.061 6.936 ;
     RECT  30.853 23.904 31.133 24.552 ;
     RECT  31.133 23.904 31.141 23.928 ;
     RECT  31.141 23.712 31.765 23.928 ;
     RECT  31.861 0.528 31.957 0.552 ;
     RECT  31.957 0.192 31.961 0.552 ;
     RECT  31.061 2.304 32.029 5.208 ;
     RECT  31.061 6.192 32.029 6.936 ;
     RECT  31.961 0.192 32.099 0.216 ;
     RECT  32.029 2.304 32.108 6.936 ;
     RECT  31.453 12.528 32.108 12.552 ;
     RECT  31.765 23.376 32.108 23.928 ;
     RECT  32.108 2.148 32.285 23.928 ;
     RECT  32.285 2.148 32.381 23.88 ;
     RECT  32.381 2.016 32.404 23.88 ;
     RECT  32.404 2.016 32.465 7.032 ;
     RECT  32.404 22.704 32.476 23.88 ;
     RECT  32.404 14.256 33.041 14.28 ;
     RECT  32.465 2.832 33.059 7.032 ;
     RECT  33.059 3.936 33.085 7.032 ;
     RECT  32.476 22.704 33.257 23.448 ;
     RECT  32.677 1.728 33.541 1.752 ;
     RECT  33.059 2.832 33.541 2.856 ;
     RECT  33.257 22.992 33.635 23.448 ;
     RECT  33.085 3.936 34.153 6.936 ;
     RECT  33.541 1.728 34.165 2.856 ;
     RECT  34.153 3.936 34.165 7.32 ;
     RECT  34.364 0.144 34.451 0.168 ;
     RECT  34.165 1.728 34.547 7.32 ;
     RECT  34.213 24.528 34.589 24.552 ;
     RECT  34.547 1.824 34.808 7.32 ;
     RECT  33.635 22.992 34.808 23.4 ;
     RECT  34.808 1.824 34.985 23.928 ;
     RECT  34.985 2.208 35.104 23.928 ;
     RECT  34.981 0.192 35.219 0.312 ;
     RECT  35.104 13.68 35.219 14.856 ;
     RECT  35.104 22.512 35.237 23.928 ;
     RECT  35.104 2.208 35.315 7.032 ;
     RECT  35.104 10.8 35.363 10.824 ;
     RECT  35.219 14.256 35.417 14.856 ;
     RECT  35.219 0.192 35.524 0.216 ;
     RECT  35.524 0.144 35.525 0.216 ;
     RECT  35.461 25.104 35.777 25.128 ;
     RECT  35.237 22.512 35.957 23.736 ;
     RECT  35.525 0.144 36.275 0.168 ;
     RECT  35.315 2.208 36.277 2.328 ;
     RECT  35.315 3.312 36.277 7.032 ;
     RECT  36.277 2.208 36.373 7.032 ;
     RECT  35.957 23.184 36.373 23.736 ;
     RECT  36.373 23.184 36.461 24.552 ;
     RECT  36.461 23.184 36.497 23.88 ;
     RECT  36.637 0.192 36.721 0.216 ;
     RECT  35.417 14.256 36.781 14.28 ;
     RECT  36.373 1.728 37.043 7.032 ;
     RECT  37.043 2.148 37.285 7.032 ;
     RECT  37.333 0.288 37.381 0.312 ;
     RECT  36.497 23.328 37.465 23.88 ;
     RECT  37.381 0.288 37.469 0.552 ;
     RECT  37.285 2.148 37.508 7.08 ;
     RECT  36.373 12.528 37.508 12.552 ;
     RECT  36.781 13.68 37.508 14.28 ;
     RECT  37.465 23.328 37.508 23.928 ;
     RECT  37.469 0.288 37.619 0.312 ;
     RECT  37.508 2.148 37.804 23.928 ;
     RECT  37.804 13.68 38.125 15.048 ;
     RECT  38.125 13.68 38.147 14.856 ;
     RECT  37.804 2.148 38.156 2.28 ;
     RECT  38.147 13.68 38.195 14.28 ;
     RECT  37.804 23.088 38.197 23.928 ;
     RECT  38.156 1.68 38.243 2.28 ;
     RECT  38.195 13.68 38.771 13.704 ;
     RECT  38.243 1.728 38.821 2.28 ;
     RECT  37.804 3.36 38.821 7.416 ;
     RECT  38.821 1.728 39.125 7.416 ;
     RECT  38.197 23.088 39.125 24.552 ;
     RECT  39.109 12.528 39.197 12.552 ;
     RECT  38.725 0.144 39.34 0.168 ;
     RECT  39.157 14.832 39.373 14.856 ;
     RECT  39.125 1.728 39.953 7.368 ;
     RECT  39.125 23.088 40.069 24.024 ;
     RECT  39.953 2.148 40.208 7.368 ;
     RECT  39.373 14.256 40.208 14.856 ;
     RECT  40.069 22.752 40.208 24.024 ;
     RECT  40.069 0.288 40.403 0.312 ;
     RECT  40.208 2.148 40.403 24.024 ;
     RECT  40.403 2.148 40.457 23.928 ;
     RECT  40.457 2.148 40.504 23.502 ;
     RECT  40.504 2.148 40.565 7.368 ;
     RECT  40.504 12.528 40.645 13.128 ;
     RECT  40.645 12.528 40.753 12.552 ;
     RECT  40.565 2.148 41.171 7.128 ;
     RECT  41.171 2.148 41.177 6.936 ;
     RECT  40.504 22.752 41.177 23.448 ;
     RECT  41.177 2.148 41.237 6.888 ;
     RECT  41.177 22.8 41.497 23.448 ;
     RECT  41.237 1.728 41.861 6.888 ;
     RECT  41.929 14.832 42.012 14.856 ;
     RECT  41.861 3.936 42.277 6.888 ;
     RECT  41.497 22.8 42.469 23.496 ;
     RECT  42.181 24.528 42.469 24.552 ;
     RECT  42.469 22.8 42.509 24.552 ;
     RECT  42.277 3.936 42.677 6.936 ;
     RECT  41.861 1.728 42.908 2.856 ;
     RECT  42.677 3.936 42.908 6.984 ;
     RECT  42.037 10.8 42.908 10.824 ;
     RECT  42.012 14.832 42.908 14.904 ;
     RECT  42.509 22.8 42.908 23.928 ;
     RECT  42.757 0.528 42.977 0.552 ;
     RECT  42.908 1.728 43.204 23.928 ;
     RECT  43.204 1.728 43.331 6.984 ;
     RECT  43.204 23.376 43.337 23.928 ;
     RECT  43.204 12.528 43.345 12.552 ;
     RECT  43.331 1.728 43.715 6.888 ;
     RECT  43.715 1.728 44.051 2.28 ;
     RECT  44.005 24.528 44.345 24.552 ;
     RECT  43.715 3.312 44.377 6.888 ;
     RECT  44.377 3.312 44.461 7.416 ;
     RECT  43.337 23.376 44.629 23.448 ;
     RECT  44.461 3.312 44.773 6.84 ;
     RECT  44.051 1.728 44.963 1.752 ;
     RECT  43.204 14.256 45.169 14.28 ;
     RECT  44.156 0.144 45.349 0.168 ;
     RECT  44.773 2.784 45.485 6.84 ;
     RECT  45.485 2.784 45.493 6.888 ;
     RECT  44.629 23.376 45.493 23.88 ;
     RECT  45.349 0.144 45.587 0.264 ;
     RECT  45.493 23.376 45.587 23.928 ;
     RECT  45.493 2.148 45.608 6.888 ;
     RECT  45.421 13.104 45.608 13.128 ;
     RECT  45.169 14.256 45.608 14.856 ;
     RECT  45.587 23.376 45.608 23.88 ;
     RECT  45.608 2.148 45.712 23.88 ;
     RECT  45.712 2.16 45.904 23.88 ;
     RECT  45.587 0.144 46.019 0.216 ;
     RECT  45.904 23.28 46.145 23.88 ;
     RECT  45.904 13.68 46.585 13.704 ;
     RECT  46.019 0.144 46.691 0.168 ;
     RECT  45.904 12.528 46.757 12.552 ;
     RECT  45.904 2.16 46.789 7.416 ;
     RECT  46.789 1.728 46.973 7.416 ;
     RECT  46.973 2.208 47.081 7.416 ;
     RECT  47.005 14.256 47.089 14.856 ;
     RECT  46.145 23.28 47.153 23.592 ;
     RECT  47.153 23.376 47.297 23.592 ;
     RECT  47.125 0.528 47.585 0.552 ;
     RECT  47.081 2.256 47.761 7.416 ;
     RECT  47.804 0.144 47.891 0.216 ;
     RECT  47.761 2.256 48.308 7.512 ;
     RECT  47.905 12.528 48.308 12.552 ;
     RECT  47.089 14.256 48.308 14.28 ;
     RECT  47.365 23.712 48.308 23.976 ;
     RECT  48.308 2.148 48.604 23.976 ;
     RECT  47.891 0.192 48.755 0.216 ;
     RECT  48.604 2.148 49.237 7.416 ;
     RECT  48.604 22.656 49.237 23.976 ;
     RECT  49.237 22.656 49.493 24.552 ;
     RECT  49.237 1.824 49.517 7.416 ;
     RECT  49.493 22.656 49.612 23.736 ;
     RECT  49.612 22.656 49.709 23.448 ;
     RECT  49.517 1.728 49.765 7.416 ;
     RECT  50.588 0.144 50.675 0.168 ;
     RECT  49.709 23.376 50.773 23.448 ;
     RECT  50.773 23.376 50.965 23.88 ;
     RECT  49.765 1.728 51.008 7.512 ;
     RECT  50.461 12.528 51.008 12.552 ;
     RECT  50.353 13.68 51.008 13.704 ;
     RECT  50.965 23.376 51.008 23.928 ;
     RECT  51.008 1.728 51.304 23.928 ;
     RECT  51.349 25.104 51.545 25.128 ;
     RECT  51.304 2.736 51.635 2.76 ;
     RECT  51.304 23.376 51.685 23.928 ;
     RECT  51.685 23.376 51.797 24.552 ;
     RECT  51.797 23.376 52.013 23.592 ;
     RECT  51.304 3.936 52.403 7.416 ;
     RECT  51.304 1.728 52.94 1.752 ;
     RECT  52.403 3.936 52.981 6.12 ;
     RECT  52.013 23.376 53.221 23.496 ;
     RECT  52.94 1.728 53.365 2.28 ;
     RECT  52.981 3.408 53.365 6.12 ;
     RECT  52.403 7.296 53.365 7.416 ;
     RECT  53.221 23.376 53.449 23.736 ;
     RECT  53.372 0.144 53.459 0.168 ;
     RECT  53.197 12.528 53.485 12.552 ;
     RECT  53.365 1.728 53.708 6.12 ;
     RECT  53.365 7.296 53.708 7.464 ;
     RECT  53.485 12 53.708 12.552 ;
     RECT  53.449 23.184 53.708 23.736 ;
     RECT  53.708 1.728 53.797 23.772 ;
     RECT  53.797 1.728 54.004 23.928 ;
     RECT  53.797 0.288 54.131 0.312 ;
     RECT  54.004 23.376 54.133 23.928 ;
     RECT  54.133 23.376 54.137 24.552 ;
     RECT  54.004 1.728 54.317 7.416 ;
     RECT  54.86 0.144 54.947 0.168 ;
     RECT  54.137 24.528 55.037 24.552 ;
     RECT  54.317 1.728 55.091 6.936 ;
     RECT  54.004 14.256 55.141 14.28 ;
     RECT  55.141 14.256 55.189 14.856 ;
     RECT  55.189 14.256 55.289 14.952 ;
     RECT  54.137 23.376 55.289 23.544 ;
     RECT  55.091 3.888 55.361 6.936 ;
     RECT  55.091 1.728 55.379 2.904 ;
     RECT  55.379 1.728 56.408 2.856 ;
     RECT  55.361 4.224 56.408 6.936 ;
     RECT  55.289 14.256 56.408 14.28 ;
     RECT  55.289 23.376 56.408 23.448 ;
     RECT  56.437 0.528 56.581 0.552 ;
     RECT  56.408 1.728 56.581 23.772 ;
     RECT  56.581 1.728 56.704 23.88 ;
     RECT  56.704 4.224 56.819 6.168 ;
     RECT  56.704 1.728 56.867 3.048 ;
     RECT  56.581 0.288 56.869 0.552 ;
     RECT  56.819 5.76 56.915 6.168 ;
     RECT  56.704 14.4 56.915 14.424 ;
     RECT  56.867 1.728 56.953 3 ;
     RECT  56.869 0.192 57.011 0.552 ;
     RECT  56.953 2.832 57.017 3 ;
     RECT  56.704 23.376 57.017 23.88 ;
     RECT  57.017 2.832 57.025 2.904 ;
     RECT  57.011 0.528 57.089 0.552 ;
     RECT  56.915 5.76 57.877 6.12 ;
     RECT  57.877 5.76 57.925 6.216 ;
     RECT  57.025 2.832 57.997 2.856 ;
     RECT  56.953 1.728 58.165 1.848 ;
     RECT  56.819 4.224 58.165 4.68 ;
     RECT  57.925 5.76 58.165 6.936 ;
     RECT  57.017 23.376 58.561 23.784 ;
     RECT  58.165 4.224 58.645 6.936 ;
     RECT  58.165 1.728 58.741 2.28 ;
     RECT  58.561 22.752 58.741 23.784 ;
     RECT  58.645 4.08 58.796 6.936 ;
     RECT  58.741 1.152 58.825 2.28 ;
     RECT  58.741 22.752 58.889 24.552 ;
     RECT  58.825 1.728 59.108 2.28 ;
     RECT  58.796 3.744 59.108 6.936 ;
     RECT  58.813 13.104 59.108 13.128 ;
     RECT  58.889 22.752 59.108 23.928 ;
     RECT  59.108 1.728 59.404 23.928 ;
     RECT  59.317 0.576 59.465 0.6 ;
     RECT  59.404 22.8 59.555 23.928 ;
     RECT  59.555 22.8 59.596 23.448 ;
     RECT  59.404 6.096 59.789 6.696 ;
     RECT  59.404 2.88 60.041 2.904 ;
     RECT  59.596 23.376 60.437 23.448 ;
     RECT  60.437 23.376 60.565 23.4 ;
     RECT  59.789 6.096 60.793 6.648 ;
     RECT  59.404 1.728 60.905 1.752 ;
     RECT  60.764 2.736 61.189 2.76 ;
     RECT  61.189 2.736 61.477 2.904 ;
     RECT  60.565 22.752 61.477 23.4 ;
     RECT  59.941 24.528 61.477 24.552 ;
     RECT  61.477 22.752 61.481 24.552 ;
     RECT  60.793 6.096 61.513 6.84 ;
     RECT  61.477 2.736 61.729 3 ;
     RECT  61.729 1.776 61.808 3 ;
     RECT  59.404 4.368 61.808 4.68 ;
     RECT  61.513 6 61.808 6.84 ;
     RECT  61.481 22.752 61.808 23.928 ;
     RECT  61.808 1.776 61.985 23.928 ;
     RECT  61.985 1.776 62.104 23.88 ;
     RECT  62.104 23.376 62.147 23.88 ;
     RECT  62.104 1.776 62.201 2.04 ;
     RECT  62.389 1.728 62.701 1.752 ;
     RECT  62.701 1.104 62.785 1.752 ;
     RECT  62.104 3.696 62.957 6.84 ;
     RECT  62.725 25.104 63.029 25.128 ;
     RECT  63.241 0.528 63.347 0.552 ;
     RECT  62.957 3.696 63.529 6.648 ;
     RECT  62.147 23.376 63.637 23.448 ;
     RECT  63.637 23.376 63.925 23.544 ;
     RECT  62.785 1.728 64.508 1.752 ;
     RECT  63.529 3.264 64.508 6.648 ;
     RECT  63.925 23.376 64.508 23.736 ;
     RECT  64.508 1.728 64.549 23.772 ;
     RECT  64.549 1.728 64.804 23.928 ;
     RECT  64.804 2.88 64.972 7.176 ;
     RECT  64.804 1.728 64.973 1.8 ;
     RECT  64.804 23.376 64.973 23.928 ;
     RECT  64.972 2.88 65.189 6.84 ;
     RECT  65.189 4.224 65.225 6.84 ;
     RECT  64.804 10.8 65.549 10.824 ;
     RECT  64.973 23.376 65.549 23.736 ;
     RECT  65.189 2.88 65.657 3.24 ;
     RECT  65.225 4.944 65.941 6.84 ;
     RECT  65.657 3.216 66.125 3.24 ;
     RECT  65.941 4.944 66.265 7.464 ;
     RECT  66.373 25.104 66.629 25.128 ;
     RECT  64.973 1.728 66.977 1.752 ;
     RECT  66.977 1.728 67.208 1.8 ;
     RECT  66.265 4.656 67.208 7.464 ;
     RECT  66.841 10.8 67.208 10.824 ;
     RECT  65.549 23.376 67.208 23.448 ;
     RECT  67.208 1.728 67.285 23.772 ;
     RECT  67.285 1.728 67.504 23.928 ;
     RECT  67.504 2.88 67.673 2.904 ;
     RECT  67.504 22.752 67.817 23.928 ;
     RECT  67.504 4.464 68.465 7.464 ;
     RECT  67.504 1.728 68.788 1.752 ;
     RECT  68.788 1.728 68.905 1.8 ;
     RECT  68.465 4.464 69.452 6.84 ;
     RECT  69.452 4.08 69.469 6.84 ;
     RECT  69.469 4.08 69.493 7.752 ;
     RECT  69.493 3.408 69.733 7.752 ;
     RECT  68.905 1.728 69.908 1.752 ;
     RECT  69.733 2.88 69.908 8.184 ;
     RECT  67.817 22.752 69.908 23.736 ;
     RECT  69.908 1.728 70.069 23.772 ;
     RECT  70.069 1.728 70.204 23.88 ;
     RECT  70.204 2.88 70.625 8.184 ;
     RECT  70.625 2.88 70.697 6.888 ;
     RECT  70.697 4.416 70.913 6.888 ;
     RECT  70.204 22.752 70.94 23.88 ;
     RECT  70.94 22.752 71.027 23.976 ;
     RECT  71.027 22.752 71.273 23.496 ;
     RECT  70.913 4.464 71.489 6.888 ;
     RECT  70.204 1.728 72.181 1.752 ;
     RECT  71.273 23.376 72.181 23.496 ;
     RECT  72.421 2.88 72.457 2.904 ;
     RECT  72.181 23.376 72.517 23.592 ;
     RECT  72.421 0.192 72.563 0.216 ;
     RECT  72.181 1.728 72.608 1.8 ;
     RECT  72.457 2.88 72.608 3.144 ;
     RECT  71.489 4.464 72.608 6.84 ;
     RECT  70.625 8.16 72.608 8.184 ;
     RECT  72.517 23.376 72.608 23.88 ;
     RECT  72.608 1.728 72.805 23.88 ;
     RECT  72.805 1.728 72.904 23.928 ;
     RECT  72.904 1.728 72.965 2.04 ;
     RECT  72.904 23.376 73.717 23.928 ;
     RECT  72.904 3.84 73.948 8.184 ;
     RECT  73.948 7.584 73.955 8.184 ;
     RECT  73.717 23.376 74.185 23.976 ;
     RECT  74.185 23.28 74.441 23.976 ;
     RECT  73.948 3.84 74.941 6.6 ;
     RECT  73.955 8.16 74.941 8.184 ;
     RECT  74.941 3.84 74.965 8.184 ;
     RECT  74.965 2.88 75.193 8.184 ;
     RECT  72.965 1.728 75.308 1.752 ;
     RECT  75.193 2.88 75.308 8.472 ;
     RECT  74.293 10.8 75.308 10.824 ;
     RECT  74.441 23.28 75.308 23.928 ;
     RECT  75.308 1.728 75.604 23.928 ;
     RECT  75.604 1.728 75.701 4.584 ;
     RECT  75.701 1.728 75.731 2.232 ;
     RECT  75.604 23.376 75.809 23.928 ;
     RECT  75.701 3.84 76.025 4.584 ;
     RECT  75.877 25.104 76.205 25.128 ;
     RECT  75.604 5.856 76.741 7.464 ;
     RECT  75.604 8.448 76.741 8.472 ;
     RECT  76.741 5.856 76.979 8.472 ;
     RECT  75.809 23.376 77.077 23.736 ;
     RECT  76.979 5.856 77.101 7.224 ;
     RECT  76.025 4.416 77.173 4.584 ;
     RECT  77.101 5.568 77.173 7.224 ;
     RECT  75.731 1.728 77.321 1.8 ;
     RECT  77.077 23.376 77.429 23.976 ;
     RECT  77.413 2.88 77.893 2.904 ;
     RECT  77.429 23.376 77.893 23.928 ;
     RECT  77.893 2.88 78.008 2.952 ;
     RECT  77.173 4.416 78.008 7.224 ;
     RECT  76.979 8.448 78.008 8.472 ;
     RECT  77.893 22.752 78.008 23.928 ;
     RECT  78.008 2.148 78.083 23.928 ;
     RECT  78.083 2.148 78.112 23.88 ;
     RECT  78.112 2.418 78.304 23.88 ;
     RECT  78.304 22.656 78.412 23.88 ;
     RECT  78.412 22.656 78.445 23.784 ;
     RECT  77.893 0.192 78.467 0.216 ;
     RECT  78.304 2.88 78.659 2.952 ;
     RECT  78.445 22.656 78.659 23.736 ;
     RECT  78.304 4.752 78.707 7.992 ;
     RECT  78.659 22.656 79.301 23.592 ;
     RECT  78.707 4.752 79.373 6.312 ;
     RECT  79.301 23.376 80.149 23.592 ;
     RECT  78.707 7.344 80.233 7.992 ;
     RECT  79.373 5.328 80.293 6.312 ;
     RECT  80.233 7.344 80.293 8.28 ;
     RECT  78.659 2.88 80.485 2.904 ;
     RECT  80.293 5.328 80.485 8.28 ;
     RECT  80.485 2.88 80.521 3.384 ;
     RECT  79.237 1.728 80.708 1.752 ;
     RECT  80.521 2.88 80.708 3.576 ;
     RECT  80.485 5.136 80.708 8.28 ;
     RECT  80.549 12.528 80.708 12.552 ;
     RECT  80.149 23.376 80.708 23.88 ;
     RECT  80.708 1.728 80.773 23.88 ;
     RECT  80.773 1.728 81.004 23.928 ;
     RECT  81.061 0.192 81.203 0.216 ;
     RECT  81.004 2.88 81.209 9 ;
     RECT  81.004 14.256 81.347 15.432 ;
     RECT  81.209 2.928 81.461 9 ;
     RECT  81.004 23.376 81.497 23.928 ;
     RECT  81.461 3.648 81.533 9 ;
     RECT  81.533 4.8 81.569 9 ;
     RECT  81.569 8.976 81.731 9 ;
     RECT  81.347 14.256 81.779 14.856 ;
     RECT  81.004 12.528 81.827 12.552 ;
     RECT  81.779 14.832 81.875 14.856 ;
     RECT  81.004 1.728 82.019 1.8 ;
     RECT  81.533 3.648 82.501 3.672 ;
     RECT  81.569 4.8 82.501 7.992 ;
     RECT  82.501 3.648 82.573 7.992 ;
     RECT  82.573 3.648 82.597 8.712 ;
     RECT  82.597 2.88 82.861 8.712 ;
     RECT  82.105 13.68 82.897 13.848 ;
     RECT  81.497 23.376 82.933 23.736 ;
     RECT  82.933 23.376 83.117 24.552 ;
     RECT  83.117 23.376 83.257 23.976 ;
     RECT  82.019 1.728 83.408 1.752 ;
     RECT  82.861 2.88 83.408 9 ;
     RECT  82.897 13.68 83.408 14.808 ;
     RECT  83.257 23.136 83.408 23.976 ;
     RECT  83.269 0.288 83.555 0.312 ;
     RECT  83.408 1.728 83.704 23.976 ;
     RECT  83.704 3.312 83.765 5.496 ;
     RECT  83.704 7.68 83.765 8.472 ;
     RECT  83.704 1.728 83.797 1.752 ;
     RECT  83.797 1.008 83.801 1.752 ;
     RECT  83.765 5.472 83.801 5.496 ;
     RECT  83.801 1.008 83.891 1.128 ;
     RECT  83.765 3.936 84.053 4.488 ;
     RECT  83.704 23.952 84.053 23.976 ;
     RECT  83.765 8.448 84.125 8.472 ;
     RECT  84.053 3.936 84.161 3.96 ;
     RECT  83.891 1.008 84.179 1.032 ;
     RECT  83.221 25.104 84.179 25.128 ;
    LAYER M5 ;
     RECT  20.016 0.133 20.04 0.144 ;
     RECT  22.464 0.133 23.64 0.144 ;
     RECT  25.2 0.133 25.224 0.144 ;
     RECT  34.416 0.133 34.44 0.144 ;
     RECT  35.616 0.133 36.264 0.144 ;
     RECT  38.736 0.133 39.288 0.144 ;
     RECT  44.208 0.133 46.68 0.144 ;
     RECT  47.856 0.133 47.88 0.144 ;
     RECT  50.64 0.133 50.664 0.144 ;
     RECT  53.424 0.133 53.448 0.144 ;
     RECT  54.912 0.133 54.936 0.144 ;
     RECT  2.4 0.144 84.168 1.043 ;
     RECT  2.4 1.043 83.88 1.139 ;
     RECT  2.4 1.139 83.304 1.763 ;
     RECT  2.4 1.763 3.624 1.811 ;
     RECT  5.1 1.763 8.52 1.811 ;
     RECT  67.008 1.763 67.656 1.811 ;
     RECT  68.832 1.763 70.68 1.811 ;
     RECT  72.192 1.763 72.912 1.811 ;
     RECT  74.976 1.763 83.304 1.811 ;
     RECT  56.4 1.763 59.976 1.859 ;
     RECT  61.2 1.763 62.136 2.051 ;
     RECT  82.608 1.811 83.304 2.137 ;
     RECT  82.608 2.137 83.52 2.151 ;
     RECT  9.744 1.763 10.968 2.291 ;
     RECT  9.744 2.291 10.812 2.339 ;
     RECT  15.744 1.763 51.312 2.339 ;
     RECT  22.752 2.339 51.312 2.725 ;
     RECT  52.992 1.763 55.368 2.725 ;
     RECT  56.4 1.859 57 2.725 ;
     RECT  58.176 1.859 59.976 2.725 ;
     RECT  61.2 2.051 62.112 2.725 ;
     RECT  52.992 2.725 57 2.821 ;
     RECT  58.176 2.725 62.112 2.821 ;
     RECT  5.1 1.811 6.072 2.915 ;
     RECT  7.296 1.811 8.52 2.915 ;
     RECT  15.744 2.339 21.612 2.915 ;
     RECT  52.992 2.821 62.112 2.915 ;
     RECT  64.5 1.763 65.496 2.915 ;
     RECT  67.2 1.811 67.656 2.915 ;
     RECT  69.744 1.811 70.68 2.915 ;
     RECT  72.432 1.811 72.912 2.915 ;
     RECT  74.976 1.811 76.2 2.915 ;
     RECT  77.424 1.811 81.192 2.915 ;
     RECT  77.904 2.915 78.648 2.963 ;
     RECT  52.992 2.915 56.952 3.011 ;
     RECT  10.368 2.339 10.812 3.059 ;
     RECT  52.992 3.011 56.856 3.059 ;
     RECT  22.752 2.725 51.624 3.349 ;
     RECT  69.744 2.915 70.392 3.397 ;
     RECT  22.704 3.349 51.624 3.443 ;
     RECT  69.504 3.397 70.392 3.491 ;
     RECT  80.496 2.915 81.192 3.637 ;
     RECT  82.608 2.151 83.712 3.637 ;
     RECT  72.6 2.915 72.912 3.829 ;
     RECT  15.9 2.915 21.612 3.877 ;
     RECT  22.704 3.443 37.812 3.877 ;
     RECT  39.024 3.443 51.624 3.925 ;
     RECT  52.992 3.059 56.712 3.925 ;
     RECT  15.9 3.877 37.812 4.067 ;
     RECT  69.504 3.491 70.212 4.115 ;
     RECT  13.2 1.763 13.752 4.261 ;
     RECT  7.68 2.915 8.28 4.453 ;
     RECT  69.9 4.115 70.212 4.453 ;
     RECT  72.6 3.829 73.896 4.453 ;
     RECT  5.1 2.915 5.412 4.501 ;
     RECT  15.9 4.067 25.128 4.595 ;
     RECT  26.7 4.067 37.812 4.595 ;
     RECT  39.024 3.925 56.712 4.595 ;
     RECT  60.816 2.915 62.112 4.595 ;
     RECT  75.3 2.915 76.2 4.595 ;
     RECT  44.928 4.595 56.712 4.645 ;
     RECT  67.2 2.915 67.512 4.645 ;
     RECT  72.48 4.453 73.896 4.645 ;
     RECT  15.9 4.595 17.448 4.739 ;
     RECT  78 2.963 78.312 4.741 ;
     RECT  2.4 1.811 2.712 4.837 ;
     RECT  6.816 4.453 8.28 5.075 ;
     RECT  69.9 4.453 70.584 5.077 ;
     RECT  18.432 4.595 25.128 5.125 ;
     RECT  4.656 4.501 5.412 5.171 ;
     RECT  18.432 5.125 25.416 5.171 ;
     RECT  80.496 3.637 83.712 5.171 ;
     RECT  13.2 4.261 14.376 5.219 ;
     RECT  29.04 4.595 37.812 5.219 ;
     RECT  71.616 4.645 73.896 5.219 ;
     RECT  29.04 5.219 33.24 5.267 ;
     RECT  44.928 4.645 56.808 5.315 ;
     RECT  77.472 4.741 78.312 5.317 ;
     RECT  10.5 3.059 10.812 5.365 ;
     RECT  10.5 5.365 11.4 5.413 ;
     RECT  26.7 4.595 27.912 5.605 ;
     RECT  29.04 5.267 33.048 5.605 ;
     RECT  34.56 5.219 37.812 5.605 ;
     RECT  39.024 4.595 43.896 5.605 ;
     RECT  2.4 4.837 3.672 5.747 ;
     RECT  26.7 5.605 33.048 5.747 ;
     RECT  34.56 5.605 43.896 5.747 ;
     RECT  67.2 4.645 68.472 5.747 ;
     RECT  69.504 5.077 70.584 5.747 ;
     RECT  71.616 5.219 72.912 5.747 ;
     RECT  77.472 5.317 78.696 5.845 ;
     RECT  15.9 4.739 16.872 5.989 ;
     RECT  10.32 5.413 11.4 6.083 ;
     RECT  18.432 5.171 22.92 6.083 ;
     RECT  67.2 5.747 67.512 6.085 ;
     RECT  44.976 5.315 56.808 6.133 ;
     RECT  72.6 5.747 72.912 6.181 ;
     RECT  73.92 5.845 73.944 6.181 ;
     RECT  77.088 5.845 78.696 6.229 ;
     RECT  69.504 5.747 70.212 6.275 ;
     RECT  7.536 5.075 8.28 6.277 ;
     RECT  13.2 5.219 14.28 6.323 ;
     RECT  18.6 6.083 22.92 6.323 ;
     RECT  15.9 5.989 17.448 6.371 ;
     RECT  24 5.171 25.416 6.371 ;
     RECT  76.944 6.229 78.696 6.371 ;
     RECT  34.56 5.747 43.752 6.419 ;
     RECT  25.392 6.371 25.416 6.515 ;
     RECT  44.976 6.133 56.904 6.515 ;
     RECT  69.648 6.275 70.212 6.515 ;
     RECT  64.5 2.915 64.812 6.565 ;
     RECT  30.72 5.747 33.048 6.707 ;
     RECT  80.592 5.171 83.712 6.709 ;
     RECT  18.6 6.323 21.612 6.803 ;
     RECT  28.464 5.747 29.712 6.803 ;
     RECT  22.656 6.323 22.92 6.805 ;
     RECT  24 6.371 24.408 6.805 ;
     RECT  34.656 6.419 43.752 6.805 ;
     RECT  44.976 6.515 54.012 6.805 ;
     RECT  75.3 4.595 75.612 6.805 ;
     RECT  10.32 6.083 10.812 6.899 ;
     RECT  34.656 6.805 54.012 6.899 ;
     RECT  22.656 6.805 24.408 6.947 ;
     RECT  52.368 6.899 54.012 6.947 ;
     RECT  57.936 2.915 59.412 6.947 ;
     RECT  67.104 6.085 67.512 6.947 ;
     RECT  31.488 6.707 33.048 7.043 ;
     RECT  34.656 6.899 48.612 7.139 ;
     RECT  64.5 6.565 64.92 7.187 ;
     RECT  34.656 7.139 40.728 7.331 ;
     RECT  53.184 6.947 54.012 7.331 ;
     RECT  26.7 5.747 27.192 7.379 ;
     RECT  72.6 6.181 73.944 7.379 ;
     RECT  80.304 6.709 83.712 7.379 ;
     RECT  13.2 6.323 14.232 7.475 ;
     RECT  17.424 6.371 17.448 7.475 ;
     RECT  65.952 6.805 65.976 7.475 ;
     RECT  75.3 6.805 75.864 7.475 ;
     RECT  49.776 6.899 51.312 7.523 ;
     RECT  7.536 6.277 9.192 7.619 ;
     RECT  73.92 7.379 73.944 7.619 ;
     RECT  78 6.371 78.696 7.619 ;
     RECT  80.496 7.379 83.712 7.907 ;
     RECT  76.944 6.371 76.968 8.003 ;
     RECT  78 7.619 78.408 8.003 ;
     RECT  69.744 6.515 70.212 8.195 ;
     RECT  7.536 7.619 8.28 12.563 ;
     RECT  20.16 6.803 21.612 12.563 ;
     RECT  22.896 6.947 24.408 12.563 ;
     RECT  31.488 7.043 32.952 12.563 ;
     RECT  34.8 7.331 40.728 12.563 ;
     RECT  53.232 7.331 54.012 12.563 ;
     RECT  80.592 7.907 83.712 12.563 ;
     RECT  0.24 6.565 0.264 12.995 ;
     RECT  22.896 12.563 24.312 13.139 ;
     RECT  36.864 12.563 40.632 13.139 ;
     RECT  58.848 6.947 59.412 13.139 ;
     RECT  13.2 7.475 13.656 13.331 ;
     RECT  36.864 13.139 40.512 13.715 ;
     RECT  41.952 7.139 48.612 13.715 ;
     RECT  50.4 7.523 51.312 13.715 ;
     RECT  80.7 12.563 83.712 13.859 ;
     RECT  7.536 12.563 8.112 14.291 ;
     RECT  20.16 12.563 20.184 14.291 ;
     RECT  32.1 12.563 32.952 14.291 ;
     RECT  34.8 12.563 35.88 14.291 ;
     RECT  36.864 13.715 38.184 14.291 ;
     RECT  41.952 13.715 45.912 14.291 ;
     RECT  47.04 13.715 48.612 14.291 ;
     RECT  55.152 6.515 56.904 14.291 ;
     RECT  83.136 13.859 83.712 14.291 ;
     RECT  56.4 14.291 56.904 14.435 ;
     RECT  23.328 13.139 24.312 14.627 ;
     RECT  7.632 14.291 8.112 14.675 ;
     RECT  34.8 14.291 35.304 14.867 ;
     RECT  37.5 14.291 38.136 14.867 ;
     RECT  39.312 13.715 40.512 14.867 ;
     RECT  41.952 14.291 43.212 14.867 ;
     RECT  45.408 14.291 45.912 14.867 ;
     RECT  47.04 14.291 47.064 14.867 ;
     RECT  55.152 14.291 55.224 14.867 ;
     RECT  80.7 13.859 81.864 14.867 ;
     RECT  42.048 14.867 43.212 14.915 ;
     RECT  55.2 14.867 55.224 14.963 ;
     RECT  37.5 14.867 38.088 15.059 ;
     RECT  80.7 14.867 81.336 15.443 ;
     RECT  34.8 14.867 35.112 22.501 ;
     RECT  10.5 6.899 10.812 22.645 ;
     RECT  48.3 14.291 48.612 22.645 ;
     RECT  78 8.003 78.312 22.645 ;
     RECT  40.2 14.867 40.512 22.741 ;
     RECT  67.2 6.947 67.512 22.741 ;
     RECT  69.9 8.195 70.212 22.741 ;
     RECT  78 22.645 78.408 22.741 ;
     RECT  18.6 6.803 18.912 22.789 ;
     RECT  59.1 13.139 59.412 22.789 ;
     RECT  2.4 5.747 2.712 23.365 ;
     RECT  5.1 5.171 5.412 23.365 ;
     RECT  7.8 14.675 8.112 23.365 ;
     RECT  10.5 22.645 11.592 23.365 ;
     RECT  13.2 13.331 13.512 23.365 ;
     RECT  15.9 6.371 16.212 23.365 ;
     RECT  18.288 22.789 18.912 23.365 ;
     RECT  21.3 12.563 21.612 23.365 ;
     RECT  24 14.627 24.312 23.365 ;
     RECT  26.7 7.379 27.012 23.365 ;
     RECT  29.4 6.803 29.712 23.365 ;
     RECT  32.1 14.291 32.412 23.365 ;
     RECT  34.8 22.501 35.208 23.365 ;
     RECT  37.5 15.059 37.812 23.365 ;
     RECT  40.08 22.741 40.512 23.365 ;
     RECT  42.9 14.915 43.212 23.365 ;
     RECT  45.6 14.867 45.912 23.365 ;
     RECT  48.3 22.645 48.936 23.365 ;
     RECT  51 13.715 51.312 23.365 ;
     RECT  53.7 12.563 54.012 23.365 ;
     RECT  56.4 14.435 56.712 23.365 ;
     RECT  59.1 22.789 59.544 23.365 ;
     RECT  60.576 22.741 60.6 23.365 ;
     RECT  61.8 4.595 62.112 23.365 ;
     RECT  64.5 7.187 64.812 23.365 ;
     RECT  67.2 22.741 68.232 23.365 ;
     RECT  69.9 22.741 70.392 23.365 ;
     RECT  72.6 7.379 72.912 23.365 ;
     RECT  75.3 7.475 75.612 23.365 ;
     RECT  77.904 22.741 78.408 23.365 ;
     RECT  80.7 15.443 81.012 23.365 ;
     RECT  83.4 14.291 83.712 23.365 ;
     RECT  2.4 23.365 8.856 23.413 ;
     RECT  10.032 23.365 12.216 23.413 ;
     RECT  13.2 23.365 13.752 23.413 ;
     RECT  15.264 23.365 16.488 23.413 ;
     RECT  17.712 23.365 18.912 23.413 ;
     RECT  37.296 23.365 37.812 23.413 ;
     RECT  48.3 23.365 54.012 23.413 ;
     RECT  55.344 23.365 57.816 23.413 ;
     RECT  59.1 23.365 63.048 23.413 ;
     RECT  64.224 23.365 71.304 23.413 ;
     RECT  20.448 23.365 24.456 23.461 ;
     RECT  42.9 23.365 46.824 23.461 ;
     RECT  48.3 23.413 71.304 23.461 ;
     RECT  72.6 23.365 74.088 23.461 ;
     RECT  48.3 23.461 74.088 23.509 ;
     RECT  75.3 23.365 83.712 23.509 ;
     RECT  2.4 23.413 18.912 23.701 ;
     RECT  20.16 23.461 24.456 23.701 ;
     RECT  25.632 23.365 29.712 23.701 ;
     RECT  31.776 23.365 35.784 23.701 ;
     RECT  37.296 23.413 37.944 23.701 ;
     RECT  39.744 23.365 41.928 23.701 ;
     RECT  42.9 23.461 47.112 23.701 ;
     RECT  48.3 23.509 83.712 23.701 ;
     RECT  31.152 23.701 38.52 23.845 ;
     RECT  39.744 23.701 83.712 23.845 ;
     RECT  2.4 23.701 29.712 23.893 ;
     RECT  2.4 23.893 29.976 23.941 ;
     RECT  31.152 23.845 83.712 23.941 ;
     RECT  2.4 23.941 83.88 25.093 ;
     RECT  2.4 25.093 84.168 25.744 ;
  END
END ot_s81_sstn_payload536
END LIBRARY
